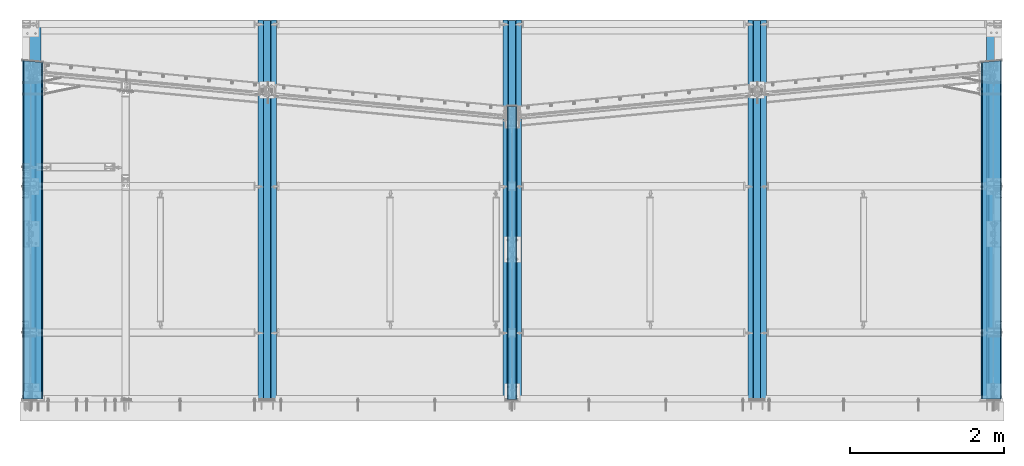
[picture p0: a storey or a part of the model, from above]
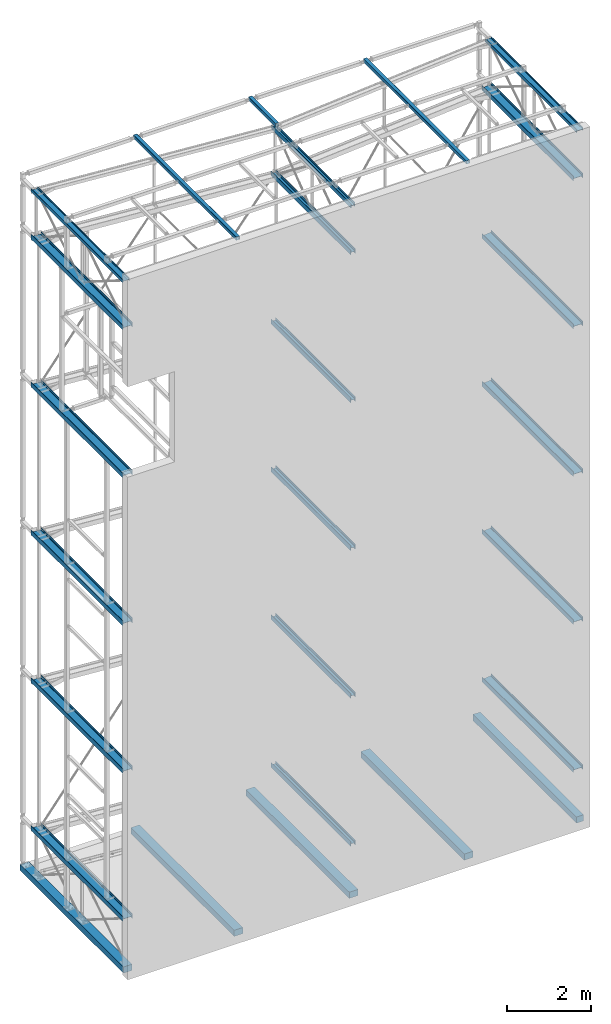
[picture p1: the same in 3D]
Properties of the parts of a building model (IFC2X3), part 1 of 3

# File
Description: ViewDefinition[CoordinationView_V2.0, QuantityTakeOffAddOnView], Option [BaseQuantities:On], Option [GridExport:On], Option [Assemblies:On], Option [Bolts:On], Option [Rebars:On], Option [PourObjects:Off], Option [Welds:Off], Option [SurfaceTreatments:Off], Option [LocationBy:0], Option [ViewColors:Off], Option [SectionedSpine:Off], Option [PropertySets:On], Option [Export all:On]
File name: Model-IFC.ifc
Time: 2023-10-02T23:28:33
Author: YESKON06\Patrycja Reder
Organization: Structural Designer
Written by: IFC Database Version: Work
Made in: Tekla Structures 2020 Service Pack 14, IFC Export Version: 4.0.0.0 Sep 15 2022

# IfcBuildingStorey, Undefined
In: Undefined
Elevation: 0 mm

# IfcBeam: 180*180 (3)
In: Undefined
Description: 180*180; Material: CONCRETE/C25/30
Tekla Common - Bottom elevation: -0.196; Top elevation: -0.016; Phase: 1; Class: 11
Tekla Quantity - Area per tons: 9.3 m2; Height: 180 mm; Width: 180 mm
Pset_BeamCommon - LoadBearing: no; Reference: B0(?)
Name | Weight (kg) | Volume (m3) | Gross footprint area (m2) | Net surface area (m2) | Tekla Quantity, Length (mm) | BaseQuantities, Length (mm) | OuterSurfaceArea (m2) | NetVolume (m3) | NetWeight (kg)
BELKA | 989.1 | 0.4 | 2.3 | 9.2 | 12720 | 12720 | 9.2232 | 0.412128 | 989.107
2 x BELKA | 475.6 | 0.2 | 0 | 4.5 | 6116 | 6116.04 | 4.46835 | 0.19816 | 475.583

# IfcBeam: 180*4935, BELKA
In: Undefined
Description: 180*4935; Material: CONCRETE/C25/30
Pset_BeamCommon - LoadBearing: no; Reference: B0(?)
Tekla Common - Bottom elevation: -0.196; Top elevation: -0.016; Phase: 1; Class: 1
Tekla Quantity - Weight: 27118 kg; Volume: 11.3 m3; Gross footprint area: 2.3 m2; Area per tons: 4.9 m2; Net surface area: 131.9 m2; Height: 180 mm; Width: 4935 mm; Length: 12720 mm
BaseQuantities - Length: 12720 mm; OuterSurfaceArea: 131.902 m2; NetVolume: 11.2992 m3; NetWeight: 27118 kg

# IfcBeam: BL10*135, BLACHA
In: Undefined
Description: BL10*135; Material: STEEL/S355JR
Tekla Common - Bottom elevation: +14.256; Top elevation: +14.391; Phase: 13; Class: 99
Tekla Quantity - Weight: 2.1 kg; Volume: 0 m3; Gross footprint area: 0 m2; Area per tons: 28.6 m2; Net surface area: 0.1 m2; Height: 135 mm; Width: 10 mm; Length: 200 mm
Pset_BeamCommon - LoadBearing: no; Reference: 1116(?)
BaseQuantities - Length: 199.998 mm; OuterSurfaceArea: 0.0606994 m2; NetVolume: 0.000269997 m3; NetWeight: 2.11948 kg

# IfcBeam: BL10*91 (2)
In: Undefined
Description: BL10*91; Material: STEEL/S355JR
Tekla Common - Bottom elevation: +19.959; Top elevation: +20.050; Phase: 3; Class: 99
Tekla Quantity - Weight: 2.2 kg; Volume: 0 m3; Gross footprint area: 0 m2; Area per tons: 29.1 m2; Net surface area: 0.1 m2; Height: 91 mm; Width: 10 mm; Length: 307 mm
Pset_BeamCommon - LoadBearing: no; Reference: 1057
BaseQuantities - Length: 307 mm; OuterSurfaceArea: 0.063834 m2; NetVolume: 0.00027937 m3; NetWeight: 2.19305 kg

# IfcBeam: BL12*110 (2)
In: Undefined
Description: BL12*110; Material: STEEL/S355JR
Tekla Common - Bottom elevation: +19.949; Top elevation: +20.059; Phase: 2; Class: 99
Tekla Quantity - Weight: 2 kg; Volume: 0 m3; Gross footprint area: 0 m2; Area per tons: 24.9 m2; Net surface area: 0 m2; Height: 110 mm; Width: 12 mm; Length: 190 mm
Pset_BeamCommon - LoadBearing: no; Reference: 1034
BaseQuantities - Length: 190 mm; OuterSurfaceArea: 0.049 m2; NetVolume: 0.0002508 m3; NetWeight: 1.96878 kg

# IfcBeam: BL12*120 (5)
In: Undefined
Description: BL12*120; Material: STEEL/S355JR
Tekla Common - Phase: 13; Class: 99
Tekla Quantity - Weight: 1.7 kg; Volume: 0 m3; Gross footprint area: 0 m2; Net surface area: 0 m2; Height: 120 mm; Width: 12 mm
Pset_BeamCommon - LoadBearing: no
Name | Bottom elevation | Top elevation | Area per tons (m2) | Tekla Quantity, Length (mm) = BaseQuantities, Length (mm) | Reference | OuterSurfaceArea (m2) | NetVolume (m3) | NetWeight (kg)
BLACHA_PODSTAWY | +14.242 | +14.392 | 25.1 | 150 | 1104 | 0.04248 | 0.000216 | 1.6956
BLACHA_PODSTAWY | +14.654 | +14.814 | 24.9 | 160 | 1102 | 0.04512 | 0.0002304 | 1.80864
BLACHA_PODSTAWY | +16.014 | +16.174 | 24.9 | 160 | 1102 | 0.04512 | 0.0002304 | 1.80864
BLACHA_PODSTAWY | +17.144 | +17.294 | 25.1 | 150 | 1104 | 0.04248 | 0.000216 | 1.6956
BLACHA_PODSTAWY | +17.144 | +17.304 | 24.9 | 160 | 1102 | 0.04512 | 0.0002304 | 1.80864

# IfcBeam: BL12*135 (10)
In: Undefined
Description: BL12*135; Material: STEEL/S355JR
Tekla Common - Phase: 3; Class: 99
Tekla Quantity - Weight: 5.8 kg; Volume: 0 m3; Gross footprint area: 0 m2; Area per tons: 23.7 m2; Net surface area: 0.1 m2; Height: 135 mm; Width: 12 mm; Length: 461 mm
Pset_BeamCommon - LoadBearing: no; Reference: 1026
BaseQuantities - Length: 461 mm; OuterSurfaceArea: 0.138774 m2; NetVolume: 0.00074682 m3; NetWeight: 5.86254 kg
Name | Bottom elevation | Top elevation
2 x BLACHA | +5.617 | +5.752
2 x BLACHA | +9.937 | +10.072
2 x BLACHA | +14.257 | +14.392
2 x BLACHA | +18.577 | +18.712
2 x BLACHA | +1.297 | +1.432

# IfcBeam: BL12*160 (6)
In: Undefined
Description: BL12*160; Material: STEEL/S355JR
Tekla Common - Phase: 5; Class: 99
Tekla Quantity - Volume: 0 m3; Gross footprint area: 0 m2; Height: 160 mm; Width: 12 mm
Pset_BeamCommon - LoadBearing: no
Name | Bottom elevation | Top elevation | Weight (kg) | Area per tons (m2) | Net surface area (m2) | Tekla Quantity, Length (mm) = BaseQuantities, Length (mm) | Reference | OuterSurfaceArea (m2) | NetVolume (m3) | NetWeight (kg)
BLACHA_PODSTAWY | +1.284 | +1.444 | 2.3 | 24.5 | 0.1 | 153 | 1038 | 0.056472 | 0.00029376 | 2.30602
BLACHA_PODSTAWY | +19.924 | +20.084 | 2 | 24.7 | 0 | 134 | 1039 | 0.049936 | 0.00025728 | 2.01965
BLACHA_PODSTAWY | +18.564 | +18.724 | 2.3 | 24.5 | 0.1 | 153 | 1038 | 0.056472 | 0.00029376 | 2.30602
BLACHA_PODSTAWY | +5.604 | +5.764 | 2.3 | 24.5 | 0.1 | 153 | 1038 | 0.056472 | 0.00029376 | 2.30602
BLACHA_PODSTAWY | +9.924 | +10.084 | 2.3 | 24.5 | 0.1 | 153 | 1038 | 0.056472 | 0.00029376 | 2.30602
BLACHA_PODSTAWY | +14.244 | +14.404 | 2.3 | 24.5 | 0.1 | 153 | 1038 | 0.056472 | 0.00029376 | 2.30602

# IfcBeam: BL12*165 (2)
In: Undefined
Description: BL12*165; Material: STEEL/S355JR
Tekla Common - Bottom elevation: +20.039; Top elevation: +20.204; Phase: 4; Class: 99
Tekla Quantity - Weight: 3.1 kg; Volume: 0 m3; Gross footprint area: 0 m2; Area per tons: 24 m2; Net surface area: 0.1 m2; Height: 165 mm; Width: 12 mm; Length: 200 mm
Pset_BeamCommon - LoadBearing: no; Reference: 1045
BaseQuantities - Length: 200 mm; OuterSurfaceArea: 0.07476 m2; NetVolume: 0.000396 m3; NetWeight: 3.1086 kg

# IfcBeam: BL16*148, BLACHA_PODSTAWY
In: Undefined
Description: BL16*148; Material: STEEL/S355JR
Tekla Common - Bottom elevation: +14.244; Top elevation: +14.392; Phase: 2; Class: 99
Tekla Quantity - Weight: 5.1 kg; Volume: 0 m3; Gross footprint area: 0 m2; Area per tons: 18.6 m2; Net surface area: 0.1 m2; Height: 148 mm; Width: 16 mm; Length: 280 mm
Pset_BeamCommon - LoadBearing: no; Reference: 1106
BaseQuantities - Length: 280 mm; OuterSurfaceArea: 0.096576 m2; NetVolume: 0.00066304 m3; NetWeight: 5.20486 kg

# IfcBeam: BL16*160 (9)
In: Undefined
Description: BL16*160; Material: STEEL/S355JR
Tekla Common - Phase: 2; Class: 99
Tekla Quantity - Weight: 5.6 kg; Volume: 0 m3; Gross footprint area: 0 m2; Area per tons: 18.4 m2; Net surface area: 0.1 m2; Height: 160 mm; Width: 16 mm; Length: 280 mm
Pset_BeamCommon - LoadBearing: no
BaseQuantities - Length: 280 mm; OuterSurfaceArea: 0.10368 m2; NetVolume: 0.0007168 m3; NetWeight: 5.62688 kg
Name | Bottom elevation | Top elevation | Reference
BLACHA_PODSTAWY | +1.284 | +1.444 | 1033
2 x BLACHA_PODSTAWY | +5.604 | +5.764 | 1033
2 x BLACHA_PODSTAWY | +9.924 | +10.084 | 1033
BLACHA_PODSTAWY | +14.244 | +14.404 | 1033
2 x BLACHA_PODSTAWY | +18.564 | +18.724 | 1033
BLACHA_PODSTAWY | +1.284 | +1.444 | 1033(?)

# IfcBeam: BL4*100 (15)
In: Undefined
Description: BL4*100; Material: STEEL/S355JR
Tekla Quantity - Weight: 0.4 kg; Volume: 0 m3; Gross footprint area: 0 m2; Area per tons: 68.8 m2; Net surface area: 0 m2; Height: 100 mm; Width: 4 mm; Length: 100 mm
BaseQuantities - Length: 100 mm; OuterSurfaceArea: 0.0216 m2; NetVolume: 0.00004 m3; NetWeight: 0.314 kg
Tekla Common - Class: 99
Pset_BeamCommon - LoadBearing: no
Name | Bottom elevation | Top elevation | Phase | Reference
BLACHA | +20.104 | +20.204 | 5 | 1064
2 x BLACHA | +20.104 | +20.204 | 4 | 1064
BLACHA | +1.314 | +1.414 | 2 | 1064(?)
2 x BLACHA | +5.634 | +5.734 | 2 | 1064
2 x BLACHA | +9.954 | +10.054 | 2 | 1064
2 x BLACHA | +14.274 | +14.374 | 2 | 1064
2 x BLACHA | +18.594 | +18.694 | 2 | 1064
2 x BLACHA | +19.954 | +20.054 | 2 | 1064
BLACHA | +1.314 | +1.414 | 2 | 1064

# IfcBeam: BL6*120, BLACHA
In: Undefined
Description: BL6*120; Material: STEEL/S355JR
Tekla Common - Bottom elevation: +19.944; Top elevation: +20.064; Phase: 5; Class: 99
Tekla Quantity - Weight: 0.7 kg; Volume: 0 m3; Gross footprint area: 0 m2; Area per tons: 47 m2; Net surface area: 0 m2; Height: 120 mm; Width: 6 mm; Length: 104 mm
Pset_BeamCommon - LoadBearing: no; Reference: 1043
BaseQuantities - Length: 104 mm; OuterSurfaceArea: 0.027648 m2; NetVolume: 0.00007488 m3; NetWeight: 0.587808 kg

# IfcBeam: BL6*160 (2)
In: Undefined
Description: BL6*160; Material: STEEL/S355JR
Tekla Common - Bottom elevation: +19.894; Top elevation: +20.054; Phase: 2; Class: 99
Tekla Quantity - Weight: 1.5 kg; Volume: 0 m3; Gross footprint area: 0 m2; Area per tons: 45.5 m2; Net surface area: 0.1 m2; Height: 160 mm; Width: 6 mm; Length: 180.8 mm
Pset_BeamCommon - LoadBearing: no; Reference: 1056
BaseQuantities - Length: 180.799 mm; OuterSurfaceArea: 0.0619453 m2; NetVolume: 0.000173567 m3; NetWeight: 1.3625 kg

# IfcBeam: BL8*140 (5)
In: Undefined
Description: BL8*140; Material: STEEL/S355JR
Tekla Common - Phase: 5; Class: 99
Tekla Quantity - Weight: 1.1 kg; Volume: 0 m3; Gross footprint area: 0 m2; Area per tons: 35.7 m2; Net surface area: 0 m2; Height: 140 mm; Width: 8 mm; Length: 123 mm
Pset_BeamCommon - LoadBearing: no; Reference: 1040
BaseQuantities - Length: 123 mm; OuterSurfaceArea: 0.038648 m2; NetVolume: 0.00013776 m3; NetWeight: 1.08142 kg
Name | Bottom elevation | Top elevation
BLACHA | +18.574 | +18.714
BLACHA | +14.254 | +14.394
BLACHA | +5.614 | +5.754
BLACHA | +1.294 | +1.434
BLACHA | +9.934 | +10.074

# IfcBeam: BL8*220 (10)
In: Undefined
Description: BL8*220; Material: STEEL/S355JR
Tekla Common - Phase: 2; Class: 99
Tekla Quantity - Weight: 3.7 kg; Volume: 0 m3; Gross footprint area: 0 m2; Area per tons: 33.9 m2; Net surface area: 0.1 m2; Height: 220 mm; Width: 8 mm; Length: 271.2 mm
Pset_BeamCommon - LoadBearing: no
BaseQuantities - Length: 271.199 mm; OuterSurfaceArea: 0.127187 m2; NetVolume: 0.00047731 m3; NetWeight: 3.74688 kg
Name | Bottom elevation | Top elevation | Reference
BLACHA | +5.574 | +5.794 | 1029
2 x BLACHA | +9.894 | +10.114 | 1029
2 x BLACHA | +14.214 | +14.434 | 1029
2 x BLACHA | +18.534 | +18.754 | 1029
BLACHA | +5.574 | +5.794 | 1024
BLACHA | +1.254 | +1.474 | 1029(?)
BLACHA | +1.254 | +1.474 | 1024

# IfcBeam: IPE180 (2)
In: Undefined
Description: IPE180; Material: STEEL/S355JR
Tekla Common - Bottom elevation: +19.959; Top elevation: +20.050; Phase: 3; Class: 5
Tekla Quantity - Weight: 115.1 kg; Volume: 0 m3; Gross footprint area: 0 m2; Area per tons: 37.2 m2; Net surface area: 4.5 m2; Height: 180 mm; Width: 91 mm; Length: 6133 mm
Pset_BeamCommon - LoadBearing: yes
BaseQuantities - Length: 6133.02 mm; OuterSurfaceArea: 4.28085 m2; NetVolume: 0.014221 m3; NetWeight: 111.635 kg
Name | Reference
RYGIEL | 1008
RYGIEL | 1009

# IfcBeam: IPE270 (10)
In: Undefined
Description: IPE270; Material: STEEL/S355JR
Tekla Common - Phase: 3; Class: 5
Tekla Quantity - Weight: 217.4 kg; Volume: 0 m3; Gross footprint area: 0 m2; Area per tons: 29 m2; Net surface area: 6.4 m2; Height: 270 mm; Width: 135 mm; Length: 6033.5 mm
Pset_BeamCommon - LoadBearing: yes
BaseQuantities - Length: 6033.53 mm; OuterSurfaceArea: 6.28091 m2; NetVolume: 0.0264436 m3; NetWeight: 207.582 kg
Name | Bottom elevation | Top elevation | Reference
2 x RYGIEL | +18.577 | +18.712 | 1003
2 x RYGIEL | +1.297 | +1.432 | 1003
2 x RYGIEL | +5.617 | +5.752 | 1003
2 x RYGIEL | +9.937 | +10.072 | 1003
RYGIEL | +14.257 | +14.392 | 1004
RYGIEL | +14.257 | +14.392 | 1003

# IfcBeam: L120*80*8 (4)
In: Undefined
Description: L120*80*8; Material: STEEL/S355JR
Tekla Common - Phase: 1; Class: 2
Tekla Quantity - Volume: 0 m3; Gross footprint area: 0 m2; Area per tons: 32.1 m2; Height: 120 mm; Width: 80 mm
Pset_BeamCommon - LoadBearing: yes; Reference: B0(?)
Name | Bottom elevation | Top elevation | Weight (kg) | Net surface area (m2) | Tekla Quantity, Length (mm) | BaseQuantities, Length (mm) | OuterSurfaceArea (m2) | NetVolume (m3) | NetWeight (kg)
BELKA | -0.015 | +0.065 | 34.9 | 1.2 | 2870 | 2869.97 | 1.12216 | 0.00440827 | 34.6049
BELKA | -0.015 | +0.065 | 36.2 | 1.2 | 2974.4 | 2974.35 | 1.16297 | 0.0045686 | 35.8635
BELKA | -0.015 | +0.065 | 36.1 | 1.2 | 2969.4 | 2969.37 | 1.16102 | 0.00456096 | 35.8035
BELKA | -0.016 | +0.064 | 34.7 | 1.1 | 2851.9 | 2851.86 | 1.11508 | 0.00438045 | 34.3866

# IfcBeam: L80*80*6 (21)
In: Undefined
Description: L80*80*6; Material: STEEL/S355JR
Tekla Common - Phase: 6; Class: 5
Tekla Quantity - Volume: 0 m3; Gross footprint area: 0 m2; Height: 80 mm; Width: 80 mm
Pset_BeamCommon - LoadBearing: yes
Name | Bottom elevation | Top elevation | Weight (kg) | Area per tons (m2) | Net surface area (m2) | Tekla Quantity, Length (mm) = BaseQuantities, Length (mm) | Reference | OuterSurfaceArea (m2) | NetVolume (m3) | NetWeight (kg)
KĄTOWNIK | +14.312 | +14.392 | 7.3 | 44.4 | 0.3 | 1002 | K9 | 0.322488 | 0.000925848 | 7.26791
KĄTOWNIK | +16.184 | +17.134 | 6.9 | 44.4 | 0.3 | 950 | K8 | 0.305848 | 0.0008778 | 6.89073
KĄTOWNIK | +17.314 | +18.554 | 9.1 | 44.3 | 0.3 | 1240 | K12 | 0.398648 | 0.00114576 | 8.99422
KĄTOWNIK | +14.402 | +14.645 | 1.7 | 45.2 | 0.1 | 243 | K7 | 0.079608 | 0.000224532 | 1.76258
KĄTOWNIK | +17.144 | +17.224 | 8.5 | 44.3 | 0.3 | 1152 | K10 | 0.370488 | 0.00106445 | 8.35592
KĄTOWNIK | +20.069 | +20.204 | 0.7 | 46.6 | 0 | 135 | 1097 | 0.0381067 | 0.000104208 | 0.818033
2 x KĄTOWNIK | +18.734 | +19.939 | 8.7 | 44.3 | 0.3 | 1205 | K2 | 0.387448 | 0.00111342 | 8.74035
KĄTOWNIK | +20.124 | +20.204 | 44.5 | 44.2 | 2 | 6140 | K6 | 1.96665 | 0.00567336 | 44.5359
2 x KĄTOWNIK | +10.094 | +14.234 | 30 | 44.2 | 1.2 | 4140 | K3 | 1.32665 | 0.00382536 | 30.0291
KĄTOWNIK | +5.764 | +9.904 | 30 | 44.2 | 1.2 | 4140 | K3 | 1.32665 | 0.00382536 | 30.0291
2 x KĄTOWNIK | +1.454 | +5.594 | 30 | 44.2 | 1.2 | 4140 | K3 | 1.32665 | 0.00382536 | 30.0291
2 x KĄTOWNIK | +0.069 | +1.274 | 8.7 | 44.3 | 0.3 | 1205 | K2 | 0.387448 | 0.00111342 | 8.74035
KĄTOWNIK | +20.069 | +20.204 | 0.7 | 46.6 | 0 | 135 | 1037 | 0.0381067 | 0.000104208 | 0.818033
KĄTOWNIK | +5.774 | +9.914 | 30 | 44.2 | 1.2 | 4140 | K3 | 1.32665 | 0.00382536 | 30.0291
KĄTOWNIK | +14.414 | +18.554 | 30 | 44.2 | 1.2 | 4140 | K3 | 1.32665 | 0.00382536 | 30.0291
KĄTOWNIK | +20.124 | +20.204 | 22.1 | 44.2 | 1 | 3070 | 1014 | 0.977307 | 0.00281615 | 22.1068
KĄTOWNIK | +20.124 | +20.204 | 22.1 | 44.2 | 1 | 3070 | 1010 | 0.977307 | 0.00281615 | 22.1068

# IfcBeam: PL220*16 (6)
In: Undefined
Description: PL220*16; Material: STEEL/S355JR
Pset_BeamCommon - LoadBearing: yes; Reference: B0(?)
Tekla Common - Bottom elevation: -0.016; Top elevation: +0.000; Phase: 1; Class: 5
Tekla Quantity - Volume: 0 m3; Gross footprint area: 0 m2; Net surface area: 0.1 m2; Height: 220 mm; Width: 16 mm
Name | Weight (kg) | Area per tons (m2) | Tekla Quantity, Length (mm) = BaseQuantities, Length (mm) | OuterSurfaceArea (m2) | NetVolume (m3) | NetWeight (kg)
4 x BELKA | 5.5 | 18.4 | 200 | 0.10144 | 0.000704 | 5.5264
2 x BELKA | 6.1 | 18.2 | 220 | 0.11088 | 0.0007744 | 6.07904

# IfcBeam: PL240*16 (3)
In: Undefined
Description: PL240*16; Material: STEEL/S355JR
Pset_BeamCommon - LoadBearing: yes; Reference: B0(?)
Tekla Common - Bottom elevation: -0.016; Top elevation: +0.000; Phase: 1; Class: 5
Tekla Quantity - Weight: 6 kg; Volume: 0 m3; Gross footprint area: 0 m2; Area per tons: 18.3 m2; Net surface area: 0.1 m2; Height: 240 mm; Width: 16 mm; Length: 200 mm
BaseQuantities - Length: 200 mm; OuterSurfaceArea: 0.11008 m2; NetVolume: 0.000768 m3; NetWeight: 6.0288 kg

# IfcBeam: PL300*16 (3)
In: Undefined
Description: PL300*16; Material: STEEL/S355JR
Pset_BeamCommon - LoadBearing: yes; Reference: B0(?)
Tekla Common - Bottom elevation: -0.016; Top elevation: +0.000; Phase: 1; Class: 5
Tekla Quantity - Weight: 7.5 kg; Volume: 0 m3; Gross footprint area: 0 m2; Area per tons: 18 m2; Net surface area: 0.1 m2; Height: 300 mm; Width: 16 mm; Length: 200 mm
BaseQuantities - Length: 200 mm; OuterSurfaceArea: 0.136 m2; NetVolume: 0.00096 m3; NetWeight: 7.536 kg

# IfcBeam: PL340*16 (3)
In: Undefined
Description: PL340*16; Material: STEEL/S355JR
Pset_BeamCommon - LoadBearing: yes; Reference: B0(?)
Tekla Common - Bottom elevation: -0.016; Top elevation: +0.000; Phase: 1; Class: 5
Tekla Quantity - Volume: 0 m3; Gross footprint area: 0 m2; Net surface area: 0.2 m2; Height: 340 mm; Width: 16 mm
Name | Weight (kg) | Area per tons (m2) | Tekla Quantity, Length (mm) = BaseQuantities, Length (mm) | OuterSurfaceArea (m2) | NetVolume (m3) | NetWeight (kg)
2 x BELKA | 8.5 | 18 | 200 | 0.15328 | 0.001088 | 8.5408
BELKA | 9.4 | 17.8 | 220 | 0.16752 | 0.0011968 | 9.39488

# IfcBeam: SHS100*3 (78)
In: Undefined
Description: SHS100*3; Material: STEEL/S355JR
Tekla Common - Class: 5
Tekla Quantity - Volume: 0 m3; Height: 100 mm; Width: 100 mm
Pset_BeamCommon - LoadBearing: yes
Name | Bottom elevation | Top elevation | Phase | Weight (kg) | Gross footprint area (m2) | Area per tons (m2) | Net surface area (m2) | Tekla Quantity, Length (mm) | Reference | BaseQuantities, Length (mm) | OuterSurfaceArea (m2) | NetVolume (m3) | NetWeight (kg)
2 x TĘŻNIK | -0.192 | -0.064 | 12 | 1.2 | 0 | 44.8 | 0.1 | 128 | 0(?) | 128 | 0.0524 | 0.000148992 | 1.16959
2 x RYGIEL | +14.490 | +17.046 | 12 | 23.4 | 0.3 | 43.8 | 1 | 2556.5 | 1108 | 2556.5 | 1.0238 | 0.00297577 | 23.3598
2 x RYGIEL | +18.736 | +19.935 | 12 | 10.9 | 0.1 | 44 | 0.5 | 1199 | 1136 | 1199 | 0.478592 | 0.00138646 | 10.8837
2 x RYGIEL | +0.082 | +1.273 | 12 | 10.9 | 0.1 | 44 | 0.5 | 1191 | 1136(?) | 1191 | 0.475757 | 0.0013783 | 10.8196
RYGIEL | +14.456 | +18.513 | 12 | 37.1 | 0.3 | 43.8 | 1.6 | 4056.8 | 1111 | 4056.8 | 1.62392 | 0.00472212 | 37.0686
RYGIEL | +17.144 | +17.244 | 12 | 9.1 | 0.1 | 44 | 0.3 | 996 | 1110 | 996 | 0.3996 | 0.00115934 | 9.10085
RYGIEL | +14.292 | +14.392 | 12 | 7.5 | 0.1 | 44 | 0.3 | 826 | 1109 | 826 | 0.3316 | 0.000961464 | 7.54749
SŁUPEK | +14.292 | +14.392 | 13 | 36.6 | 0 | 43.8 | 1.6 | 4006.3 | 1099 | 4006.34 | 1.60185 | 0.00465789 | 36.5644
SŁUPEK | +14.714 | +14.814 | 13 | 24.9 | 0 | 43.8 | 1.1 | 2720 | 1098 | 2720 | 1.0892 | 0.00316608 | 24.8537
SŁUPEK | +16.014 | +16.114 | 13 | 24.9 | 0 | 43.8 | 1.1 | 2720 | 1098 | 2720 | 1.0892 | 0.00316608 | 24.8537
SŁUPEK | +17.144 | +17.244 | 13 | 35.9 | 0 | 43.8 | 1.6 | 3930 | 1096 | 3930 | 1.5732 | 0.00457452 | 35.91
SŁUPEK | +17.144 | +17.244 | 13 | 26.2 | 0 | 43.8 | 1.1 | 2870 | 1095 | 2870 | 1.1492 | 0.00334068 | 26.2243
3 x RYGIEL | +14.416 | +18.553 | 12 | 37.7 | 0.3 | 43.8 | 1.7 | 4137 | 1052 | 4137 | 1.65378 | 0.00480623 | 37.7289
4 x RYGIEL | +10.096 | +14.233 | 12 | 37.7 | 0.3 | 43.8 | 1.7 | 4137 | 1052 | 4137 | 1.65378 | 0.00480623 | 37.7289
4 x RYGIEL | +5.776 | +9.913 | 12 | 37.7 | 0.3 | 43.8 | 1.7 | 4137 | 1052 | 4137 | 1.65378 | 0.00480623 | 37.7289
4 x RYGIEL | +1.456 | +5.593 | 12 | 37.7 | 0.3 | 43.8 | 1.7 | 4137 | 1052 | 4137 | 1.65378 | 0.00480623 | 37.7289
2 x RYGIEL ATTYKOWY | +20.104 | +20.204 | 7 | 26.2 | 0.3 | 43.8 | 1.1 | 2864 | 1019 | 2864 | 1.1468 | 0.0033337 | 26.1695
2 x TĘŻNIK | -0.192 | -0.064 | 12 | 1.2 | 0 | 44.8 | 0.1 | 128 | 1023(?) | 128 | 0.0524 | 0.000148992 | 1.16959
4 x TĘŻNIK | +20.058 | +20.200 | 2 | 1.2 | 0 | 44.7 | 0.1 | 142.5 | 1055 | 142.5 | 0.0582 | 0.00016587 | 1.30208
3 x TĘŻNIK | +20.072 | +20.200 | 5 | 1.2 | 0 | 44.8 | 0.1 | 128 | 1023 | 128 | 0.0524 | 0.000148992 | 1.16959
4 x RYGIEL | +20.104 | +20.204 | 12 | 25.7 | 0.3 | 43.8 | 1.1 | 2814 | 1054 | 2814 | 1.1268 | 0.0032755 | 25.7126
4 x RYGIEL | +20.104 | +20.204 | 12 | 26.2 | 0.3 | 43.8 | 1.1 | 2864 | 1053 | 2864 | 1.1468 | 0.0033337 | 26.1695
SŁUPEK | +1.314 | +1.414 | 2 | 4.7 | 0 | 44 | 0.2 | 524.2 | 1020 | 524.235 | 0.20901 | 0.000604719 | 4.74705
2 x SŁUPEK | +5.634 | +5.734 | 2 | 4.7 | 0 | 44 | 0.2 | 524.2 | 1020 | 524.235 | 0.20901 | 0.000604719 | 4.74705
2 x SŁUPEK | +9.954 | +10.054 | 2 | 4.7 | 0 | 44 | 0.2 | 524.2 | 1020 | 524.235 | 0.20901 | 0.000604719 | 4.74705
2 x SŁUPEK | +14.274 | +14.374 | 2 | 4.7 | 0 | 44 | 0.2 | 524.2 | 1020 | 524.235 | 0.20901 | 0.000604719 | 4.74705
2 x SŁUPEK | +19.954 | +20.054 | 2 | 4.7 | 0 | 44 | 0.2 | 524.2 | 1020 | 524.235 | 0.20901 | 0.000604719 | 4.74705
2 x SŁUPEK | +18.594 | +18.694 | 2 | 4.7 | 0 | 44 | 0.2 | 524.2 | 1020 | 524.235 | 0.20901 | 0.000604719 | 4.74705
SŁUPEK | +1.314 | +1.414 | 2 | 4.7 | 0 | 44 | 0.2 | 524.2 | 1020(?) | 524.235 | 0.20901 | 0.000604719 | 4.74705
2 x RYGIEL ATTYKOWY | +20.104 | +20.204 | 7 | 25.7 | 0.3 | 43.8 | 1.1 | 2814 | 1018 | 2814 | 1.1268 | 0.0032755 | 25.7126
2 x RYGIEL ATTYKOWY | +20.054 | +20.200 | 2 | 1.2 | 0 | 44.7 | 0.1 | 146 | 1017 | 146 | 0.0596 | 0.000169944 | 1.33406
RYGIEL ATTYKOWY | +0.117 | +1.216 | 7 | 10 | 0.1 | 44 | 0.3 | 1099 | 1015(?) | 1099 | 0.4408 | 0.00127924 | 10.042
RYGIEL ATTYKOWY | +1.532 | +5.536 | 7 | 36.6 | 0.3 | 43.8 | 1.6 | 4004 | 1016 | 4004 | 1.6028 | 0.00466066 | 36.5861
RYGIEL ATTYKOWY | +5.852 | +9.856 | 7 | 36.6 | 0.3 | 43.8 | 1.6 | 4004 | 1016 | 4004 | 1.6028 | 0.00466066 | 36.5861
RYGIEL ATTYKOWY | +10.172 | +14.176 | 7 | 36.6 | 0.3 | 43.8 | 1.6 | 4004 | 1016 | 4004 | 1.6028 | 0.00466066 | 36.5861
RYGIEL ATTYKOWY | +14.492 | +18.496 | 7 | 36.6 | 0.3 | 43.8 | 1.6 | 4004 | 1016 | 4004 | 1.6028 | 0.00466066 | 36.5861
RYGIEL ATTYKOWY | +18.812 | +19.856 | 7 | 9.4 | 0.1 | 44 | 0.3 | 1044 | 1015 | 1044 | 0.4188 | 0.00121522 | 9.53945
RYGIEL ATTYKOWY | +0.098 | +1.196 | 7 | 10 | 0.1 | 44 | 0.3 | 1098 | 1015(?) | 1098 | 0.4404 | 0.00127807 | 10.0329
RYGIEL ATTYKOWY | +1.512 | +5.516 | 7 | 36.6 | 0.3 | 43.8 | 1.6 | 4004 | 1016 | 4004 | 1.6028 | 0.00466066 | 36.5861
RYGIEL ATTYKOWY | +5.832 | +9.836 | 7 | 36.6 | 0.3 | 43.8 | 1.6 | 4004 | 1016 | 4004 | 1.6028 | 0.00466066 | 36.5861
RYGIEL ATTYKOWY | +10.152 | +14.156 | 7 | 36.6 | 0.3 | 43.8 | 1.6 | 4004 | 1016 | 4004 | 1.6028 | 0.00466066 | 36.5861
RYGIEL ATTYKOWY | +14.472 | +18.476 | 7 | 36.6 | 0.3 | 43.8 | 1.6 | 4004 | 1016 | 4004 | 1.6028 | 0.00466066 | 36.5861
RYGIEL ATTYKOWY | +18.792 | +19.836 | 7 | 9.4 | 0.1 | 44 | 0.3 | 1044 | 1015 | 1044 | 0.4188 | 0.00121522 | 9.53945

# IfcBeam: SHS60*3 (38)
In: Undefined
Description: SHS60*3; Material: STEEL/S355JR
Pset_BeamCommon - LoadBearing: yes
Tekla Common - Class: 5
Tekla Quantity - Volume: 0 m3; Height: 60 mm; Width: 60 mm
Name | Reference | Bottom elevation | Top elevation | Phase | Weight (kg) | Gross footprint area (m2) | Area per tons (m2) | Net surface area (m2) | Tekla Quantity, Length (mm) | BaseQuantities, Length (mm) | OuterSurfaceArea (m2) | NetVolume (m3) | NetWeight (kg)
TĘŻNIK | 0(?) | +0.108 | +1.233 | 12 | 6 | 0.1 | 44.8 | 0.3 | 1125 | 1125.05 | 0.270732 | 0.000769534 | 6.04084
2 x TĘŻNIK | 1154 | +20.018 | +20.104 | 4 | 0.4 | 0 | 46.3 | 0 | 86.3 | 86.35 | 0.021444 | 0.0000590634 | 0.463648
TĘŻNIK | 1147(?) | +0.154 | +1.208 | 8 | 5.5 | 0.1 | 45.1 | 0.2 | 1053.7 | 1053.72 | 0.249361 | 0.000704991 | 5.53418
TĘŻNIK | 1147 | +18.801 | +19.848 | 8 | 5.5 | 0.1 | 45.1 | 0.2 | 1046.7 | 1046.72 | 0.247681 | 0.000700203 | 5.4966
2 x TĘŻNIK | 1138 | +18.792 | +19.857 | 8 | 5.6 | 0.1 | 45.1 | 0.3 | 1065.8 | 1065.82 | 0.252264 | 0.000713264 | 5.59912
TĘŻNIK | 1138(?) | +0.134 | +1.217 | 8 | 5.8 | 0.1 | 44.9 | 0.3 | 1082.5 | 1082.52 | 0.258403 | 0.000732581 | 5.75076
TĘŻNIK | 1138(?) | +0.144 | +1.216 | 8 | 5.6 | 0.1 | 45.1 | 0.3 | 1072 | 1072.01 | 0.253768 | 0.000717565 | 5.63288
2 x TĘŻNIK | 1047 | +14.537 | +18.432 | 8 | 20.8 | 0 | 44.8 | 1 | 3895.4 | 3895.38 | 0.931358 | 0.00264868 | 20.7921
TĘŻNIK | 1021 | +14.465 | +18.504 | 8 | 21.7 | 0.2 | 44.7 | 1 | 4038.5 | 4038.5 | 0.96996 | 0.00276233 | 21.6843
2 x TĘŻNIK | 1032(?) | +0.118 | +1.233 | 8 | 6 | 0.1 | 44.8 | 0.3 | 1115.1 | 1115.1 | 0.268344 | 0.000762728 | 5.98742
TĘŻNIK | 1048 | +18.776 | +19.873 | 8 | 5.8 | 0.1 | 44.8 | 0.3 | 1097.4 | 1097.45 | 0.264108 | 0.000750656 | 5.89265
2 x TĘŻNIK | 1031 | +10.136 | +14.193 | 8 | 21.7 | 0.2 | 44.7 | 1 | 4056.8 | 4056.8 | 0.974352 | 0.00277485 | 21.7826
2 x TĘŻNIK | 1031 | +5.816 | +9.873 | 8 | 21.7 | 0.2 | 44.7 | 1 | 4056.8 | 4056.8 | 0.974352 | 0.00277485 | 21.7826
2 x TĘŻNIK | 1047 | +1.577 | +5.472 | 8 | 20.8 | 0 | 44.8 | 1 | 3895.4 | 3895.38 | 0.931358 | 0.00264868 | 20.7921
TĘŻNIK | 1032 | +18.776 | +19.893 | 8 | 6 | 0.1 | 44.8 | 0.3 | 1117.4 | 1117.45 | 0.268908 | 0.000764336 | 6.00004
TĘŻNIK | 1032(?) | +0.108 | +1.233 | 8 | 6 | 0.1 | 44.8 | 0.3 | 1125 | 1125.05 | 0.270732 | 0.000769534 | 6.04084
2 x TĘŻNIK | 1032 | +18.776 | +19.894 | 8 | 6 | 0.1 | 44.8 | 0.3 | 1118 | 1118.05 | 0.269052 | 0.000764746 | 6.00326
2 x TĘŻNIK | 1030 | +14.506 | +18.463 | 8 | 21.2 | 0.2 | 44.7 | 1 | 3957.4 | 3957.4 | 0.950496 | 0.00270686 | 21.2489
2 x TĘŻNIK | 1031 | +10.136 | +14.193 | 8 | 21.7 | 0.2 | 44.7 | 1 | 4057.4 | 4057.4 | 0.974496 | 0.00277526 | 21.7858
2 x TĘŻNIK | 1031 | +5.816 | +9.873 | 8 | 21.7 | 0.2 | 44.7 | 1 | 4057.4 | 4057.4 | 0.974496 | 0.00277526 | 21.7858
2 x TĘŻNIK | 1030 | +1.546 | +5.503 | 8 | 21.2 | 0.2 | 44.7 | 1 | 3957.4 | 3957.4 | 0.950496 | 0.00270686 | 21.2489
TĘŻNIK | 1022 | +18.785 | +19.864 | 8 | 5.8 | 0.1 | 44.8 | 0.3 | 1078.8 | 1078.75 | 0.25962 | 0.000737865 | 5.79224
TĘŻNIK | 1022(?) | +0.138 | +1.224 | 8 | 5.8 | 0.1 | 44.8 | 0.3 | 1085.8 | 1085.75 | 0.2613 | 0.000742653 | 5.82983
TĘŻNIK | 1021 | +10.145 | +14.184 | 8 | 21.7 | 0.2 | 44.7 | 1 | 4038.5 | 4038.5 | 0.96996 | 0.00276233 | 21.6843
TĘŻNIK | 1021 | +5.825 | +9.864 | 8 | 21.7 | 0.2 | 44.7 | 1 | 4038.5 | 4038.5 | 0.96996 | 0.00276233 | 21.6843
TĘŻNIK | 1021 | +1.505 | +5.544 | 8 | 21.7 | 0.2 | 44.7 | 1 | 4038.5 | 4038.5 | 0.96996 | 0.00276233 | 21.6843

# IfcBeam: SHS80*3 (20)
In: Undefined
Description: SHS80*3; Material: STEEL/S355JR
Tekla Common - Phase: 13; Class: 5
Tekla Quantity - Weight: 11.6 kg; Volume: 0 m3; Gross footprint area: 0 m2; Area per tons: 44.2 m2; Net surface area: 0.5 m2; Height: 80 mm; Width: 80 mm; Length: 1604 mm
Pset_BeamCommon - LoadBearing: yes; Reference: 1118
BaseQuantities - Length: 1604 mm; OuterSurfaceArea: 0.51424 m2; NetVolume: 0.0014821 m3; NetWeight: 11.6345 kg
Name | Bottom elevation | Top elevation
5 x SŁUPEK | +20.124 | +20.204
SŁUPEK | +4.459 | +4.539
SŁUPEK | +3.319 | +3.399
SŁUPEK | +3.039 | +3.119
SŁUPEK | +1.659 | +1.739
SŁUPEK | +9.630 | +9.710
SŁUPEK | +8.250 | +8.330
2 x SŁUPEK | +11.372 | +11.452
SŁUPEK | +7.114 | +7.194
SŁUPEK | +8.494 | +8.574
SŁUPEK | +15.754 | +15.834
SŁUPEK | +17.134 | +17.214
SŁUPEK | +2.732 | +2.812
SŁUPEK | +4.237 | +4.317
SŁUPEK | +12.877 | +12.957

# IfcColumn: 180*200, SŁUP
In: Undefined
Description: 180*200; Material: CONCRETE/C25/30
Tekla Common - Bottom elevation: -0.196; Top elevation: -0.016; Phase: 1; Class: 6
Tekla Quantity - Weight: 427.7 kg; Volume: 0.2 m3; Gross footprint area: 0 m2; Area per tons: 9 m2; Net surface area: 3.8 m2; Height: 180 mm; Width: 200 mm; Length: 4950 mm
Pset_ColumnCommon - LoadBearing: no; Reference: SL0(?)
BaseQuantities - Length: 4950 mm; OuterSurfaceArea: 3.834 m2; NetVolume: 0.1782 m3; NetWeight: 427.68 kg

# IfcColumn: 180*240 (4)
In: Undefined
Description: 180*240; Material: CONCRETE/C25/30
Tekla Common - Bottom elevation: -0.196; Top elevation: -0.016; Phase: 1; Class: 6
Tekla Quantity - Weight: 513.2 kg; Volume: 0.2 m3; Gross footprint area: 0 m2; Area per tons: 8.3 m2; Net surface area: 4.2 m2; Height: 180 mm; Width: 240 mm; Length: 4950 mm
Pset_ColumnCommon - LoadBearing: no
BaseQuantities - Length: 4950 mm; OuterSurfaceArea: 4.2444 m2; NetVolume: 0.21384 m3; NetWeight: 513.216 kg
Name | Reference
SŁUP | Beton_SL-10(?)
3 x SŁUP | SL0(?)

# IfcColumn: BL10*180 (2)
In: Undefined
Description: BL10*180; Material: STEEL/S355JR
Tekla Common - Bottom elevation: +20.008; Top elevation: +20.018; Phase: 4; Class: 99
Tekla Quantity - Weight: 1.5 kg; Volume: 0 m3; Gross footprint area: 0 m2; Area per tons: 29.4 m2; Net surface area: 0 m2; Height: 180 mm; Width: 10 mm; Length: 100 mm
Pset_ColumnCommon - LoadBearing: no; Reference: 1155
BaseQuantities - Length: 100 mm; OuterSurfaceArea: 0.0416 m2; NetVolume: 0.00018 m3; NetWeight: 1.413 kg

# IfcColumn: BL16*105 (2)
In: Undefined
Description: BL16*105; Material: STEEL/S355JR
Tekla Common - Bottom elevation: +19.952; Top elevation: +20.057; Phase: 3; Class: 99
Tekla Quantity - Weight: 2.5 kg; Volume: 0 m3; Gross footprint area: 0 m2; Area per tons: 19.7 m2; Net surface area: 0 m2; Height: 105 mm; Width: 16 mm; Length: 185.8 mm
Pset_ColumnCommon - LoadBearing: no; Reference: 1044
BaseQuantities - Length: 185.832 mm; OuterSurfaceArea: 0.0483315 m2; NetVolume: 0.000312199 m3; NetWeight: 2.45076 kg

# IfcColumn: BL16*110 (2)
In: Undefined
Description: BL16*110; Material: STEEL/S355JR
Tekla Common - Bottom elevation: +19.949; Top elevation: +20.059; Phase: 3; Class: 99
Tekla Quantity - Weight: 4 kg; Volume: 0 m3; Gross footprint area: 0 m2; Area per tons: 19.1 m2; Net surface area: 0.1 m2; Height: 110 mm; Width: 16 mm; Length: 286 mm
Pset_ColumnCommon - LoadBearing: no; Reference: 1059
BaseQuantities - Length: 286.007 mm; OuterSurfaceArea: 0.0755938 m2; NetVolume: 0.000503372 m3; NetWeight: 3.95147 kg

# IfcColumn: BL20*150 (10)
In: Undefined
Description: BL20*150; Material: STEEL/S355JR
Tekla Common - Phase: 3; Class: 99
Tekla Quantity - Weight: 6.5 kg; Volume: 0 m3; Gross footprint area: 0 m2; Area per tons: 15.4 m2; Net surface area: 0.1 m2; Height: 150 mm; Width: 20 mm; Length: 276.2 mm
Pset_ColumnCommon - LoadBearing: no; Reference: 1041
BaseQuantities - Length: 276.228 mm; OuterSurfaceArea: 0.0999174 m2; NetVolume: 0.000828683 m3; NetWeight: 6.50516 kg
Name | Bottom elevation | Top elevation
2 x BLACHA | +18.569 | +18.719
2 x BLACHA | +14.249 | +14.399
2 x BLACHA | +5.609 | +5.759
2 x BLACHA | +1.289 | +1.439
2 x BLACHA | +9.929 | +10.079

# IfcColumn: BL20*155 (10)
In: Undefined
Description: BL20*155; Material: STEEL/S355JR
Tekla Common - Phase: 3; Class: 99
Tekla Quantity - Weight: 10.4 kg; Volume: 0 m3; Gross footprint area: 0 m2; Area per tons: 15 m2; Net surface area: 0.2 m2; Height: 155 mm; Width: 20 mm; Length: 426.4 mm
Pset_ColumnCommon - LoadBearing: no; Reference: 1028
BaseQuantities - Length: 426.447 mm; OuterSurfaceArea: 0.155457 m2; NetVolume: 0.00132199 m3; NetWeight: 10.3776 kg
Name | Bottom elevation | Top elevation
2 x BLACHA | +5.607 | +5.762
2 x BLACHA | +9.927 | +10.082
2 x BLACHA | +14.247 | +14.402
2 x BLACHA | +18.567 | +18.722
2 x BLACHA | +1.287 | +1.442

# IfcColumn: BL4*100 (87)
In: Undefined
Description: BL4*100; Material: STEEL/S355JR
Tekla Common - Class: 99
Tekla Quantity - Volume: 0 m3; Gross footprint area: 0 m2; Net surface area: 0 m2; Height: 100 mm; Width: 4 mm
Pset_ColumnCommon - LoadBearing: no
Name | Bottom elevation | Top elevation | Phase | Weight (kg) | Area per tons (m2) | Tekla Quantity, Length (mm) = BaseQuantities, Length (mm) | Reference | OuterSurfaceArea (m2) | NetVolume (m3) | NetWeight (kg)
BLACHA | -0.196 | -0.192 | 12 | 0.4 | 68.8 | 100 | 0(?) | 0.0216 | 0.00004 | 0.314
4 x BLACHA | +19.935 | +19.939 | 12 | 0.1 | 71.9 | 45 | 1068 | 0.01016 | 0.000018 | 0.1413
4 x BLACHA | +18.732 | +18.736 | 12 | 0.1 | 71.9 | 45 | 1068 | 0.01016 | 0.000018 | 0.1413
4 x BLACHA | +0.078 | +0.082 | 12 | 0.1 | 71.9 | 45 | 1068(?) | 0.01016 | 0.000018 | 0.1413
3 x BLACHA | +1.273 | +1.277 | 12 | 0.1 | 71.9 | 45 | 1068(?) | 0.01016 | 0.000018 | 0.1413
BLACHA | +1.273 | +1.277 | 12 | 0.1 | 71.9 | 45 | 1068 | 0.01016 | 0.000018 | 0.1413
6 x BLACHA | +20.200 | +20.204 | 2 | 0.4 | 68.8 | 100 | 1064 | 0.0216 | 0.00004 | 0.314
3 x BLACHA | +20.200 | +20.204 | 5 | 0.4 | 68.8 | 100 | 1064 | 0.0216 | 0.00004 | 0.314
BLACHA | -0.196 | -0.192 | 12 | 0.4 | 68.8 | 100 | 1064(?) | 0.0216 | 0.00004 | 0.314
6 x BLACHA | +18.553 | +18.557 | 12 | 0.1 | 71.9 | 45 | 1068 | 0.01016 | 0.000018 | 0.1413
6 x BLACHA | +14.412 | +14.416 | 12 | 0.1 | 71.9 | 45 | 1068 | 0.01016 | 0.000018 | 0.1413
8 x BLACHA | +14.233 | +14.237 | 12 | 0.1 | 71.9 | 45 | 1068 | 0.01016 | 0.000018 | 0.1413
8 x BLACHA | +9.913 | +9.917 | 12 | 0.1 | 71.9 | 45 | 1068 | 0.01016 | 0.000018 | 0.1413
8 x BLACHA | +5.593 | +5.597 | 12 | 0.1 | 71.9 | 45 | 1068 | 0.01016 | 0.000018 | 0.1413
8 x BLACHA | +10.092 | +10.096 | 12 | 0.1 | 71.9 | 45 | 1068 | 0.01016 | 0.000018 | 0.1413
8 x BLACHA | +5.772 | +5.776 | 12 | 0.1 | 71.9 | 45 | 1068 | 0.01016 | 0.000018 | 0.1413
8 x BLACHA | +1.452 | +1.456 | 12 | 0.1 | 71.9 | 45 | 1068 | 0.01016 | 0.000018 | 0.1413

# IfcColumn: HEA120, SŁUP
In: Undefined
Description: HEA120; Material: STEEL/S355JR
Tekla Common - Bottom elevation: +19.944; Top elevation: +20.064; Phase: 5; Class: 9
Tekla Quantity - Weight: 75.6 kg; Volume: 0 m3; Gross footprint area: 0 m2; Area per tons: 33.6 m2; Net surface area: 2.7 m2; Height: 114 mm; Width: 120 mm; Length: 3808.6 mm
Pset_ColumnCommon - LoadBearing: yes; Reference: 1007
BaseQuantities - Length: 3808.58 mm; OuterSurfaceArea: 2.54032 m2; NetVolume: 0.00917867 m3; NetWeight: 72.0525 kg

# IfcColumn: HEA140 (5)
In: Undefined
Description: HEA140; Material: STEEL/S355JR
Tekla Common - Phase: 5; Class: 4
Tekla Quantity - Weight: 93.9 kg; Volume: 0 m3; Gross footprint area: 0 m2; Area per tons: 32.2 m2; Net surface area: 3.1 m2; Height: 133 mm; Width: 140 mm; Length: 3807.5 mm
Pset_ColumnCommon - LoadBearing: yes
BaseQuantities - Length: 3807.47 mm; OuterSurfaceArea: 3.02313 m2; NetVolume: 0.011491 m3; NetWeight: 90.204 kg
Name | Bottom elevation | Top elevation | Reference
SŁUP | +1.294 | +1.434 | 1002(?)
SŁUP | +5.614 | +5.754 | 1002
SŁUP | +9.934 | +10.074 | 1002
SŁUP | +14.254 | +14.394 | 1002
SŁUP | +18.574 | +18.714 | 1002

# IfcColumn: IPE180 (2)
In: Undefined
Description: IPE180; Material: STEEL/S355JR
Tekla Common - Bottom elevation: +19.959; Top elevation: +20.050; Phase: 2; Class: 9
Tekla Quantity - Weight: 82.6 kg; Volume: 0 m3; Gross footprint area: 0 m2; Area per tons: 37.2 m2; Net surface area: 3.1 m2; Height: 180 mm; Width: 91 mm; Length: 4403.2 mm
Pset_ColumnCommon - LoadBearing: yes; Reference: 1006
BaseQuantities - Length: 4403.17 mm; OuterSurfaceArea: 3.07341 m2; NetVolume: 0.0102185 m3; NetWeight: 80.2153 kg

# IfcColumn: IPE270 (10)
In: Undefined
Description: IPE270; Material: STEEL/S355JR
Tekla Common - Phase: 2; Class: 4
Tekla Quantity - Weight: 158.4 kg; Volume: 0 m3; Gross footprint area: 0 m2; Area per tons: 29 m2; Net surface area: 4.7 m2; Height: 270 mm; Width: 135 mm; Length: 4397.2 mm
Pset_ColumnCommon - LoadBearing: yes
BaseQuantities - Length: 4397.16 mm; OuterSurfaceArea: 4.57745 m2; NetVolume: 0.0192974 m3; NetWeight: 151.485 kg
Name | Bottom elevation | Top elevation | Reference
2 x SŁUP | +1.297 | +1.432 | 1001(?)
2 x SŁUP | +5.617 | +5.752 | 1001
2 x SŁUP | +9.937 | +10.072 | 1001
2 x SŁUP | +14.257 | +14.392 | 1001
2 x SŁUP | +18.577 | +18.712 | 1001

# IfcColumn: SHS100*3 (3)
In: Undefined
Description: SHS100*3; Material: STEEL/S355JR
Tekla Common - Bottom elevation: +20.104; Top elevation: +20.204
Tekla Quantity - Volume: 0 m3; Gross footprint area: 0 m2; Height: 100 mm; Width: 100 mm
Pset_ColumnCommon - LoadBearing: yes
Name | Phase | Class | Weight (kg) | Area per tons (m2) | Net surface area (m2) | Tekla Quantity, Length (mm) = BaseQuantities, Length (mm) | Reference | OuterSurfaceArea (m2) | NetVolume (m3) | NetWeight (kg)
SŁUPEK | 5 | 5 | 11.8 | 44 | 0.5 | 1290 | 1120 | 0.5172 | 0.00150156 | 11.7872
2 x SŁUP | 4 | 9 | 45 | 43.8 | 2 | 4924 | 1005 | 1.9708 | 0.00573154 | 44.9926

# IfcElementAssembly (274)
In: Undefined
Name | PredefinedType | Assembly/Cast unit weight (kg) | Assembly/Cast unit bottom elevation | Assembly/Cast unit top elevation | Assembly/Cast unit position code | Assembly/Cast unit Mark | Width (mm)
BELKA | REINFORCEMENT_UNIT | 475.6 | -0.196 | -0.016 | A-C/1 | B0(?) | 180 | Tekla Assembly - Cast unit type: Wylewany na miejscu; Cast unit rebar weight: 0 kg
BELKA | RIGID_FRAME | 34.9 | -0.015 | +0.065 | A-B/1 | B0(?) | 80
BELKA | RIGID_FRAME | 36.2 | -0.015 | +0.065 | B-C/1 | B0(?) | 80
BELKA | REINFORCEMENT_UNIT | 475.6 | -0.196 | -0.016 | C-E/1 | B0(?) | 180 | Tekla Assembly - Cast unit type: Wylewany na miejscu; Cast unit rebar weight: 0 kg
BELKA | RIGID_FRAME | 36.1 | -0.015 | +0.065 | C-D/1 | B0(?) | 80
2 x BELKA | RIGID_FRAME | 6.1 | -0.016 | +0.000 | E/1 | B0(?) | 16
BELKA | REINFORCEMENT_UNIT | 989.1 | -0.196 | -0.016 | A-E/1 | B0(?) | 180 | Tekla Assembly - Cast unit type: Wylewany na miejscu; Cast unit rebar weight: 0 kg
BELKA | REINFORCEMENT_UNIT | 27118 | -0.196 | -0.016 | A-E/1 | B0(?) | 4935 | Tekla Assembly - Cast unit type: Wylewany na miejscu; Cast unit rebar weight: 0 kg
SŁUP | REINFORCEMENT_UNIT | 427.7 | -0.196 | -0.016 | A/1 | SL0(?) | 200 | Tekla Assembly - Cast unit type: Wylewany na miejscu; Cast unit rebar weight: 0 kg
BELKA | RIGID_FRAME | 6 | -0.016 | +0.000 | A/1 | B0(?) | 16
2 x BELKA | RIGID_FRAME | 5.5 | -0.016 | +0.000 | A/1 | B0(?) | 16
RYGIEL | RIGID_FRAME | 13.4 | +0.013 | +1.352 | A/1-2 | RR1(?) | 132
BLACHA | RIGID_FRAME | 0.4 | +0.000 | +0.058 | A/1 | L0(?) | 8
BELKA | RIGID_FRAME | 7.5 | -0.016 | +0.000 | A/1 | B0(?) | 16
BELKA | RIGID_FRAME | 8.5 | -0.016 | +0.000 | A/1 | B0(?) | 16
STĘŻENIE | RIGID_FRAME | 4.9 | +0.034 | +1.303 | A/1-2 | X1(?) | 16
STĘŻENIE | RIGID_FRAME | 4.9 | +0.034 | +1.317 | A/1-2 | X0(?) | 16
STĘŻENIE | RIGID_FRAME | 4.9 | +0.058 | +1.327 | A/1-2 | X0(?) | 16
STĘŻENIE | RIGID_FRAME | 4.9 | +0.024 | +1.327 | A/1-2 | X2(?) | 16
BLACHA | RIGID_FRAME | 2.6 | -0.000 | +0.130 | C/1 | L0(?) | 10
STĘŻENIE | RIGID_FRAME | 4.5 | +0.058 | +1.323 | C/1-2 | X0(?) | 16
SŁUP | REINFORCEMENT_UNIT | 513.2 | -0.196 | -0.016 | C/1 | SL0(?) | 240 | Tekla Assembly - Cast unit type: Wylewany na miejscu; Cast unit rebar weight: 0 kg
BELKA | RIGID_FRAME | 7.5 | -0.016 | +0.000 | C/1 | B0(?) | 16
BLACHA | RIGID_FRAME | 0.4 | +0.059 | +0.129 | C/1 | L0(?) | 10
2 x BLACHA | RIGID_FRAME | 2.3 | -0.196 | -0.056 | C/1 | L0(?) | 140
2 x BLACHA | RIGID_FRAME | 2 | -0.192 | -0.056 | C/1 | L0(?) | 136
STĘŻENIE | RIGID_FRAME | 4.9 | +0.034 | +1.325 | E/1-2 | X0(?) | 16
BLACHA | RIGID_FRAME | 2 | +1.261 | +1.361 | E/2 | L0(?) | 10
BLACHA | RIGID_FRAME | 7.7 | +0.030 | +1.311 | E/1 | L0(?) | 1281.05
STĘŻENIE | RIGID_FRAME | 4.9 | +0.034 | +1.303 | E/1-2 | X1(?) | 16
TĘŻNIK | RIGID_FRAME | 7.7 | +0.070 | +1.291 | E/1-2 | T2(?) | 60
BLACHA | RIGID_FRAME | 3.4 | -0.000 | +0.120 | E/1 | L0(?) | 12
SŁUP | RIGID_FRAME | 107.2 | +1.215 | +1.477 | C/2 | S11(?) | 262.492
STĘŻENIE | RIGID_FRAME | 4.5 | +0.039 | +1.310 | C/1-2 | X0(?) | 16
BELKA | RIGID_FRAME | 9.4 | -0.016 | +0.000 | C/1 | B0(?) | 16
BLACHA | RIGID_FRAME | 0.9 | +0.059 | +0.210 | C/1 | L0(?) | 12
BLACHA | RIGID_FRAME | 2.1 | +0.000 | +0.147 | C/1 | L0(?) | 10
STĘŻENIE | RIGID_FRAME | 3.8 | +0.124 | +1.327 | C/1-2 | X10(?) | 16
BELKA | RIGID_FRAME | 6 | -0.016 | +0.000 | C/1 | B0(?) | 16
SŁUP | REINFORCEMENT_UNIT | 515.3 | -0.196 | +0.135 | E/1 | SL0(?) | 240 | Tekla Assembly - Cast unit type: Wylewany na miejscu; Cast unit rebar weight: 0 kg
BELKA | RIGID_FRAME | 6 | -0.016 | +0.000 | E/1 | B0(?) | 16
TĘŻNIK | RIGID_FRAME | 7.7 | +0.040 | +1.311 | B/1-2 | T0(?) | 80
SŁUP | REINFORCEMENT_UNIT | 513.2 | -0.196 | -0.016 | B/1 | SL0(?) | 240 | Tekla Assembly - Cast unit type: Wylewany na miejscu; Cast unit rebar weight: 0 kg
BLACHA | RIGID_FRAME | 1.1 | +0.010 | +0.090 | B/1 | L0(?) | 10
BELKA | RIGID_FRAME | 5.5 | -0.016 | +0.000 | B/1 | B0(?) | 16
TĘŻNIK | RIGID_FRAME | 7.7 | +0.040 | +1.311 | D/1-2 | T0(?) | 80
BLACHA | RIGID_FRAME | 1.1 | +0.010 | +0.090 | D/1 | L0(?) | 10
SŁUP | REINFORCEMENT_UNIT | 513.2 | -0.196 | -0.016 | D/1 | SL0(?) | 240 | Tekla Assembly - Cast unit type: Wylewany na miejscu; Cast unit rebar weight: 0 kg
BELKA | RIGID_FRAME | 5.5 | -0.016 | +0.000 | D/1 | B0(?) | 16
BELKA | RIGID_FRAME | 7.5 | -0.016 | +0.000 | E/1 | B0(?) | 16
STĘŻENIE | RIGID_FRAME | 4.9 | +0.047 | +1.327 | E/1-2 | X1(?) | 16
STĘŻENIE | RIGID_FRAME | 4.9 | +0.024 | +1.327 | E/1-2 | X0(?) | 16
BELKA | RIGID_FRAME | 8.5 | -0.016 | +0.000 | E/1 | B0(?) | 16
BELKA | RIGID_FRAME | 34.7 | -0.016 | +0.064 | D-E/1 | B0(?) | 80
SŁUP | RIGID_FRAME | 110.1 | +19.856 | +20.204 | E/7 | S19 | 348.474
SŁUP | RIGID_FRAME | 110.5 | +19.856 | +20.204 | A/7 | S7 | 348.474
STĘŻENIE | RIGID_FRAME | 4.5 | +18.698 | +19.963 | C/6-7 | X9 | 16
STĘŻENIE | RIGID_FRAME | 4.3 | +18.686 | +19.935 | C/6-7 | X10 | 16
TĘŻNIK | RIGID_FRAME | 7.5 | +18.707 | +19.942 | C/6-7 | T7 | 80
SŁUP | RIGID_FRAME | 110 | +19.855 | +20.204 | C/7 | S16(?) | 349.492
RYGIEL | RIGID_FRAME | 25.7 | +14.412 | +17.124 | D-E/5-6 | RR20 | 100
RYGIEL | RIGID_FRAME | 10.4 | +14.292 | +14.462 | D-E/5 | RR21 | 170
RYGIEL | RIGID_FRAME | 12 | +17.074 | +17.244 | D-E/5-6 | RR22 | 170
SŁUP | RIGID_FRAME | 187.2 | +14.184 | +14.478 | E/5 | S23(?) | 293.3
STĘŻENIE | RIGID_FRAME | 4.9 | +18.682 | +19.977 | A/6-7 | X2 | 16
STĘŻENIE | RIGID_FRAME | 4.9 | +18.692 | +19.968 | A/6-7 | X3 | 16
SŁUP | RIGID_FRAME | 198.4 | +1.215 | +1.518 | A/2 | S1(?) | 302.489
STĘŻENIE | RIGID_FRAME | 8.9 | +1.417 | +5.581 | D-E/2-3 | X13 | 56.7086
STĘŻENIE | RIGID_FRAME | 4.9 | +18.682 | +19.977 | E/6-7 | X2 | 16
STĘŻENIE | RIGID_FRAME | 4.9 | +18.692 | +19.968 | E/6-7 | X3 | 16
SŁUPEK | RIGID_FRAME | 13.4 | +20.124 | +20.204 | C/7 | SR1 | 80
RYGIEL | RIGID_FRAME | 29.5 | +20.104 | +20.204 | C-D/7 | RR14 | 100
RYGIEL | RIGID_FRAME | 29.5 | +20.104 | +20.204 | C-D/7 | RR15 | 100
SŁUP | RIGID_FRAME | 54.1 | +20.008 | +20.204 | B/7 | S9 | 196.35
RYGIEL | RIGID_FRAME | 125.4 | +19.901 | +20.059 | A-C/7 | R2 | 157.95
SŁUP | RIGID_FRAME | 54.1 | +20.008 | +20.204 | D/7 | S9 | 196.35
STĘŻENIE | RIGID_FRAME | 4.7 | +0.034 | +1.303 | C/1-2 | X8(?) | 16
TĘŻNIK | RIGID_FRAME | 8 | +0.080 | +1.282 | C/1-2 | T9(?) | 60
BLACHA | RIGID_FRAME | 3.3 | -0.000 | +0.130 | C/1 | L0(?) | 12
STĘŻENIE | RIGID_FRAME | 4.7 | +18.706 | +19.968 | C/6-7 | X8 | 16
TĘŻNIK | RIGID_FRAME | 8.5 | +18.727 | +19.922 | C/6-7 | T9 | 60
STĘŻENIE | RIGID_FRAME | 4.7 | +18.681 | +19.943 | C/6-7 | X8 | 16
SŁUP | RIGID_FRAME | 107.2 | +18.532 | +18.794 | C/6 | S15(?) | 262.492
STĘŻENIE | RIGID_FRAME | 4.9 | +18.706 | +19.968 | E/6-7 | X1 | 16
TĘŻNIK | RIGID_FRAME | 8.7 | +18.718 | +19.931 | E/6-7 | T2 | 60
STĘŻENIE | RIGID_FRAME | 4.9 | +18.682 | +19.944 | E/6-7 | X1 | 16
SŁUP | RIGID_FRAME | 190.5 | +18.491 | +18.793 | E/6 | S24 | 302.424
STĘŻENIE | RIGID_FRAME | 4.9 | +18.706 | +19.968 | A/6-7 | X1 | 16
TĘŻNIK | RIGID_FRAME | 8.7 | +18.718 | +19.931 | A/6-7 | T2 | 60
STĘŻENIE | RIGID_FRAME | 4.9 | +18.682 | +19.944 | A/6-7 | X1 | 16
SŁUP | RIGID_FRAME | 191.5 | +18.491 | +18.793 | A/6 | S5 | 302.424
SŁUP | RIGID_FRAME | 189.9 | +1.215 | +1.518 | E/2 | S0(?) | 302.489
TĘŻNIK | RIGID_FRAME | 8 | +0.070 | +1.290 | A/1-2 | T2(?) | 60
BLACHA | RIGID_FRAME | 3.4 | +0.000 | +0.120 | A/1 | L0(?) | 12
BLACHA | RIGID_FRAME | 2 | +0.000 | +0.146 | A/1 | L0(?) | 10
RYGIEL | RIGID_FRAME | 13.6 | +18.657 | +19.999 | E/6-7 | RR7 | 130
RYGIEL | RIGID_FRAME | 13.6 | +18.657 | +19.999 | A/6-7 | RR7 | 130
RYGIEL | RIGID_FRAME | 13.4 | +0.013 | +1.352 | E/1-2 | RR7(?) | 130
BLACHA | RIGID_FRAME | 0.4 | +0.000 | +0.058 | E/1 | L0(?) | 8
STĘŻENIE | RIGID_FRAME | 8.9 | +14.428 | +18.591 | A-B/5-6 | X5 | 56.7086
STĘŻENIE | RIGID_FRAME | 8.9 | +14.377 | +18.541 | A-B/5-6 | X4 | 56.7091
SŁUP | RIGID_FRAME | 192.3 | +14.204 | +14.478 | A/5 | S4 | 273.3
STĘŻENIE | RIGID_FRAME | 8.9 | +14.426 | +18.612 | B-C/5-6 | X7 | 56.7071
RYGIEL | RIGID_FRAME | 249.4 | +18.456 | +18.748 | A-C/6 | R7 | 291.913
STĘŻENIE | RIGID_FRAME | 8.9 | +14.356 | +18.542 | B-C/5-6 | X6 | 56.7073
RYGIEL | RIGID_FRAME | 249.4 | +14.221 | +14.513 | A-C/5 | R6 | 291.911
STĘŻENIE | RIGID_FRAME | 8.9 | +14.428 | +18.591 | D-E/5-6 | X4 | 56.7091
STĘŻENIE | RIGID_FRAME | 8.9 | +14.377 | +18.541 | D-E/5-6 | X5 | 56.7086
STĘŻENIE | RIGID_FRAME | 8.9 | +14.426 | +18.612 | C-D/5-6 | X11 | 56.7066
RYGIEL | RIGID_FRAME | 251.2 | +18.456 | +18.748 | C-E/6 | R12 | 291.911
STĘŻENIE | RIGID_FRAME | 8.9 | +14.356 | +18.542 | C-D/5-6 | X12 | 56.7069
RYGIEL | RIGID_FRAME | 251.2 | +14.221 | +14.513 | C-E/5 | R11 | 291.913
TĘŻNIK | RIGID_FRAME | 23.9 | +14.463 | +18.506 | B/5-6 | T5 | 90.0002
TĘŻNIK | RIGID_FRAME | 23.9 | +14.463 | +18.506 | D/5-6 | T5 | 90.0002
TĘŻNIK | RIGID_FRAME | 23.3 | +14.387 | +18.582 | C/5-6 | T8 | 80
SŁUP | RIGID_FRAME | 102.2 | +14.212 | +14.437 | C/5 | S14(?) | 225.5
STĘŻENIE | RIGID_FRAME | 8.9 | +1.417 | +5.581 | A-B/2-3 | X4 | 56.7091
STĘŻENIE | RIGID_FRAME | 8.9 | +1.468 | +5.631 | A-B/2-3 | X5 | 56.7086
SŁUP | RIGID_FRAME | 192.3 | +5.531 | +5.824 | A/3 | S2 | 293.3
STĘŻENIE | RIGID_FRAME | 8.9 | +1.468 | +5.631 | D-E/2-3 | X4 | 56.7091
SŁUP | RIGID_FRAME | 187.2 | +5.531 | +5.804 | E/3 | S21 | 273.3
STĘŻENIE | RIGID_FRAME | 8.9 | +1.396 | +5.582 | B-C/2-3 | X6 | 56.7073
RYGIEL | RIGID_FRAME | 249.4 | +1.261 | +1.553 | A-C/2 | R3 | 291.911
STĘŻENIE | RIGID_FRAME | 8.9 | +1.466 | +5.652 | B-C/2-3 | X7 | 56.7071
RYGIEL | RIGID_FRAME | 249.4 | +5.496 | +5.788 | A-C/3 | R4 | 291.913
TĘŻNIK | RIGID_FRAME | 23.3 | +1.427 | +5.622 | C/2-3 | T8 | 80
SŁUP | RIGID_FRAME | 102.2 | +5.572 | +5.797 | C/3 | S12(?) | 225.5
STĘŻENIE | RIGID_FRAME | 8.9 | +1.466 | +5.652 | C-D/2-3 | X11 | 56.7066
RYGIEL | RIGID_FRAME | 249.4 | +5.496 | +5.788 | C-E/3 | R9 | 291.911
STĘŻENIE | RIGID_FRAME | 8.9 | +1.396 | +5.582 | C-D/2-3 | X12 | 56.7069
RYGIEL | RIGID_FRAME | 249.4 | +1.261 | +1.553 | C-E/2 | R8 | 291.913
KĄTOWNIK | RIGID_FRAME | 44.5 | +20.124 | +20.204 | B-D/7 | K6 | 80
KĄTOWNIK | RIGID_FRAME | 22.9 | +20.069 | +20.204 | A-B/7 | K4 | 135
KĄTOWNIK | RIGID_FRAME | 22.9 | +20.069 | +20.204 | E/7 | K13 | 80
TĘŻNIK | RIGID_FRAME | 22.9 | +14.428 | +18.541 | E/5-6 | T3 | 80
TĘŻNIK | RIGID_FRAME | 22.9 | +14.428 | +18.541 | A/5-6 | T3 | 80
TĘŻNIK | RIGID_FRAME | 22.9 | +1.468 | +5.581 | A/2-3 | T3 | 80
TĘŻNIK | RIGID_FRAME | 22.9 | +1.468 | +5.581 | E/2-3 | T3 | 80
TĘŻNIK | RIGID_FRAME | 7.1 | +0.130 | +1.302 | C/1-2 | T7(?) | 80
BLACHA | RIGID_FRAME | 1.6 | +0.000 | +0.080 | E/1 | L0(?) | 10
TĘŻNIK | RIGID_FRAME | 7.7 | +0.030 | +1.311 | A/1-2 | T1(?) | 80
BLACHA | RIGID_FRAME | 1.6 | +0.000 | +0.080 | A/1 | L0(?) | 10
TĘŻNIK | RIGID_FRAME | 7.7 | +18.698 | +19.972 | A/6-7 | T1 | 80
TĘŻNIK | RIGID_FRAME | 7.7 | +18.698 | +19.972 | E/6-7 | T1 | 80
TĘŻNIK | RIGID_FRAME | 7.5 | +18.698 | +19.951 | B/6-7 | T6 | 80
TĘŻNIK | RIGID_FRAME | 7.7 | +18.698 | +19.971 | D/6-7 | T1 | 80
RYGIEL | RIGID_FRAME | 125.2 | +19.921 | +20.059 | C-E/7 | R14 | 137.95
RYGIEL ATTYKOWY | RIGID_FRAME | 28.6 | +20.104 | +20.204 | B-C/7 | RA4 | 100
RYGIEL ATTYKOWY | RIGID_FRAME | 28.6 | +20.104 | +20.204 | C-D/7 | RA4 | 100
SŁUPEK | RIGID_FRAME | 13.4 | +20.124 | +20.204 | A-B/7 | SR1 | 80
RYGIEL | RIGID_FRAME | 28.6 | +20.104 | +20.204 | A-B/7 | RR9 | 100
RYGIEL | RIGID_FRAME | 28.6 | +20.104 | +20.204 | A-B/7 | RR10 | 100
SŁUPEK | RIGID_FRAME | 13.4 | +20.124 | +20.204 | B-C/7 | SR1 | 80
RYGIEL | RIGID_FRAME | 29.1 | +20.104 | +20.204 | B-C/7 | RR12 | 100
RYGIEL | RIGID_FRAME | 29.1 | +20.104 | +20.204 | B-C/7 | RR13 | 100
SŁUPEK | RIGID_FRAME | 13.4 | +20.124 | +20.204 | C-D/7 | SR1 | 80
SŁUPEK | RIGID_FRAME | 13.4 | +20.124 | +20.204 | D-E/7 | SR1 | 80
RYGIEL | RIGID_FRAME | 28.6 | +20.104 | +20.204 | D-E/7 | RR16 | 100
RYGIEL | RIGID_FRAME | 28.6 | +20.104 | +20.204 | D-E/7 | RR17 | 100
SŁUPEK | RIGID_FRAME | 13.4 | +4.459 | +4.539 | E/2-3 | SR1 | 80
RYGIEL | RIGID_FRAME | 42.2 | +1.382 | +5.672 | E/2-3 | RR23 | 130
RYGIEL | RIGID_FRAME | 42.2 | +1.382 | +5.672 | E/2-3 | RR24 | 130
SŁUPEK | RIGID_FRAME | 13.4 | +3.319 | +3.399 | E/2-3 | SR1 | 80
SŁUPEK | RIGID_FRAME | 13.4 | +3.039 | +3.119 | E/2-3 | SR1 | 80
SŁUPEK | RIGID_FRAME | 13.4 | +1.659 | +1.739 | E/2 | SR1 | 80
SŁUPEK | RIGID_FRAME | 13.4 | +9.630 | +9.710 | E/4 | SR1 | 80
RYGIEL | RIGID_FRAME | 41.4 | +5.702 | +9.992 | E/3-4 | RR25 | 130
RYGIEL | RIGID_FRAME | 41.4 | +5.702 | +9.992 | E/3-4 | RR26 | 130
SŁUPEK | RIGID_FRAME | 13.4 | +8.250 | +8.330 | E/3-4 | SR1 | 80
SŁUPEK | RIGID_FRAME | 13.4 | +11.372 | +11.452 | E/4-5 | SR1 | 80
RYGIEL | RIGID_FRAME | 40.9 | +10.022 | +14.312 | E/4-5 | RR27 | 130
RYGIEL | RIGID_FRAME | 40.9 | +10.022 | +14.312 | E/4-5 | RR28 | 130
SŁUP | RIGID_FRAME | 190.7 | +9.864 | +10.124 | E/4 | S22 | 260
SŁUPEK | RIGID_FRAME | 13.4 | +7.114 | +7.194 | A/3-4 | SR1 | 80
RYGIEL | RIGID_FRAME | 41.4 | +5.697 | +9.987 | A/3-4 | RR4 | 130
RYGIEL | RIGID_FRAME | 41.4 | +5.697 | +9.987 | A/3-4 | RR5 | 130
SŁUPEK | RIGID_FRAME | 13.4 | +8.494 | +8.574 | A/3-4 | SR1 | 80
SŁUPEK | RIGID_FRAME | 13.4 | +15.754 | +15.834 | A/5-6 | SR1 | 80
RYGIEL | RIGID_FRAME | 41.4 | +14.337 | +18.627 | A/5-6 | RR6 | 130
RYGIEL | RIGID_FRAME | 41.4 | +14.337 | +18.627 | A/5-6 | RR5 | 130
SŁUPEK | RIGID_FRAME | 13.4 | +17.134 | +17.214 | A/5-6 | SR1 | 80
SŁUPEK | RIGID_FRAME | 13.4 | +2.732 | +2.812 | A/2-3 | SR1 | 80
RYGIEL | RIGID_FRAME | 41.4 | +1.377 | +5.667 | A/2-3 | RR2 | 130
RYGIEL | RIGID_FRAME | 41.4 | +1.377 | +5.667 | A/2-3 | RR3 | 130
SŁUPEK | RIGID_FRAME | 13.4 | +4.237 | +4.317 | A/2-3 | SR1 | 80
SŁUPEK | RIGID_FRAME | 13.4 | +11.372 | +11.452 | A/4-5 | SR1 | 80
RYGIEL | RIGID_FRAME | 41.4 | +10.017 | +14.307 | A/4-5 | RR2 | 130
RYGIEL | RIGID_FRAME | 41.4 | +10.017 | +14.307 | A/4-5 | RR3 | 130
SŁUPEK | RIGID_FRAME | 13.4 | +12.877 | +12.957 | A/4-5 | SR1 | 80
SŁUP | RIGID_FRAME | 190.7 | +9.884 | +10.144 | A/4 | S3 | 260
KĄTOWNIK | RIGID_FRAME | 6.9 | +16.184 | +17.134 | D-E/5-6 | K8 | 80
KĄTOWNIK | RIGID_FRAME | 1.8 | +14.402 | +14.645 | D-E/5 | K7 | 80
KĄTOWNIK | RIGID_FRAME | 7.3 | +14.312 | +14.392 | D-E/5 | K9 | 80
KĄTOWNIK | RIGID_FRAME | 8.5 | +17.144 | +17.224 | D-E/5-6 | K10 | 80
KĄTOWNIK | RIGID_FRAME | 8.9 | +17.314 | +18.554 | E/5-6 | K12 | 80
KĄTOWNIK | RIGID_FRAME | 8.7 | +0.069 | +1.274 | A/1-2 | K2 | 80
KĄTOWNIK | RIGID_FRAME | 8.7 | +0.069 | +1.274 | E/1-2 | K2 | 80
KĄTOWNIK | RIGID_FRAME | 8.7 | +18.734 | +19.939 | E/6-7 | K2 | 80
KĄTOWNIK | RIGID_FRAME | 8.7 | +18.734 | +19.939 | A/6-7 | K2 | 80
KĄTOWNIK | RIGID_FRAME | 30 | +14.414 | +18.554 | A/5-6 | K3 | 80
KĄTOWNIK | RIGID_FRAME | 30 | +10.094 | +14.234 | A/4-5 | K3 | 80
KĄTOWNIK | RIGID_FRAME | 30 | +5.774 | +9.914 | A/3-4 | K3 | 80
KĄTOWNIK | RIGID_FRAME | 30 | +1.454 | +5.594 | A/2-3 | K3 | 80
KĄTOWNIK | RIGID_FRAME | 30 | +10.094 | +14.234 | E/4-5 | K3 | 80
KĄTOWNIK | RIGID_FRAME | 30 | +1.454 | +5.594 | E/2-3 | K3 | 80
KĄTOWNIK | RIGID_FRAME | 30 | +5.764 | +9.904 | E/3-4 | K3 | 80
SŁUPEK | RIGID_FRAME | 41.4 | +14.242 | +14.462 | D-E/5 | SR2(?) | 220
SŁUPEK | RIGID_FRAME | 39.9 | +17.074 | +17.294 | D-E/5-6 | SR5 | 220
RYGIEL | RIGID_FRAME | 40.5 | +14.378 | +18.591 | D-E/5-6 | RR19 | 120
SŁUPEK | RIGID_FRAME | 27.8 | +14.654 | +14.814 | D-E/5 | SR3 | 160
RYGIEL | RIGID_FRAME | 26.8 | +14.412 | +17.124 | D-E/5-6 | RR18 | 100
SŁUPEK | RIGID_FRAME | 27.8 | +16.014 | +16.174 | D-E/5-6 | SR4 | 160
SŁUPEK | RIGID_FRAME | 29.2 | +17.144 | +17.304 | E/5-6 | SR6 | 160
RYGIEL | RIGID_FRAME | 41.6 | +14.342 | +18.632 | E/5-6 | RR29 | 170
GROUT |  | 0 | +14.222 | +14.412 | D-E/5 | L6 | 20
GROUT |  | 0 | +14.224 | +14.412 | E/5 | L8 | 20
GROUT |  | 0 | +14.634 | +14.834 | D-E/5-6 | L7 | 20
GROUT |  | 0 | +15.994 | +16.194 | D-E/5-6 | L7 | 20
GROUT |  | 0 | +17.124 | +17.314 | D-E/5-6 | L6 | 20
GROUT |  | 0 | +17.124 | +17.324 | E/5-6 | L7 | 20
TĘŻNIK | RIGID_FRAME | 23.9 | +1.503 | +5.546 | B/2-3 | T5 | 90.0002
TĘŻNIK | RIGID_FRAME | 23.9 | +1.503 | +5.546 | D/2-3 | T5 | 90.0002
TĘŻNIK | RIGID_FRAME | 23.3 | +5.747 | +9.942 | C/3-4 | T8 | 80
TĘŻNIK | RIGID_FRAME | 23.3 | +10.067 | +14.262 | C/4-5 | T8 | 80
SŁUP | RIGID_FRAME | 102.2 | +9.892 | +10.117 | C/4 | S13(?) | 225.5
TĘŻNIK | RIGID_FRAME | 23.4 | +5.738 | +9.951 | D/3-4 | T4 | 80
RYGIEL | RIGID_FRAME | 245.6 | +9.901 | +10.108 | C-E/4 | R10 | 207.2
TĘŻNIK | RIGID_FRAME | 23.4 | +10.058 | +14.271 | D/4-5 | T4 | 80
TĘŻNIK | RIGID_FRAME | 23.4 | +5.738 | +9.951 | B/3-4 | T4 | 80
TĘŻNIK | RIGID_FRAME | 23.4 | +10.058 | +14.271 | B/4-5 | T4 | 80
RYGIEL | RIGID_FRAME | 245.6 | +9.901 | +10.108 | A-C/4 | R5 | 207.2
TĘŻNIK | RIGID_FRAME | 23.4 | +10.058 | +14.271 | E/4-5 | T4 | 80
TĘŻNIK | RIGID_FRAME | 23.4 | +5.738 | +9.951 | E/3-4 | T4 | 80
TĘŻNIK | RIGID_FRAME | 23.4 | +10.058 | +14.271 | A/4-5 | T4 | 80
TĘŻNIK | RIGID_FRAME | 23.4 | +5.738 | +9.951 | A/3-4 | T4 | 80
RYGIEL ATTYKOWY | RIGID_FRAME | 28.2 | +20.104 | +20.204 | D-E/7 | RA3 | 100
RYGIEL ATTYKOWY | RIGID_FRAME | 28.2 | +20.104 | +20.204 | A-B/7 | RA3 | 100
RYGIEL ATTYKOWY | RIGID_FRAME | 12.5 | +0.020 | +1.294 | E/1-2 | RA1(?) | 100
BLACHA | RIGID_FRAME | 0.4 | +0.000 | +0.070 | E/1 | L0(?) | 10
RYGIEL ATTYKOWY | RIGID_FRAME | 39.1 | +1.434 | +5.614 | E/2-3 | RA2 | 100
RYGIEL ATTYKOWY | RIGID_FRAME | 39.1 | +5.754 | +9.934 | E/3-4 | RA2 | 100
RYGIEL ATTYKOWY | RIGID_FRAME | 39.1 | +10.074 | +14.254 | E/4-5 | RA2 | 100
RYGIEL ATTYKOWY | RIGID_FRAME | 39.1 | +14.394 | +18.574 | E/5-6 | RA2 | 100
RYGIEL ATTYKOWY | RIGID_FRAME | 12 | +18.714 | +19.934 | E/6-7 | RA1 | 100
RYGIEL ATTYKOWY | RIGID_FRAME | 12 | +18.714 | +19.934 | A/6-7 | RA1 | 100
RYGIEL ATTYKOWY | RIGID_FRAME | 39.1 | +14.394 | +18.574 | A/5-6 | RA2 | 100
RYGIEL ATTYKOWY | RIGID_FRAME | 13.2 | -0.001 | +1.294 | A/1-2 | RA0(?) | 100
RYGIEL ATTYKOWY | RIGID_FRAME | 39.1 | +1.434 | +5.614 | A/2-3 | RA2 | 100
RYGIEL ATTYKOWY | RIGID_FRAME | 39.1 | +5.754 | +9.934 | A/3-4 | RA2 | 100
RYGIEL ATTYKOWY | RIGID_FRAME | 39.1 | +10.074 | +14.254 | A/4-5 | RA2 | 100
GROUT |  | 0 | +20.019 | +20.224 | B/7 | L3 | 20
GROUT |  | 0 | +20.019 | +20.224 | D/7 | L3 | 20
GROUT |  | 0 | +1.264 | +1.464 | C/2 | L5 | 20
GROUT |  | 0 | +19.904 | +20.104 | C/7 | L4 | 20
GROUT |  | 0 | +18.544 | +18.744 | C/6 | L5 | 20
GROUT |  | 0 | +5.584 | +5.784 | C/3 | L5 | 20
GROUT |  | 0 | +9.904 | +10.104 | C/4 | L5 | 20
GROUT |  | 0 | +14.224 | +14.424 | C/5 | L5 | 20
GROUT |  | 0 | +19.929 | +20.079 | E/7 | L1 | 20
GROUT |  | 0 | +1.264 | +1.464 | A/2 | L2 | 20
GROUT |  | 0 | +5.584 | +5.784 | A/3 | L2 | 20
GROUT |  | 0 | +9.904 | +10.104 | A/4 | L2 | 20
GROUT |  | 0 | +14.224 | +14.424 | A/5 | L2 | 20
GROUT |  | 0 | +18.544 | +18.744 | A/6 | L2 | 20
GROUT |  | 0 | +19.929 | +20.079 | A/7 | L1 | 20
GROUT |  | 0 | +1.264 | +1.464 | E/2 | L2 | 20
GROUT |  | 0 | +5.584 | +5.784 | E/3 | L2 | 20
GROUT |  | 0 | +9.904 | +10.104 | E/4 | L2 | 20
GROUT |  | 0 | +18.544 | +18.744 | E/6 | L2 | 20
PŁYTA | REINFORCEMENT_UNIT | 154841 | -0.226 | +20.234 | A-E/1-7 | P1 | 250 | Tekla Assembly - Cast unit type: Wylewany na miejscu; Cast unit rebar weight: 0 kg

# IfcMechanicalFastener: Bolt assembly (397)
In: Undefined
Material: Undefined
Tekla Bolt - Location: Budowa
Name | NominalDiameter (mm) = Washer diameter (mm) | NominalLength (mm) = Bolt length (mm) | Washer count | Washer type | Washer name | Nut count | Nut type | Nut name | Slotted hole y (mm) | Slotted hole x (mm) | Bolt hole diameter (mm) | Bolt count | Bolt size (mm) | Bolt standard | Bolt Name
4 x Bolt assembly | 12 | 100 | 10 | 125A | PODKLADKA-12-125A | 10 | 934 | NAKRETKA-M12-934 | 0 | 0 | 14 | 10 | 12 | 931 | SRUBA
Bolt assembly | 12 | 35 | 3 | 125A | PODKLADKA-12-125A | 3 | 934 | NAKRETKA-M12-934 | 0 | 0 | 14 | 3 | 12 | 931 | SRUBA
13 x Bolt assembly | 12 | 100 | 4 | 125A | PODKLADKA-12-125A | 4 | 934 | NAKRETKA-M12-934 | 0 | 0 | 14 | 4 | 12 | 931 | SRUBA
Bolt assembly | 12 | 100 | 3 | 125A | PODKLADKA-12-125A | 3 | 934 | NAKRETKA-M12-934 | 0 | 0 | 14 | 3 | 12 | 931 | SRUBA
149 x Bolt assembly | 12 | 40 | 4 | 125A | PODKLADKA-12-125A | 2 | 934 | NAKRETKA-M12-934 | 0 | 0 | 13 | 2 | 12 | 931 | SRUBA
24 x Bolt assembly | 12 | 45 | 2 | 125A | PODKLADKA-12-125A | 1 | 934 | NAKRETKA-M12-934 | 0 | 0 | 13 | 1 | 12 | 931 | SRUBA
40 x Bolt assembly | 16 | 50 | 2 | 125A | PODKLADKA-16-125A | 1 | 934 | NAKRETKA-M16-934 | 0 | 0 | 18 | 1 | 16 | 931 | SRUBA
20 x Bolt assembly | 12 | 45 | 4 | 125A | PODKLADKA-12-125A | 2 | 934 | NAKRETKA-M12-934 | 0 | 0 | 13 | 2 | 12 | 931 | SRUBA
Bolt assembly | 12 | 30 | 2 | 125A | PODKLADKA-12-125A | 1 | 934 | NAKRETKA-M12-934 | 0 | 0 | 13 | 1 | 12 | 931 | SRUBA
2 x Bolt assembly | 16 | 10 | 0 | 125A | PODKLADKA-16-125A | 0 | 934 | NAKRETKA-M16-934 | 0 | 30 | 18 | 2 | 18 | 931 | SRUBA
2 x Bolt assembly | 16 | 45 | 4 | 125A | PODKLADKA-16-125A | 2 | 934 | NAKRETKA-M16-934 | 0 | 0 | 18 | 2 | 16 | 931 | SRUBA
Bolt assembly | 16 | 5.3 | 0 | 125A | PODKLADKA-16-125A | 0 | 934 | NAKRETKA-M16-934 | 0 | 30 | 18 | 2 | 18 | 931 | SRUBA
19 x Bolt assembly | 12 | 40 | 4 | 125A | PODKLADKA-12-125A | 2 | 934 | NAKRETKA-M12-934 | 27 | 0 | 13 | 2 | 12 | 931 | SRUBA
16 x Bolt assembly | 12 | 40 | 2 | 125A | PODKLADKA-12-125A | 1 | 934 | NAKRETKA-M12-934 | 0 | 0 | 13 | 1 | 12 | 931 | SRUBA
Bolt assembly | 12 | 44 | 7 | 126_HILTI | PODKLADKA-12-126-HILTI | 7 | 934_HILTI | NAKRETKA-M12-934-HILTI | 0 | 0 | 14 | 7 | 12 | H - HVU/HA | HILTI HVU/HAS M12X160/28
12 x Bolt assembly | 12 | 44 | 4 | 126_HILTI | PODKLADKA-12-126-HILTI | 4 | 934_HILTI | NAKRETKA-M12-934-HILTI | 0 | 0 | 14 | 4 | 12 | H - HVU/HA | HILTI HVU/HAS M12X160/28
23 x Bolt assembly | 12 | 40 | 4 | 125A | PODKLADKA-12-125A | 2 | 934 | NAKRETKA-M12-934 | 0 | 27 | 13 | 2 | 12 | 931 | SRUBA
8 x Bolt assembly | 12 | 44 | 3 | 126_HILTI | PODKLADKA-12-126-HILTI | 3 | 934_HILTI | NAKRETKA-M12-934-HILTI | 0 | 0 | 14 | 3 | 12 | H - HVU/HA | HILTI HVU/HAS M12X160/28
6 x Bolt assembly | 12 | 44 | 2 | 126_HILTI | PODKLADKA-12-126-HILTI | 2 | 934_HILTI | NAKRETKA-M12-934-HILTI | 0 | 0 | 14 | 2 | 12 | H - HVU/HA | HILTI HVU/HAS M12X160/28
7 x Bolt assembly | 12 | 44 | 5 | 126_HILTI | PODKLADKA-12-126-HILTI | 5 | 934_HILTI | NAKRETKA-M12-934-HILTI | 0 | 0 | 14 | 5 | 12 | H - HVU/HA | HILTI HVU/HAS M12X160/28
3 x Bolt assembly | 12 | 45 | 8 | 125A | PODKLADKA-12-125A | 4 | 934 | NAKRETKA-M12-934 | 0 | 0 | 13 | 4 | 12 | 931 | SRUBA
10 x Bolt assembly | 16 | 58 | 4 | 126_HILTI | PODKLADKA-16-126-HILTI | 4 | 934_HILTI | NAKRETKA-M16-934-HILTI | 0 | 0 | 18 | 4 | 16 | H - HVU/HA | HILTI HVU/HAS M16X190/38
2 x Bolt assembly | 12 | 45 | 4 | 6916 | PODKLADKA-12-6916 | 2 | 6915 | NAKRETKA-M12-6915 | 0 | 0 | 13 | 2 | 12 | 6914 | SRUBA
2 x Bolt assembly | 12 | 45 | 8 | 6916 | PODKLADKA-12-6916 | 4 | 6915 | NAKRETKA-M12-6915 | 0 | 0 | 13 | 4 | 12 | 6914 | SRUBA
10 x Bolt assembly | 20 | 60 | 8 | 125A | PODKLADKA-20-125A | 4 | 934 | NAKRETKA-M20-934 | 0 | 0 | 22 | 4 | 20 | 931 | SRUBA
10 x Bolt assembly | 20 | 65 | 4 | 6916 | PODKLADKA-21-6916 | 2 | 6915 | NAKRETKA-M20-6915 | 0 | 0 | 22 | 2 | 20 | 6914 | SRUBA
10 x Bolt assembly | 20 | 65 | 8 | 6916 | PODKLADKA-21-6916 | 4 | 6915 | NAKRETKA-M20-6915 | 0 | 0 | 22 | 4 | 20 | 6914 | SRUBA

# IfcMember: D16 (40)
In: Undefined
Description: D16; Material: STEEL/S355JR
Tekla Common - Phase: 11; Class: 5
Tekla Quantity - Volume: 0 m3; Gross footprint area: 0 m2; Height: 16 mm; Width: 16 mm
Pset_MemberCommon - LoadBearing: yes
BaseQuantities - CrossSectionArea: 0.000192 m2
Name | Bottom elevation | Top elevation | Weight (kg) | Area per tons (m2) | Net surface area (m2) | Tekla Quantity, Length (mm) | Reference | BaseQuantities, Length (mm) | OuterSurfaceArea (m2) = GrossSurfaceArea (m2) | NetVolume (m3) = GrossVolume (m3) | NetWeight (kg) = GrossWeight (kg)
STĘŻENIE | +0.096 | +1.238 | 3 | 33.1 | 0.1 | 1971.4 | 1150(?) | 1971.41 | 0.0983478 | 0.000378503 | 2.97125
STĘŻENIE | +0.124 | +1.266 | 3 | 33.1 | 0.1 | 1971.4 | 1150(?) | 1971.33 | 0.0983456 | 0.000378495 | 2.97118
STĘŻENIE | +0.126 | +1.259 | 2.8 | 33.1 | 0.1 | 1839.4 | 1149(?) | 1839.42 | 0.091791 | 0.000353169 | 2.77238
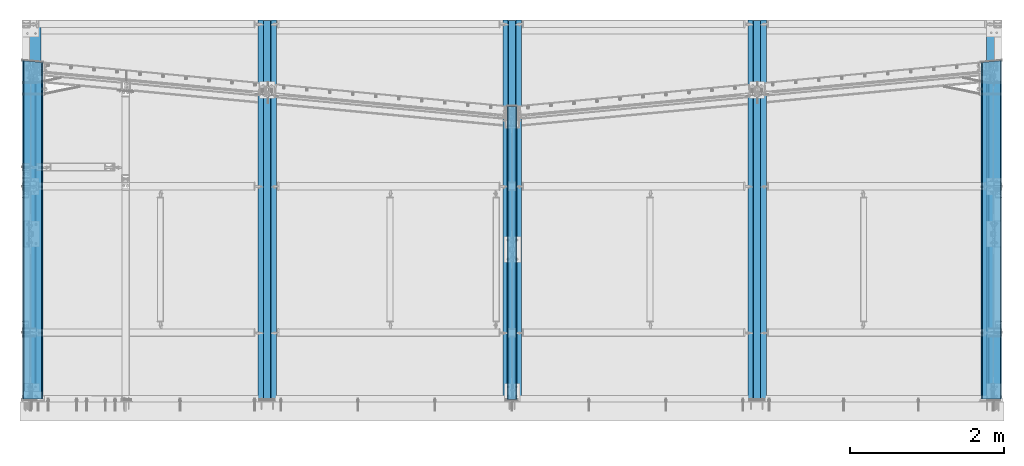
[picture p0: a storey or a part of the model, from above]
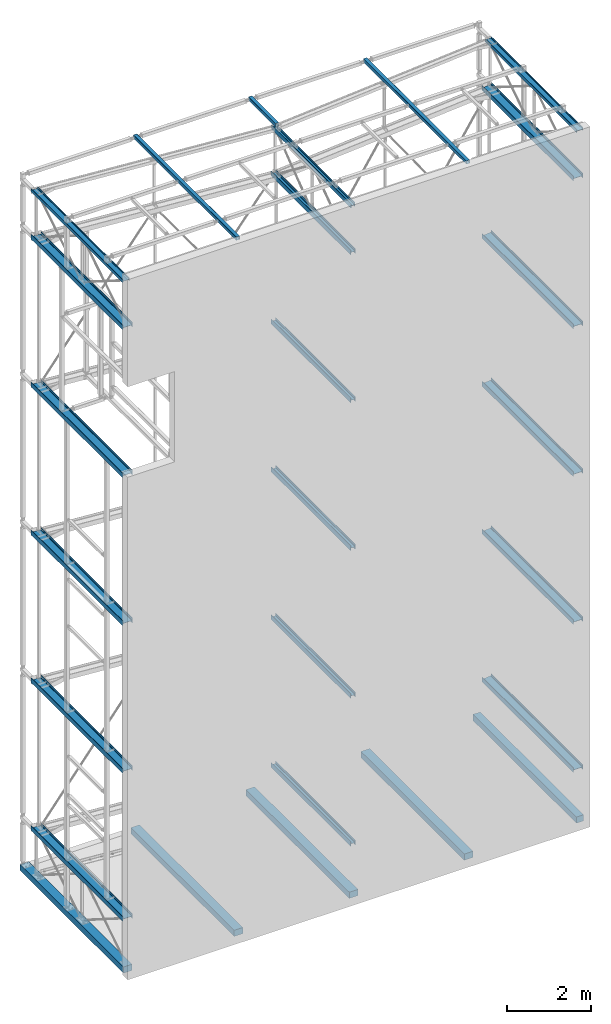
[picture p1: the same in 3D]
Properties of the parts of a building model (IFC2X3), part 2 of 3

# IfcMember: D16 (40)
Name | Bottom elevation | Top elevation | Weight (kg) | Area per tons (m2) | Net surface area (m2) | Tekla Quantity, Length (mm) | Reference | BaseQuantities, Length (mm) | OuterSurfaceArea (m2) = GrossSurfaceArea (m2) | NetVolume (m3) = GrossVolume (m3) | NetWeight (kg) = GrossWeight (kg)
STĘŻENIE | +0.103 | +1.249 | 2.8 | 33.1 | 0.1 | 1853.8 | 1148(?) | 1853.79 | 0.0925039 | 0.000355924 | 2.794
STĘŻENIE | +18.771 | +19.906 | 3 | 33.1 | 0.1 | 1967.4 | 1150 | 1967.37 | 0.0981491 | 0.000377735 | 2.96522
STĘŻENIE | +18.743 | +19.878 | 3 | 33.1 | 0.1 | 1967.4 | 1150 | 1967.37 | 0.0981491 | 0.000377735 | 2.96522
STĘŻENIE | +18.750 | +19.886 | 2.8 | 33.1 | 0.1 | 1843.9 | 1149 | 1843.93 | 0.092015 | 0.000354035 | 2.77917
STĘŻENIE | +18.760 | +19.899 | 2.8 | 33.1 | 0.1 | 1848.9 | 1148 | 1848.9 | 0.0922621 | 0.00035499 | 2.78667
2 x STĘŻENIE | +18.768 | +19.909 | 3.2 | 33.1 | 0.1 | 2114.4 | 1141 | 2114.38 | 0.105454 | 0.000405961 | 3.18679
2 x STĘŻENIE | +18.741 | +19.881 | 3.2 | 33.1 | 0.1 | 2114.4 | 1141 | 2114.38 | 0.105454 | 0.000405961 | 3.18679
2 x STĘŻENIE | +18.741 | +19.920 | 3.3 | 33.1 | 0.1 | 2187.5 | 1140 | 2187.54 | 0.10909 | 0.000420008 | 3.29706
2 x STĘŻENIE | +18.749 | +19.909 | 3.2 | 33.1 | 0.1 | 2150 | 1139 | 2150.03 | 0.107226 | 0.000412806 | 3.24053
STĘŻENIE | +0.093 | +1.241 | 3.2 | 33.1 | 0.1 | 2118.8 | 1141(?) | 2118.82 | 0.105675 | 0.000406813 | 3.19348
STĘŻENIE | +0.110 | +1.268 | 3.2 | 33.1 | 0.1 | 2125.2 | 1141(?) | 2125.16 | 0.10599 | 0.00040803 | 3.20304
STĘŻENIE | +0.082 | +1.268 | 3.3 | 33.1 | 0.1 | 2191.3 | 1140(?) | 2191.29 | 0.109276 | 0.000420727 | 3.30271
STĘŻENIE | +0.093 | +1.265 | 3.3 | 33.1 | 0.1 | 2168.8 | 1139(?) | 2168.78 | 0.108158 | 0.000416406 | 3.26879
STĘŻENIE | +0.093 | +1.241 | 3.2 | 33.1 | 0.1 | 2118.8 | 1141(?) | 2118.73 | 0.10567 | 0.000406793 | 3.19332
STĘŻENIE | +0.120 | +1.268 | 3.2 | 33.1 | 0.1 | 2119.9 | 1141(?) | 2119.92 | 0.105729 | 0.00040702 | 3.19511
STĘŻENIE | +0.082 | +1.268 | 3.3 | 33.1 | 0.1 | 2191.7 | 1140(?) | 2191.74 | 0.109298 | 0.000420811 | 3.30337
STĘŻENIE | +0.093 | +1.260 | 3.2 | 33.1 | 0.1 | 2154.5 | 1139(?) | 2154.5 | 0.107447 | 0.00041366 | 3.24723
STĘŻENIE | +14.507 | +18.527 | 7.5 | 33 | 0.2 | 4914 | 1051 | 4913.97 | 0.244575 | 0.000943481 | 7.40633
STĘŻENIE | +14.442 | +18.461 | 7.5 | 33 | 0.2 | 4914 | 1051 | 4913.96 | 0.244575 | 0.000943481 | 7.40633
STĘŻENIE | +14.506 | +18.548 | 7.5 | 33 | 0.2 | 4962.8 | 1050 | 4962.78 | 0.247001 | 0.000952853 | 7.4799
2 x STĘŻENIE | +14.420 | +18.463 | 7.5 | 33 | 0.2 | 4959.9 | 1049 | 4959.91 | 0.246858 | 0.000952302 | 7.47557
STĘŻENIE | +14.507 | +18.527 | 7.5 | 33 | 0.2 | 4914 | 1051 | 4913.96 | 0.244575 | 0.000943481 | 7.40633
STĘŻENIE | +14.442 | +18.461 | 7.5 | 33 | 0.2 | 4914 | 1051 | 4913.97 | 0.244575 | 0.000943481 | 7.40633
STĘŻENIE | +14.506 | +18.548 | 7.5 | 33 | 0.2 | 4962.8 | 1050 | 4962.78 | 0.247 | 0.000952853 | 7.4799
STĘŻENIE | +1.547 | +5.567 | 7.3 | 33 | 0.2 | 4914 | 1051 | 4913.97 | 0.244575 | 0.000943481 | 7.40633
STĘŻENIE | +1.482 | +5.501 | 7.3 | 33 | 0.2 | 4914 | 1051 | 4913.96 | 0.244575 | 0.000943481 | 7.40633
STĘŻENIE | +1.546 | +5.588 | 7.5 | 33 | 0.2 | 4962.8 | 1050 | 4962.78 | 0.247001 | 0.000952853 | 7.4799
2 x STĘŻENIE | +1.460 | +5.503 | 7.5 | 33 | 0.2 | 4959.9 | 1049 | 4959.91 | 0.246858 | 0.000952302 | 7.47557
STĘŻENIE | +1.547 | +5.567 | 7.3 | 33 | 0.2 | 4914 | 1051 | 4913.96 | 0.244575 | 0.000943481 | 7.40633
STĘŻENIE | +1.482 | +5.501 | 7.3 | 33 | 0.2 | 4914 | 1051 | 4913.97 | 0.244575 | 0.000943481 | 7.40633
STĘŻENIE | +1.546 | +5.588 | 7.5 | 33 | 0.2 | 4962.8 | 1050 | 4962.78 | 0.247 | 0.000952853 | 7.4799

# IfcPlate: BL10*100 (27)
In: Undefined
Description: BL10*100; Material: STEEL/S355JR
Pset_PlateCommon - LoadBearing: no
Tekla Common - Class: 99
Tekla Quantity - Volume: 0 m3; Gross footprint area: 0 m2; Height: 100 mm; Width: 10 mm
BaseQuantities - Width: 100 mm; CrossSectionArea: 0.0001 m2
Name | Reference | Bottom elevation | Top elevation | Phase | Weight (kg) | Area per tons (m2) | Net surface area (m2) | Length (mm) | NetArea (m2) | GrossArea (m2) | NetVolume (m3) = GrossVolume (m3)
BLACHA | L0(?) | +1.261 | +1.361 | 12 | 2 | 29 | 0.1 | 280 | 0.0586944 | 0.028 | 0.000258
2 x BLACHA | 1082 | +18.648 | +18.748 | 2 | 2 | 29 | 0.1 | 269 | 0.0573199 | 0.0269 | 0.00025275
BLACHA | 1122 | +19.901 | +20.001 | 3 | 1.1 | 29.6 | 0 | 163.2 | 0.0338738 | 0.0163185 | 0.000146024
BLACHA | 1085 | +1.261 | +1.361 | 3 | 1.7 | 29 | 0.1 | 249.2 | 0.0520414 | 0.0249165 | 0.00022885
BLACHA | 1115 | +18.541 | +18.641 | 3 | 2 | 29 | 0.1 | 249.2 | 0.0538757 | 0.0249165 | 0.00023685
BLACHA | 1112 | +14.328 | +14.428 | 3 | 2 | 29 | 0.1 | 249.2 | 0.05571 | 0.0249165 | 0.00024485
BLACHA | 1086 | +1.261 | +1.361 | 3 | 1.7 | 29 | 0.1 | 249.2 | 0.0520414 | 0.0249165 | 0.00022885
2 x BLACHA | 1084 | +5.688 | +5.788 | 3 | 1.7 | 29 | 0.1 | 249.2 | 0.0520414 | 0.0249165 | 0.00022885
2 x BLACHA | 1084 | +9.901 | +10.001 | 3 | 1.7 | 29 | 0.1 | 249.2 | 0.0520414 | 0.0249165 | 0.00022885
2 x BLACHA | 1084 | +10.008 | +10.108 | 3 | 1.7 | 29 | 0.1 | 249.2 | 0.0520414 | 0.0249165 | 0.00022885
2 x BLACHA | 1084 | +14.221 | +14.321 | 3 | 1.7 | 29 | 0.1 | 249.2 | 0.0520414 | 0.0249165 | 0.00022885
BLACHA | 1086 | +18.648 | +18.748 | 3 | 1.7 | 29 | 0.1 | 249.2 | 0.0520414 | 0.0249165 | 0.00022885
BLACHA | 1085 | +18.648 | +18.748 | 3 | 1.7 | 29 | 0.1 | 249.2 | 0.0520414 | 0.0249165 | 0.00022885
2 x BLACHA | 1081 | +14.221 | +14.321 | 2 | 2 | 29 | 0.1 | 265 | 0.0560056 | 0.0265 | 0.00024675
2 x BLACHA | 1081 | +10.008 | +10.108 | 2 | 2 | 29 | 0.1 | 265 | 0.0560056 | 0.0265 | 0.00024675
2 x BLACHA | 1081 | +9.901 | +10.001 | 2 | 2 | 29 | 0.1 | 265 | 0.0560056 | 0.0265 | 0.00024675
2 x BLACHA | 1081 | +5.688 | +5.788 | 2 | 2 | 29 | 0.1 | 265 | 0.0560056 | 0.0265 | 0.00024675
BLACHA | 1082(?) | +1.261 | +1.361 | 2 | 2 | 29 | 0.1 | 269 | 0.0573199 | 0.0269 | 0.00025275

# IfcPlate: BL10*110 (10)
In: Undefined
Description: BL10*110; Material: STEEL/S355JR
Tekla Common - Phase: 5; Class: 99
Tekla Quantity - Volume: 0 m3; Gross footprint area: 0 m2; Area per tons: 28.8 m2; Net surface area: 0.1 m2; Height: 110 mm; Width: 10 mm; Length: 253 mm
Pset_PlateCommon - LoadBearing: no
BaseQuantities - Width: 110 mm; GrossArea: 0.02783 m2; CrossSectionArea: 0.0001 m2
Name | Bottom elevation | Top elevation | Weight (kg) | Reference | NetArea (m2) | NetVolume (m3) = GrossVolume (m3)
BLACHA | +18.532 | +18.642 | 2.1 | 1130 | 0.0592514 | 0.0002623
BLACHA | +14.327 | +14.437 | 2.1 | 1130 | 0.0592514 | 0.0002623
BLACHA | +5.572 | +5.682 | 2.1 | 1130 | 0.0592514 | 0.0002623
BLACHA | +1.367 | +1.477 | 2.1 | 1130 | 0.0592514 | 0.0002623
BLACHA | +18.647 | +18.757 | 2.1 | 1087 | 0.0592514 | 0.0002623
BLACHA | +1.252 | +1.362 | 2.1 | 1087(?) | 0.0592514 | 0.0002623
BLACHA | +5.687 | +5.797 | 2 | 1083 | 0.0586256 | 0.00026005
BLACHA | +14.212 | +14.322 | 2 | 1083 | 0.0586256 | 0.00026005
BLACHA | +10.007 | +10.117 | 2 | 1083 | 0.0586256 | 0.00026005
BLACHA | +9.892 | +10.002 | 2 | 1083 | 0.0586256 | 0.00026005

# IfcPlate: BL10*119 (8)
In: Undefined
Description: BL10*119; Material: STEEL/S355JR
Tekla Common - Phase: 2; Class: 99
Tekla Quantity - Weight: 0.7 kg; Volume: 0 m3; Gross footprint area: 0 m2; Net surface area: 0 m2; Height: 118.8 mm; Width: 10 mm; Length: 87.6 mm
Pset_PlateCommon - LoadBearing: no
BaseQuantities - Width: 118.832 mm; GrossArea: 0.0104079 m2; CrossSectionArea: 0.0001 m2
Name | Bottom elevation | Top elevation | Area per tons (m2) | Reference | NetArea (m2) | NetVolume (m3) | GrossVolume (m3)
2 x BLACHA | +18.521 | +18.640 | 31.1 | 1133 | 0.0184909 | 0.0000757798 | 0.0000909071
BLACHA | +14.328 | +14.448 | 31.1 | 1133 | 0.0184909 | 0.0000757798 | 0.0000909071
BLACHA | +14.328 | +14.448 | 31 | 1094 | 0.0202078 | 0.0000832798 | 0.0000984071
BLACHA | +1.368 | +1.488 | 31.1 | 1133 | 0.0184909 | 0.0000757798 | 0.0000909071
2 x BLACHA | +5.561 | +5.680 | 31.1 | 1133 | 0.0184909 | 0.0000757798 | 0.0000909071
BLACHA | +1.368 | +1.488 | 31 | 1094(?) | 0.0202078 | 0.0000832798 | 0.0000984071

# IfcPlate: BL10*130 (2)
In: Undefined
Description: BL10*130; Material: STEEL/S355JR
Pset_PlateCommon - LoadBearing: no
Tekla Common - Class: 99
Tekla Quantity - Volume: 0 m3; Gross footprint area: 0 m2; Height: 130 mm; Width: 10 mm
BaseQuantities - Width: 130 mm; CrossSectionArea: 0.0001 m2
Name | Reference | Bottom elevation | Top elevation | Phase | Weight (kg) | Area per tons (m2) | Net surface area (m2) | Length (mm) | NetArea (m2) | GrossArea (m2) | NetVolume (m3) | GrossVolume (m3)
BLACHA | L0(?) | -0.000 | +0.130 | 12 | 2.6 | 28.4 | 0.1 | 271 | 0.0738528 | 0.03523 | 0.0003318 | 0.0003318
BLACHA | 1159 | +19.872 | +20.002 | 5 | 0.9 | 30.2 | 0 | 97.2 | 0.026704 | 0.0126331 | 0.000112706 | 0.00032955

# IfcPlate: BL10*135, BLACHA
In: Undefined
Description: BL10*135; Material: STEEL/S355JR
Pset_PlateCommon - LoadBearing: no; Reference: 0(?)
Tekla Common - Bottom elevation: +0.000; Top elevation: +0.135; Phase: 1; Class: 99
Tekla Quantity - Weight: 2 kg; Volume: 0 m3; Gross footprint area: 0 m2; Area per tons: 28.6 m2; Net surface area: 0.1 m2; Height: 135 mm; Width: 10 mm; Length: 226.3 mm
BaseQuantities - Width: 134.997 mm; NetArea: 0.0585243 m2; GrossArea: 0.0305446 m2; CrossSectionArea: 0.0001 m2; NetVolume: 0.000260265 m3; GrossVolume: 0.000260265 m3

# IfcPlate: BL10*146 (7)
In: Undefined
Description: BL10*146; Material: STEEL/S355JR
Tekla Common - Class: 99
Tekla Quantity - Volume: 0 m3; Gross footprint area: 0 m2; Height: 145.8 mm; Width: 10 mm
Pset_PlateCommon - LoadBearing: no
BaseQuantities - CrossSectionArea: 0.0001 m2
Name | Bottom elevation | Top elevation | Phase | Weight (kg) | Area per tons (m2) | Net surface area (m2) | Length (mm) | Reference | Width (mm) | NetArea (m2) | GrossArea (m2) | NetVolume (m3) = GrossVolume (m3)
2 x BLACHA | +18.648 | +18.793 | 2 | 1.7 | 28.8 | 0.1 | 191.7 | 1142 | 145.824 | 0.0519868 | 0.0279606 | 0.000230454
2 x BLACHA | +19.856 | +20.002 | 2 | 1.6 | 29.1 | 0 | 194.7 | 1144 | 145.824 | 0.0469171 | 0.0283935 | 0.000205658
2 x BLACHA | +1.215 | +1.361 | 2 | 2.1 | 28.6 | 0.1 | 191 | 1142(?) | 145.889 | 0.0595812 | 0.0278712 | 0.000265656
BLACHA | +0.000 | +0.146 | 12 | 2 | 28.8 | 0.1 | 224.7 | L0(?) | 145.824 | 0.0565794 | 0.0327682 | 0.000250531

# IfcPlate: BL10*147 (4)
In: Undefined
Description: BL10*147; Material: STEEL/S355JR
Pset_PlateCommon - LoadBearing: no
Tekla Common - Class: 99
Tekla Quantity - Volume: 0 m3; Gross footprint area: 0 m2; Height: 147 mm; Width: 10 mm
BaseQuantities - Width: 146.992 mm; CrossSectionArea: 0.0001 m2
Name | Reference | Bottom elevation | Top elevation | Phase | Weight (kg) | Area per tons (m2) | Net surface area (m2) | Length (mm) | NetArea (m2) | GrossArea (m2) | NetVolume (m3) = GrossVolume (m3)
BLACHA | L0(?) | +0.000 | +0.147 | 12 | 2.1 | 28.4 | 0.1 | 214.2 | 0.0601182 | 0.0314855 | 0.000268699
BLACHA | 1152(?) | +1.215 | +1.362 | 5 | 1.7 | 28.8 | 0.1 | 182.2 | 0.0500706 | 0.0267818 | 0.000221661
BLACHA | 1152 | +18.647 | +18.794 | 5 | 1.7 | 28.8 | 0.1 | 182.2 | 0.0500706 | 0.0267818 | 0.000221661
BLACHA | 1152 | +19.855 | +20.002 | 5 | 1.7 | 28.8 | 0 | 181.8 | 0.0499576 | 0.0267289 | 0.000221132

# IfcPlate: BL10*150 (8)
In: Undefined
Description: BL10*150; Material: STEEL/S355JR
Tekla Common - Phase: 2; Class: 99
Tekla Quantity - Weight: 3 kg; Volume: 0 m3; Gross footprint area: 0 m2; Area per tons: 28 m2; Net surface area: 0.1 m2; Height: 150 mm; Width: 10 mm; Length: 265 mm
Pset_PlateCommon - LoadBearing: no
BaseQuantities - Width: 150 mm; NetArea: 0.0835056 m2; GrossArea: 0.03975 m2; CrossSectionArea: 0.0001 m2; NetVolume: 0.00037925 m3; GrossVolume: 0.00037925 m3
Name | Bottom elevation | Top elevation | Reference
2 x BLACHA | +14.328 | +14.478 | 1092
2 x BLACHA | +18.491 | +18.641 | 1092
BLACHA | +1.368 | +1.518 | 1092
2 x BLACHA | +5.531 | +5.681 | 1092
BLACHA | +1.368 | +1.518 | 1092(?)

# IfcPlate: BL10*40 (2)
In: Undefined
Description: BL10*40; Material: STEEL/S355JR
Tekla Common - Bottom elevation: +20.007; Top elevation: +20.047; Phase: 2; Class: 99
Tekla Quantity - Weight: 0.9 kg; Volume: 0 m3; Gross footprint area: 0 m2; Area per tons: 32.7 m2; Net surface area: 0 m2; Height: 40 mm; Width: 10 mm; Length: 280 mm
Pset_PlateCommon - LoadBearing: no; Reference: 1163
BaseQuantities - Width: 40 mm; NetArea: 0.0281743 m2; GrossArea: 0.0112 m2; CrossSectionArea: 0.0001 m2; NetVolume: 0.00010975 m3; GrossVolume: 0.00010975 m3

# IfcPlate: BL10*56 (16)
In: Undefined
Description: BL10*56; Material: STEEL/S355JR
Tekla Common - Phase: 11; Class: 99
Tekla Quantity - Weight: 0.7 kg; Volume: 0 m3; Gross footprint area: 0 m2; Area per tons: 35.8 m2; Net surface area: 0 m2; Height: 56 mm; Width: 10 mm; Length: 175 mm
Pset_PlateCommon - LoadBearing: no; Reference: 1093
BaseQuantities - CrossSectionArea: 0.0001 m2
Name | Bottom elevation | Top elevation | Width (mm) | NetArea (m2) | GrossArea (m2) | NetVolume (m3) = GrossVolume (m3)
2 x BLACHA | +18.424 | +18.591 | 56 | 0.0223943 | 0.0098 | 0.00007975
2 x BLACHA | +14.377 | +14.544 | 56 | 0.0223943 | 0.0098 | 0.00007975
BLACHA | +18.446 | +18.612 | 55.9535 | 0.0223864 | 0.00979186 | 0.0000797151
BLACHA | +14.356 | +14.523 | 55.9534 | 0.0223863 | 0.00979185 | 0.0000797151
BLACHA | +18.446 | +18.612 | 55.953 | 0.0223863 | 0.00979177 | 0.0000797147
BLACHA | +14.356 | +14.523 | 55.953 | 0.0223863 | 0.00979177 | 0.0000797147
2 x BLACHA | +1.417 | +1.584 | 56 | 0.0223943 | 0.0098 | 0.00007975
2 x BLACHA | +5.464 | +5.631 | 56 | 0.0223943 | 0.0098 | 0.00007975
BLACHA | +1.396 | +1.563 | 55.9534 | 0.0223863 | 0.00979185 | 0.0000797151
BLACHA | +5.486 | +5.652 | 55.9535 | 0.0223864 | 0.00979186 | 0.0000797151
BLACHA | +5.486 | +5.652 | 55.953 | 0.0223863 | 0.00979177 | 0.0000797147
BLACHA | +1.396 | +1.563 | 55.953 | 0.0223863 | 0.00979177 | 0.0000797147

# IfcPlate: BL10*70 (206)
In: Undefined
Description: BL10*70; Material: STEEL/S355JR
Pset_PlateCommon - LoadBearing: no
Tekla Common - Class: 99
Tekla Quantity - Weight: 0.4 kg; Volume: 0 m3; Gross footprint area: 0 m2; Net surface area: 0 m2; Height: 70 mm; Width: 10 mm
BaseQuantities - Width: 70 mm; CrossSectionArea: 0.0001 m2
Name | Reference | Bottom elevation | Top elevation | Phase | Area per tons (m2) | Length (mm) | NetArea (m2) | GrossArea (m2) | NetVolume (m3) = GrossVolume (m3)
BLACHA | L0(?) | +0.059 | +0.129 | 12 | 32.2 | 80 | 0.0135743 | 0.0056 | 0.00005375
BLACHA | 0(?) | +1.241 | +1.311 | 12 | 32.2 | 80 | 0.0135743 | 0.0056 | 0.00005375
2 x BLACHA | 1080(?) | +0.040 | +0.110 | 8 | 32.2 | 80 | 0.0135743 | 0.0056 | 0.00005375
2 x BLACHA | 1066 | +14.412 | +14.482 | 12 | 31.5 | 100 | 0.0167743 | 0.007 | 0.00006775
BLACHA | 1065 | +14.392 | +14.462 | 12 | 31.7 | 100 | 0.0174 | 0.007 | 0.00007
2 x BLACHA | 1066 | +17.054 | +17.124 | 12 | 31.5 | 100 | 0.0167743 | 0.007 | 0.00006775
BLACHA | 1065 | +17.074 | +17.144 | 12 | 31.7 | 100 | 0.0174 | 0.007 | 0.00007
10 x BLACHA | 1080 | +20.124 | +20.204 | 13 | 32.2 | 80 | 0.0135743 | 0.0056 | 0.00005375
10 x BLACHA | 1119 | +20.124 | +20.204 | 12 | 32.3 | 80 | 0.0142 | 0.0056 | 0.000056
BLACHA | 1080 | +18.512 | +18.582 | 8 | 32.2 | 80 | 0.0135743 | 0.0056 | 0.00005375
BLACHA | 1080 | +14.387 | +14.457 | 8 | 32.2 | 80 | 0.0135743 | 0.0056 | 0.00005375
BLACHA | 1080 | +5.552 | +5.622 | 8 | 32.2 | 80 | 0.0135743 | 0.0056 | 0.00005375
BLACHA | 1080 | +1.427 | +1.497 | 8 | 32.2 | 80 | 0.0135743 | 0.0056 | 0.00005375
2 x BLACHA | 1080 | +14.428 | +14.498 | 8 | 32.2 | 80 | 0.0135743 | 0.0056 | 0.00005375
2 x BLACHA | 1080 | +18.471 | +18.541 | 8 | 32.2 | 80 | 0.0135743 | 0.0056 | 0.00005375
2 x BLACHA | 1080 | +1.468 | +1.538 | 8 | 32.2 | 80 | 0.0135743 | 0.0056 | 0.00005375
2 x BLACHA | 1080 | +5.511 | +5.581 | 8 | 32.2 | 80 | 0.0135743 | 0.0056 | 0.00005375
BLACHA | 1080 | +19.872 | +19.942 | 8 | 32.2 | 80 | 0.0135743 | 0.0056 | 0.00005375
BLACHA | 1080(?) | +0.030 | +0.100 | 12 | 32.2 | 80 | 0.0135743 | 0.0056 | 0.00005375
BLACHA | 1080(?) | +0.030 | +0.100 | 8 | 32.2 | 80 | 0.0135743 | 0.0056 | 0.00005375
2 x BLACHA | 1080 | +19.902 | +19.972 | 8 | 32.2 | 80 | 0.0135743 | 0.0056 | 0.00005375
4 x BLACHA | 1080 | +18.698 | +18.768 | 8 | 32.2 | 80 | 0.0135743 | 0.0056 | 0.00005375
BLACHA | 1080 | +19.881 | +19.951 | 8 | 32.2 | 80 | 0.0135743 | 0.0056 | 0.00005375
BLACHA | 1080 | +19.901 | +19.971 | 8 | 32.2 | 80 | 0.0135743 | 0.0056 | 0.00005375
2 x BLACHA | 1080(?) | +1.241 | +1.311 | 8 | 32.2 | 80 | 0.0135743 | 0.0056 | 0.00005375
4 x BLACHA | 1066 | +20.104 | +20.204 | 7 | 31.5 | 100 | 0.0167743 | 0.007 | 0.00006775
3 x BLACHA | 1065 | +20.104 | +20.204 | 5 | 31.7 | 100 | 0.0174 | 0.007 | 0.00007
2 x BLACHA | 1080 | +4.494 | +4.504 | 13 | 32.2 | 80 | 0.0135743 | 0.0056 | 0.00005375
2 x BLACHA | 1119 | +4.484 | +4.494 | 12 | 32.3 | 80 | 0.0142 | 0.0056 | 0.000056
2 x BLACHA | 1080 | +3.354 | +3.364 | 13 | 32.2 | 80 | 0.0135743 | 0.0056 | 0.00005375
2 x BLACHA | 1119 | +3.364 | +3.374 | 12 | 32.3 | 80 | 0.0142 | 0.0056 | 0.000056
2 x BLACHA | 1080 | +3.074 | +3.084 | 13 | 32.2 | 80 | 0.0135743 | 0.0056 | 0.00005375
2 x BLACHA | 1119 | +3.064 | +3.074 | 12 | 32.3 | 80 | 0.0142 | 0.0056 | 0.000056
2 x BLACHA | 1080 | +1.694 | +1.704 | 13 | 32.2 | 80 | 0.0135743 | 0.0056 | 0.00005375
2 x BLACHA | 1119 | +1.704 | +1.714 | 12 | 32.3 | 80 | 0.0142 | 0.0056 | 0.000056
2 x BLACHA | 1080 | +9.665 | +9.675 | 13 | 32.2 | 80 | 0.0135743 | 0.0056 | 0.00005375
2 x BLACHA | 1119 | +9.655 | +9.665 | 12 | 32.3 | 80 | 0.0142 | 0.0056 | 0.000056
2 x BLACHA | 1080 | +8.285 | +8.295 | 13 | 32.2 | 80 | 0.0135743 | 0.0056 | 0.00005375
2 x BLACHA | 1119 | +8.295 | +8.305 | 12 | 32.3 | 80 | 0.0142 | 0.0056 | 0.000056
4 x BLACHA | 1080 | +11.407 | +11.417 | 13 | 32.2 | 80 | 0.0135743 | 0.0056 | 0.00005375
4 x BLACHA | 1119 | +11.397 | +11.407 | 12 | 32.3 | 80 | 0.0142 | 0.0056 | 0.000056
2 x BLACHA | 1080 | +7.149 | +7.159 | 13 | 32.2 | 80 | 0.0135743 | 0.0056 | 0.00005375
2 x BLACHA | 1119 | +7.159 | +7.169 | 12 | 32.3 | 80 | 0.0142 | 0.0056 | 0.000056
2 x BLACHA | 1080 | +8.529 | +8.539 | 13 | 32.2 | 80 | 0.0135743 | 0.0056 | 0.00005375
2 x BLACHA | 1119 | +8.519 | +8.529 | 12 | 32.3 | 80 | 0.0142 | 0.0056 | 0.000056
2 x BLACHA | 1080 | +15.789 | +15.799 | 13 | 32.2 | 80 | 0.0135743 | 0.0056 | 0.00005375
2 x BLACHA | 1119 | +15.799 | +15.809 | 12 | 32.3 | 80 | 0.0142 | 0.0056 | 0.000056
2 x BLACHA | 1080 | +17.169 | +17.179 | 13 | 32.2 | 80 | 0.0135743 | 0.0056 | 0.00005375
2 x BLACHA | 1119 | +17.159 | +17.169 | 12 | 32.3 | 80 | 0.0142 | 0.0056 | 0.000056
2 x BLACHA | 1080 | +2.767 | +2.777 | 13 | 32.2 | 80 | 0.0135743 | 0.0056 | 0.00005375
2 x BLACHA | 1119 | +2.757 | +2.767 | 12 | 32.3 | 80 | 0.0142 | 0.0056 | 0.000056
2 x BLACHA | 1080 | +4.272 | +4.282 | 13 | 32.2 | 80 | 0.0135743 | 0.0056 | 0.00005375
2 x BLACHA | 1119 | +4.282 | +4.292 | 12 | 32.3 | 80 | 0.0142 | 0.0056 | 0.000056
2 x BLACHA | 1080 | +12.912 | +12.922 | 13 | 32.2 | 80 | 0.0135743 | 0.0056 | 0.00005375
2 x BLACHA | 1119 | +12.922 | +12.932 | 12 | 32.3 | 80 | 0.0142 | 0.0056 | 0.000056
2 x BLACHA | 1066 | +17.189 | +17.199 | 13 | 31.5 | 100 | 0.0167743 | 0.007 | 0.00006775
2 x BLACHA | 1065 | +17.179 | +17.189 | 12 | 31.7 | 100 | 0.0174 | 0.007 | 0.00007
BLACHA | 1113 | +18.521 | +18.591 | 12 | 31.5 | 100 | 0.0167743 | 0.007 | 0.00006775
BLACHA | 1113 | +14.378 | +14.448 | 12 | 31.5 | 100 | 0.0167743 | 0.007 | 0.00006775
BLACHA | 1066 | +14.759 | +14.769 | 13 | 31.5 | 100 | 0.0167743 | 0.007 | 0.00006775
BLACHA | 1065 | +14.769 | +14.779 | 12 | 31.7 | 100 | 0.0174 | 0.007 | 0.00007
BLACHA | 1066 | +16.059 | +16.069 | 13 | 31.5 | 100 | 0.0167743 | 0.007 | 0.00006775
BLACHA | 1065 | +16.049 | +16.059 | 12 | 31.7 | 100 | 0.0174 | 0.007 | 0.00007
2 x BLACHA | 1066 | +17.144 | +17.244 | 12 | 31.5 | 100 | 0.0167743 | 0.007 | 0.00006775
BLACHA | 1065 | +17.144 | +17.244 | 12 | 31.7 | 100 | 0.0174 | 0.007 | 0.00007
2 x BLACHA | 1066 | +14.292 | +14.392 | 12 | 31.5 | 100 | 0.0167743 | 0.007 | 0.00006775
BLACHA | 1065 | +14.292 | +14.392 | 2 | 31.7 | 100 | 0.0174 | 0.007 | 0.00007
BLACHA | 1065 | +17.144 | +17.244 | 13 | 31.7 | 100 | 0.0174 | 0.007 | 0.00007
BLACHA | 1065 | +14.292 | +14.392 | 13 | 31.7 | 100 | 0.0174 | 0.007 | 0.00007
BLACHA | 1065 | +17.074 | +17.144 | 13 | 31.7 | 100 | 0.0174 | 0.007 | 0.00007
BLACHA | 1065 | +14.392 | +14.462 | 13 | 31.7 | 100 | 0.0174 | 0.007 | 0.00007
BLACHA | 1080 | +18.707 | +18.777 | 8 | 32.2 | 80 | 0.0135743 | 0.0056 | 0.00005375
BLACHA | 1080 | +1.232 | +1.302 | 8 | 32.2 | 80 | 0.0135743 | 0.0056 | 0.00005375
BLACHA | 1080 | +5.747 | +5.817 | 8 | 32.2 | 80 | 0.0135743 | 0.0056 | 0.00005375
BLACHA | 1080 | +14.192 | +14.262 | 8 | 32.2 | 80 | 0.0135743 | 0.0056 | 0.00005375
BLACHA | 1080 | +10.067 | +10.137 | 8 | 32.2 | 80 | 0.0135743 | 0.0056 | 0.00005375
4 x BLACHA | 1080 | +5.738 | +5.808 | 8 | 32.2 | 80 | 0.0135743 | 0.0056 | 0.00005375
4 x BLACHA | 1080 | +9.881 | +9.951 | 8 | 32.2 | 80 | 0.0135743 | 0.0056 | 0.00005375
4 x BLACHA | 1080 | +10.058 | +10.128 | 8 | 32.2 | 80 | 0.0135743 | 0.0056 | 0.00005375
4 x BLACHA | 1080 | +14.201 | +14.271 | 8 | 32.2 | 80 | 0.0135743 | 0.0056 | 0.00005375
BLACHA | 1080 | +9.872 | +9.942 | 8 | 32.2 | 80 | 0.0135743 | 0.0056 | 0.00005375
BLACHA | 1080 | +1.241 | +1.311 | 8 | 32.2 | 80 | 0.0135743 | 0.0056 | 0.00005375
8 x BLACHA | 1066 | +20.104 | +20.204 | 12 | 31.5 | 100 | 0.0167743 | 0.007 | 0.00006775
6 x BLACHA | 1065 | +20.104 | +20.204 | 4 | 31.7 | 100 | 0.0174 | 0.007 | 0.00007
3 x BLACHA | 1065 | +20.104 | +20.204 | 2 | 31.7 | 100 | 0.0174 | 0.007 | 0.00007
BLACHA | 1066(?) | +0.020 | +0.090 | 7 | 31.5 | 100 | 0.0167743 | 0.007 | 0.00006775
BLACHA | L0(?) | +0.000 | +0.070 | 12 | 31.7 | 100 | 0.0174 | 0.007 | 0.00007
BLACHA | 1066 | +1.434 | +1.504 | 7 | 31.5 | 100 | 0.0167743 | 0.007 | 0.00006775
BLACHA | 1065(?) | +1.414 | +1.484 | 2 | 31.7 | 100 | 0.0174 | 0.007 | 0.00007
BLACHA | 1066 | +5.754 | +5.824 | 7 | 31.5 | 100 | 0.0167743 | 0.007 | 0.00006775
BLACHA | 1065 | +5.734 | +5.804 | 2 | 31.7 | 100 | 0.0174 | 0.007 | 0.00007
BLACHA | 1066 | +10.074 | +10.144 | 7 | 31.5 | 100 | 0.0167743 | 0.007 | 0.00006775
BLACHA | 1065 | +10.054 | +10.124 | 2 | 31.7 | 100 | 0.0174 | 0.007 | 0.00007
BLACHA | 1066 | +14.394 | +14.464 | 7 | 31.5 | 100 | 0.0167743 | 0.007 | 0.00006775
BLACHA | 1065 | +14.374 | +14.444 | 2 | 31.7 | 100 | 0.0174 | 0.007 | 0.00007
BLACHA | 1066 | +18.714 | +18.784 | 7 | 31.5 | 100 | 0.0167743 | 0.007 | 0.00006775
BLACHA | 1065 | +18.694 | +18.764 | 2 | 31.7 | 100 | 0.0174 | 0.007 | 0.00007
BLACHA | 1066 | +19.864 | +19.934 | 7 | 31.5 | 100 | 0.0167743 | 0.007 | 0.00006775
BLACHA | 1065 | +19.884 | +19.954 | 2 | 31.7 | 100 | 0.0174 | 0.007 | 0.00007
BLACHA | 1066 | +18.504 | +18.574 | 7 | 31.5 | 100 | 0.0167743 | 0.007 | 0.00006775
BLACHA | 1065 | +18.524 | +18.594 | 2 | 31.7 | 100 | 0.0174 | 0.007 | 0.00007
BLACHA | 1066(?) | +1.224 | +1.294 | 7 | 31.5 | 100 | 0.0167743 | 0.007 | 0.00006775
BLACHA | 1065 | +1.244 | +1.314 | 2 | 31.7 | 100 | 0.0174 | 0.007 | 0.00007
BLACHA | 1066 | +5.544 | +5.614 | 7 | 31.5 | 100 | 0.0167743 | 0.007 | 0.00006775
BLACHA | 1065 | +5.564 | +5.634 | 2 | 31.7 | 100 | 0.0174 | 0.007 | 0.00007
BLACHA | 1066 | +9.864 | +9.934 | 7 | 31.5 | 100 | 0.0167743 | 0.007 | 0.00006775
BLACHA | 1065 | +9.884 | +9.954 | 2 | 31.7 | 100 | 0.0174 | 0.007 | 0.00007
BLACHA | 1066 | +14.184 | +14.254 | 7 | 31.5 | 100 | 0.0167743 | 0.007 | 0.00006775
BLACHA | 1065 | +14.204 | +14.274 | 2 | 31.7 | 100 | 0.0174 | 0.007 | 0.00007

# IfcPlate: BL10*76, BLACHA
In: Undefined
Description: BL10*76; Material: STEEL/S355JR
Tekla Common - Bottom elevation: +1.261; Top elevation: +1.429; Phase: 2; Class: 99
Tekla Quantity - Weight: 1.5 kg; Volume: 0 m3; Gross footprint area: 0 m2; Area per tons: 30.2 m2; Net surface area: 0 m2; Height: 76 mm; Width: 10 mm; Length: 314.5 mm
Pset_PlateCommon - LoadBearing: no; Reference: 1156(?)
BaseQuantities - Width: 76.0027 mm; NetArea: 0.0459619 m2; GrossArea: 0.0239051 m2; CrossSectionArea: 0.0001 m2; NetVolume: 0.000193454 m3; GrossVolume: 0.000193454 m3

# IfcPlate: BL10*80 (7)
In: Undefined
Description: BL10*80; Material: STEEL/S355JR
Pset_PlateCommon - LoadBearing: no
Tekla Common - Class: 99
Tekla Quantity - Volume: 0 m3; Gross footprint area: 0 m2; Net surface area: 0 m2; Height: 80 mm; Width: 10 mm
BaseQuantities - Width: 80 mm; CrossSectionArea: 0.0001 m2
Name | Reference | Bottom elevation | Top elevation | Phase | Weight (kg) | Area per tons (m2) | Length (mm) | NetArea (m2) | GrossArea (m2) | NetVolume (m3) = GrossVolume (m3)
2 x BLACHA | L0(?) | +0.010 | +0.090 | 12 | 1.1 | 30 | 200 | 0.0339314 | 0.016 | 0.000144
BLACHA | L0(?) | +0.000 | +0.080 | 12 | 1.6 | 29.7 | 280 | 0.0470944 | 0.0224 | 0.000202
BLACHA | L0(?) | +0.000 | +0.080 | 12 | 1.6 | 29.7 | 280 | 0.0466601 | 0.0224 | 0.0002
2 x BLACHA | 1123 | +19.922 | +20.002 | 2 | 1.6 | 29.7 | 280 | 0.0460344 | 0.0224 | 0.00019775
BLACHA | 1121 | +19.921 | +20.001 | 3 | 0.9 | 30.2 | 163.2 | 0.0269464 | 0.0130548 | 0.000113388

# IfcPlate: BL10*90 (48)
In: Undefined
Description: BL10*90; Material: STEEL/S355JR
Tekla Common - Class: 99
Tekla Quantity - Weight: 0.7 kg; Volume: 0 m3; Gross footprint area: 0 m2; Net surface area: 0 m2; Height: 90 mm; Width: 10 mm
Pset_PlateCommon - LoadBearing: no
BaseQuantities - Width: 90 mm; CrossSectionArea: 0.0001 m2
Name | Bottom elevation | Top elevation | Phase | Area per tons (m2) | Length (mm) | Reference | NetArea (m2) | GrossArea (m2) | NetVolume (m3) = GrossVolume (m3)
4 x BLACHA | +20.104 | +20.204 | 7 | 30.7 | 100 | 1062 | 0.0211743 | 0.009 | 0.00008775
BLACHA | +20.104 | +20.204 | 5 | 31 | 100 | 1061 | 0.0218 | 0.009 | 0.00009
8 x BLACHA | +20.104 | +20.204 | 12 | 30.7 | 100 | 1062 | 0.0211743 | 0.009 | 0.00008775
3 x BLACHA | +20.104 | +20.204 | 2 | 31 | 100 | 1061 | 0.0218 | 0.009 | 0.00009
6 x BLACHA | +20.104 | +20.204 | 4 | 31 | 100 | 1061 | 0.0218 | 0.009 | 0.00009
2 x BLACHA | +20.104 | +20.200 | 5 | 31 | 96 | 1067 | 0.021 | 0.00864 | 0.0000864
BLACHA | +1.204 | +1.294 | 7 | 30.7 | 100 | 1062 | 0.0211743 | 0.009 | 0.00008775
BLACHA | +1.224 | +1.314 | 2 | 31 | 100 | 1061(?) | 0.0218 | 0.009 | 0.00009
BLACHA | +5.524 | +5.614 | 7 | 30.7 | 100 | 1062 | 0.0211743 | 0.009 | 0.00008775
BLACHA | +5.544 | +5.634 | 2 | 31 | 100 | 1061 | 0.0218 | 0.009 | 0.00009
BLACHA | +9.844 | +9.934 | 7 | 30.7 | 100 | 1062 | 0.0211743 | 0.009 | 0.00008775
BLACHA | +9.864 | +9.954 | 2 | 31 | 100 | 1061 | 0.0218 | 0.009 | 0.00009
BLACHA | +14.164 | +14.254 | 7 | 30.7 | 100 | 1062 | 0.0211743 | 0.009 | 0.00008775
BLACHA | +14.184 | +14.274 | 2 | 31 | 100 | 1061 | 0.0218 | 0.009 | 0.00009
BLACHA | +18.484 | +18.574 | 7 | 30.7 | 100 | 1062 | 0.0211743 | 0.009 | 0.00008775
BLACHA | +18.504 | +18.594 | 2 | 31 | 100 | 1061 | 0.0218 | 0.009 | 0.00009
BLACHA | +19.844 | +19.934 | 7 | 30.7 | 100 | 1062 | 0.0211743 | 0.009 | 0.00008775
BLACHA | +19.864 | +19.954 | 2 | 31 | 100 | 1061 | 0.0218 | 0.009 | 0.00009
BLACHA | +18.714 | +18.804 | 7 | 30.7 | 100 | 1062 | 0.0211743 | 0.009 | 0.00008775
BLACHA | +18.694 | +18.784 | 2 | 31 | 100 | 1061 | 0.0218 | 0.009 | 0.00009
BLACHA | +0.019 | +0.109 | 7 | 30.7 | 100 | 1062(?) | 0.0211743 | 0.009 | 0.00008775
BLACHA | -0.001 | +0.089 | 7 | 31 | 100 | 1061(?) | 0.0218 | 0.009 | 0.00009
BLACHA | +1.434 | +1.524 | 7 | 30.7 | 100 | 1062 | 0.0211743 | 0.009 | 0.00008775
BLACHA | +1.414 | +1.504 | 2 | 31 | 100 | 1061 | 0.0218 | 0.009 | 0.00009
BLACHA | +5.754 | +5.844 | 7 | 30.7 | 100 | 1062 | 0.0211743 | 0.009 | 0.00008775
BLACHA | +5.734 | +5.824 | 2 | 31 | 100 | 1061 | 0.0218 | 0.009 | 0.00009
BLACHA | +10.074 | +10.164 | 7 | 30.7 | 100 | 1062 | 0.0211743 | 0.009 | 0.00008775
BLACHA | +10.054 | +10.144 | 2 | 31 | 100 | 1061 | 0.0218 | 0.009 | 0.00009
BLACHA | +14.394 | +14.484 | 7 | 30.7 | 100 | 1062 | 0.0211743 | 0.009 | 0.00008775
BLACHA | +14.374 | +14.464 | 2 | 31 | 100 | 1061 | 0.0218 | 0.009 | 0.00009

# IfcPlate: BL10*98, BLACHA
In: Undefined
Description: BL10*98; Material: STEEL/S355JR
Tekla Common - Bottom elevation: +19.892; Top elevation: +20.002; Phase: 5; Class: 99
Tekla Quantity - Weight: 0.7 kg; Volume: 0 m3; Gross footprint area: 0 m2; Area per tons: 30.2 m2; Net surface area: 0 m2; Height: 98 mm; Width: 10 mm; Length: 110 mm
Pset_PlateCommon - LoadBearing: no; Reference: 1125
BaseQuantities - Width: 98 mm; NetArea: 0.0250943 m2; GrossArea: 0.01078 m2; CrossSectionArea: 0.0001 m2; NetVolume: 0.00010555 m3; GrossVolume: 0.00010555 m3

# IfcPlate: BL10*99 (8)
In: Undefined
Description: BL10*99; Material: STEEL/S355JR
Tekla Common - Phase: 3; Class: 99
Tekla Quantity - Weight: 0.7 kg; Volume: 0 m3; Gross footprint area: 0 m2; Net surface area: 0 m2; Width: 10 mm
Pset_PlateCommon - LoadBearing: no
BaseQuantities - CrossSectionArea: 0.0001 m2
Name | Bottom elevation | Top elevation | Area per tons (m2) | Height (mm) | Length (mm) | Reference | Width (mm) | NetArea (m2) | GrossArea (m2) | NetVolume (m3) = GrossVolume (m3)
BLACHA | +18.542 | +18.641 | 31 | 98.6 | 99.1 | 1132 | 98.5968 | 0.019067 | 0.00976719 | 0.0000783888
BLACHA | +14.328 | +14.427 | 30.7 | 99 | 103.3 | 1131 | 99.0442 | 0.0200805 | 0.0102268 | 0.0000829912
BLACHA | +18.542 | +18.641 | 31 | 98.6 | 99.1 | 1132 | 98.5956 | 0.0190668 | 0.00976705 | 0.0000783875
BLACHA | +14.328 | +14.427 | 30.7 | 99 | 103.3 | 1131 | 99.0439 | 0.0200805 | 0.0102268 | 0.0000829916
BLACHA | +1.368 | +1.467 | 30.7 | 99 | 103.3 | 1131 | 99.0442 | 0.0200805 | 0.0102268 | 0.0000829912
BLACHA | +5.582 | +5.681 | 31 | 98.6 | 99.1 | 1132 | 98.5968 | 0.019067 | 0.00976719 | 0.0000783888
BLACHA | +5.582 | +5.681 | 31 | 98.6 | 99.1 | 1132 | 98.5956 | 0.0190668 | 0.00976705 | 0.0000783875
BLACHA | +1.368 | +1.467 | 30.7 | 99 | 103.3 | 1131 | 99.0439 | 0.0200805 | 0.0102268 | 0.0000829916

# IfcPlate: BL12*120 (7)
In: Undefined
Description: BL12*120; Material: STEEL/S355JR
Pset_PlateCommon - LoadBearing: no
Tekla Common - Class: 99
Tekla Quantity - Weight: 3.4 kg; Volume: 0 m3; Gross footprint area: 0 m2; Area per tons: 24.2 m2; Net surface area: 0.1 m2; Width: 12 mm
BaseQuantities - CrossSectionArea: 0.000144 m2
Name | Reference | Bottom elevation | Top elevation | Phase | Height (mm) | Length (mm) | Width (mm) | NetArea (m2) | GrossArea (m2) | NetVolume (m3) = GrossVolume (m3)
BLACHA | L0(?) | -0.000 | +0.120 | 14 | 120.2 | 321.6 | 120.231 | 0.0817035 | 0.0386679 | 0.000430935
2 x BLACHA | 1146 | +19.881 | +20.002 | 2 | 120.2 | 321.6 | 120.231 | 0.0817035 | 0.0386679 | 0.000430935
2 x BLACHA | 1145 | +18.648 | +18.768 | 2 | 120 | 323.7 | 120 | 0.0820892 | 0.0388411 | 0.000432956
BLACHA | 1145(?) | +1.241 | +1.361 | 2 | 120.2 | 321.8 | 120.178 | 0.0817382 | 0.0386718 | 0.00043112
BLACHA | L0(?) | +0.000 | +0.120 | 12 | 120.2 | 321.6 | 120.231 | 0.0817035 | 0.0386679 | 0.000430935

# IfcPlate: BL12*121, BLACHA
In: Undefined
Description: BL12*121; Material: STEEL/S355JR
Pset_PlateCommon - LoadBearing: no; Reference: 1145(?)
Tekla Common - Bottom elevation: +1.240; Top elevation: +1.361; Phase: 2; Class: 99
Tekla Quantity - Weight: 3.4 kg; Volume: 0 m3; Gross footprint area: 0 m2; Area per tons: 24.1 m2; Net surface area: 0.1 m2; Height: 120.8 mm; Width: 12 mm; Length: 321.1 mm
BaseQuantities - Width: 120.804 mm; NetArea: 0.0817636 m2; GrossArea: 0.0387859 m2; CrossSectionArea: 0.000144 m2; NetVolume: 0.000431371 m3; GrossVolume: 0.000431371 m3

# IfcPlate: BL12*130 (4)
In: Undefined
Description: BL12*130; Material: STEEL/S355JR
Pset_PlateCommon - LoadBearing: no
Tekla Common - Class: 99
Tekla Quantity - Weight: 3.3 kg; Volume: 0 m3; Gross footprint area: 0 m2; Area per tons: 24.1 m2; Net surface area: 0.1 m2; Height: 130 mm; Width: 12 mm
BaseQuantities - CrossSectionArea: 0.000144 m2
Name | Reference | Bottom elevation | Top elevation | Phase | Length (mm) | Width (mm) | NetArea (m2) | GrossArea (m2) | NetVolume (m3) = GrossVolume (m3)
BLACHA | L0(?) | -0.000 | +0.130 | 12 | 299.4 | 130.026 | 0.079799 | 0.0389285 | 0.00042227
BLACHA | 1151(?) | +1.232 | +1.362 | 5 | 299.2 | 130 | 0.0796788 | 0.038902 | 0.000421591
BLACHA | 1153 | +19.872 | +20.002 | 5 | 299.4 | 130.026 | 0.079799 | 0.0389285 | 0.00042227
BLACHA | 1151 | +18.647 | +18.777 | 5 | 299.8 | 130 | 0.0798232 | 0.0389676 | 0.000422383

# IfcPlate: BL12*185 (8)
In: Undefined
Description: BL12*185; Material: STEEL/S355JR
Tekla Common - Phase: 3; Class: 99
Tekla Quantity - Weight: 4.9 kg; Volume: 0 m3; Gross footprint area: 0 m2; Area per tons: 23.4 m2; Net surface area: 0.1 m2; Height: 185 mm; Width: 12 mm
Pset_PlateCommon - LoadBearing: no; Reference: 1088
BaseQuantities - CrossSectionArea: 0.000144 m2
Name | Bottom elevation | Top elevation | Length (mm) | Width (mm) | NetArea (m2) | GrossArea (m2) | NetVolume (m3) = GrossVolume (m3)
BLACHA | +14.328 | +14.513 | 295.3 | 185.011 | 0.115221 | 0.0546259 | 0.000626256
BLACHA | +18.456 | +18.641 | 295.2 | 185.013 | 0.115251 | 0.0546244 | 0.000626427
BLACHA | +18.456 | +18.641 | 295.2 | 185.011 | 0.11525 | 0.0546237 | 0.000626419
BLACHA | +14.328 | +14.513 | 295.3 | 185.013 | 0.115222 | 0.0546265 | 0.000626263
BLACHA | +1.368 | +1.553 | 295.3 | 185.011 | 0.115221 | 0.0546259 | 0.000626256
BLACHA | +5.496 | +5.681 | 295.2 | 185.013 | 0.115251 | 0.0546244 | 0.000626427
BLACHA | +5.496 | +5.681 | 295.2 | 185.011 | 0.11525 | 0.0546237 | 0.000626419
BLACHA | +1.368 | +1.553 | 295.3 | 185.013 | 0.115222 | 0.0546265 | 0.000626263

# IfcPlate: BL12*56 (64)
In: Undefined
Description: BL12*56; Material: STEEL/S355JR
Tekla Common - Class: 99
Tekla Quantity - Volume: 0 m3; Gross footprint area: 0 m2; Net surface area: 0 m2; Height: 56 mm; Width: 12 mm
Pset_PlateCommon - LoadBearing: no
BaseQuantities - CrossSectionArea: 0.000144 m2
Name | Bottom elevation | Top elevation | Phase | Weight (kg) | Area per tons (m2) | Length (mm) | Reference | Width (mm) | NetArea (m2) | GrossArea (m2) | NetVolume (m3) = GrossVolume (m3)
BLACHA | +1.176 | +1.317 | 11 | 0.9 | 31 | 190 | 0(?) | 56 | 0.0257231 | 0.01064 | 0.00010578
2 x BLACHA | +1.184 | +1.327 | 11 | 0.9 | 31 | 194 | 0(?) | 56 | 0.0260671 | 0.010864 | 0.000107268
BLACHA | +0.058 | +0.215 | 11 | 0.9 | 30.7 | 200 | 0(?) | 56 | 0.0270831 | 0.0112 | 0.0001125
BLACHA | +1.182 | +1.325 | 11 | 0.9 | 31 | 194 | 1091(?) | 56 | 0.0260671 | 0.010864 | 0.000107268
2 x BLACHA | +0.034 | +0.177 | 11 | 0.9 | 31 | 194 | 0(?) | 56 | 0.0260671 | 0.010864 | 0.000107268
BLACHA | +1.159 | +1.310 | 11 | 0.9 | 31 | 190 | 0(?) | 56 | 0.0257231 | 0.01064 | 0.00010578
BLACHA | +0.059 | +0.210 | 12 | 0.9 | 30.7 | 200 | L0(?) | 56 | 0.0270831 | 0.0112 | 0.0001125
BLACHA | +1.179 | +1.327 | 11 | 0.9 | 31 | 194 | 0(?) | 56 | 0.0260671 | 0.010864 | 0.000107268
BLACHA | +0.047 | +0.194 | 11 | 0.9 | 30.7 | 200 | 0(?) | 56 | 0.0270831 | 0.0112 | 0.0001125
BLACHA | +18.698 | +18.849 | 11 | 0.9 | 31 | 190 | 1156 | 56 | 0.0257231 | 0.01064 | 0.00010578
BLACHA | +19.796 | +19.935 | 11 | 0.7 | 31.7 | 170 | 1162 | 56 | 0.0230031 | 0.00952 | 0.00009234
2 x BLACHA | +19.837 | +19.977 | 11 | 0.7 | 31 | 190 | 1156 | 56 | 0.0257231 | 0.01064 | 0.00010578
2 x BLACHA | +18.692 | +18.833 | 11 | 0.7 | 31 | 190 | 1156 | 56 | 0.0257231 | 0.01064 | 0.00010578
2 x BLACHA | +0.024 | +0.165 | 11 | 0.7 | 31 | 190 | 1156(?) | 56 | 0.0257231 | 0.01064 | 0.00010578
BLACHA | +0.039 | +0.192 | 11 | 0.7 | 31 | 194 | 1091(?) | 56 | 0.0260671 | 0.010864 | 0.000107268
BLACHA | +0.034 | +0.182 | 11 | 0.7 | 31 | 194 | 1091(?) | 56 | 0.0260671 | 0.010864 | 0.000107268
BLACHA | +1.169 | +1.323 | 11 | 0.7 | 31 | 194 | 1091(?) | 56 | 0.0260671 | 0.010864 | 0.000107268
BLACHA | +1.152 | +1.303 | 11 | 0.9 | 30.7 | 200 | 1143(?) | 56 | 0.0270831 | 0.0112 | 0.0001125
BLACHA | +19.819 | +19.968 | 11 | 0.7 | 31 | 194 | 1091 | 56 | 0.0260671 | 0.010864 | 0.000107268
BLACHA | +19.809 | +19.963 | 11 | 0.7 | 31 | 194 | 1091 | 56 | 0.0260671 | 0.010864 | 0.000107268
BLACHA | +18.706 | +18.857 | 11 | 0.9 | 30.7 | 200 | 1143 | 56 | 0.0270831 | 0.0112 | 0.0001125
BLACHA | +19.792 | +19.943 | 11 | 0.9 | 30.7 | 200 | 1143 | 56 | 0.0270831 | 0.0112 | 0.0001125
BLACHA | +18.686 | +18.839 | 11 | 0.7 | 31 | 194 | 1091 | 56 | 0.0260671 | 0.010864 | 0.000107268
BLACHA | +18.681 | +18.830 | 11 | 0.7 | 31 | 194 | 1091 | 56 | 0.0260671 | 0.010864 | 0.000107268
4 x BLACHA | +19.825 | +19.968 | 11 | 0.7 | 31 | 194 | 1091 | 56 | 0.0260671 | 0.010864 | 0.000107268
4 x BLACHA | +18.682 | +18.824 | 11 | 0.7 | 31 | 194 | 1091 | 56 | 0.0260671 | 0.010864 | 0.000107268
2 x BLACHA | +1.184 | +1.327 | 11 | 0.7 | 31 | 194 | 1091(?) | 56 | 0.0260671 | 0.010864 | 0.000107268
2 x BLACHA | +18.706 | +18.852 | 11 | 0.9 | 30.7 | 200 | 1143 | 56 | 0.0270831 | 0.0112 | 0.0001125
2 x BLACHA | +19.798 | +19.944 | 11 | 0.9 | 30.7 | 200 | 1143 | 56 | 0.0270831 | 0.0112 | 0.0001125
2 x BLACHA | +1.157 | +1.303 | 11 | 0.9 | 30.7 | 200 | 1143(?) | 56 | 0.0270831 | 0.0112 | 0.0001125
2 x BLACHA | +0.034 | +0.177 | 11 | 0.7 | 31 | 194 | 1091(?) | 56 | 0.0260671 | 0.010864 | 0.000107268
BLACHA | +0.058 | +0.204 | 11 | 0.9 | 30.7 | 200 | 1143(?) | 56 | 0.0270831 | 0.0112 | 0.0001125
BLACHA | +14.428 | +14.610 | 11 | 0.7 | 31 | 194 | 1091 | 55.9525 | 0.0260571 | 0.0108548 | 0.000107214
BLACHA | +14.426 | +14.608 | 11 | 0.7 | 31 | 194 | 1091 | 55.9534 | 0.0260572 | 0.010855 | 0.000107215
BLACHA | +18.361 | +18.542 | 11 | 0.7 | 31 | 194 | 1091 | 55.9534 | 0.0260572 | 0.010855 | 0.000107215
BLACHA | +18.359 | +18.541 | 11 | 0.7 | 31 | 194 | 1091 | 55.953 | 0.0260572 | 0.0108549 | 0.000107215
BLACHA | +18.359 | +18.541 | 11 | 0.7 | 31 | 194 | 1091 | 55.9525 | 0.0260571 | 0.0108548 | 0.000107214
BLACHA | +18.361 | +18.542 | 11 | 0.7 | 31 | 194 | 1091 | 55.9529 | 0.0260571 | 0.0108549 | 0.000107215
BLACHA | +14.426 | +14.608 | 11 | 0.7 | 31 | 194 | 1091 | 55.9529 | 0.0260571 | 0.0108549 | 0.000107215
BLACHA | +14.428 | +14.610 | 11 | 0.7 | 31 | 194 | 1091 | 55.953 | 0.0260572 | 0.0108549 | 0.000107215
BLACHA | +1.466 | +1.648 | 11 | 0.7 | 31 | 194 | 1091 | 55.9529 | 0.0260571 | 0.0108549 | 0.000107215
BLACHA | +5.401 | +5.582 | 11 | 0.7 | 31 | 194 | 1091 | 55.9534 | 0.0260572 | 0.010855 | 0.000107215
BLACHA | +5.399 | +5.581 | 11 | 0.7 | 31 | 194 | 1091 | 55.9525 | 0.0260571 | 0.0108548 | 0.000107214
BLACHA | +1.468 | +1.650 | 11 | 0.7 | 31 | 194 | 1091 | 55.9525 | 0.0260571 | 0.0108548 | 0.000107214
BLACHA | +1.466 | +1.648 | 11 | 0.7 | 31 | 194 | 1091 | 55.9534 | 0.0260572 | 0.010855 | 0.000107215
BLACHA | +5.399 | +5.581 | 11 | 0.7 | 31 | 194 | 1091 | 55.953 | 0.0260572 | 0.0108549 | 0.000107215
BLACHA | +5.401 | +5.582 | 11 | 0.7 | 31 | 194 | 1091 | 55.9529 | 0.0260571 | 0.0108549 | 0.000107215
BLACHA | +1.468 | +1.650 | 11 | 0.7 | 31 | 194 | 1091 | 55.953 | 0.0260572 | 0.0108549 | 0.000107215

# IfcPlate: BL12*90 (20)
In: Undefined
Description: BL12*90; Material: STEEL/S355JR
Pset_PlateCommon - LoadBearing: no
Tekla Common - Phase: 8; Class: 99
Tekla Quantity - Volume: 0 m3; Gross footprint area: 0 m2; Net surface area: 0 m2; Height: 90 mm; Width: 12 mm; Length: 174 mm
BaseQuantities - Width: 90 mm; GrossArea: 0.01566 m2; CrossSectionArea: 0.000144 m2
Name | Reference | Bottom elevation | Top elevation | Weight (kg) | Area per tons (m2) | NetArea (m2) | NetVolume (m3) = GrossVolume (m3)
BLACHA | 0(?) | +0.070 | +0.244 | 0.9 | 31 | 0.0271951 | 0.00011202
BLACHA | 1089(?) | +0.080 | +0.254 | 1.5 | 25.4 | 0.0369951 | 0.00018522
BLACHA | 1089(?) | +1.108 | +1.282 | 0.9 | 31 | 0.0271951 | 0.00011202
BLACHA | 1089 | +19.748 | +19.922 | 1.5 | 25.4 | 0.0369951 | 0.00018522
BLACHA | 1089 | +18.727 | +18.901 | 1.5 | 25.4 | 0.0369951 | 0.00018522
2 x BLACHA | 1089 | +19.757 | +19.931 | 1.5 | 25.4 | 0.0369951 | 0.00018522
2 x BLACHA | 1089 | +18.718 | +18.892 | 1.5 | 25.4 | 0.0369951 | 0.00018522
BLACHA | 1089(?) | +1.117 | +1.291 | 0.9 | 31 | 0.0271951 | 0.00011202
BLACHA | 1089(?) | +0.070 | +0.244 | 1.5 | 25.4 | 0.0369951 | 0.00018522
BLACHA | 1089(?) | +1.116 | +1.290 | 0.9 | 31 | 0.0271951 | 0.00011202
2 x BLACHA | 1089 | +14.463 | +14.637 | 1.5 | 25.4 | 0.0369951 | 0.00018522
2 x BLACHA | 1089 | +18.332 | +18.506 | 1.5 | 25.4 | 0.0369951 | 0.00018522
2 x BLACHA | 1089 | +1.503 | +1.677 | 1.5 | 25.4 | 0.0369951 | 0.00018522
2 x BLACHA | 1089 | +5.372 | +5.546 | 1.5 | 25.4 | 0.0369951 | 0.00018522

# IfcPlate: BL20*150 (2)
In: Undefined
Description: BL20*150; Material: Undefined/GROUT
Tekla Common - Bottom elevation: +19.929; Top elevation: +20.079; Phase: 8; Class: 92
Tekla Quantity - Weight: 0 kg; Volume: 0 m3; Gross footprint area: 0 m2; Area per tons: 0 m2; Net surface area: 0.1 m2; Height: 150 mm; Width: 20 mm; Length: 230 mm
Pset_PlateCommon - LoadBearing: no; Reference: L1
BaseQuantities - Width: 150 mm; NetArea: 0.0746333 m2; GrossArea: 0.0345 m2; CrossSectionArea: 0.0004 m2; NetVolume: 0.000548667 m3; GrossVolume: 0.00069 m3

# IfcPlate: BL20*160 (5)
In: Undefined
Description: BL20*160; Material: Undefined/GROUT
Tekla Common - Phase: 12; Class: 92
Tekla Quantity - Weight: 0 kg; Volume: 0 m3; Gross footprint area: 0 m2; Area per tons: 0 m2; Net surface area: 0.1 m2; Height: 160 mm; Width: 20 mm
Pset_PlateCommon - LoadBearing: no
BaseQuantities - Width: 160 mm; CrossSectionArea: 0.0004 m2
Name | Bottom elevation | Top elevation | Length (mm) | Reference | NetArea (m2) | GrossArea (m2) | NetVolume (m3) | GrossVolume (m3)
GROUT | +14.222 | +14.412 | 190 | L6 | 0.0659362 | 0.0304 | 0.000478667 | 0.000608
GROUT | +14.634 | +14.834 | 200 | L7 | 0.0693019 | 0.032 | 0.000506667 | 0.00064
GROUT | +15.994 | +16.194 | 200 | L7 | 0.0693019 | 0.032 | 0.000506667 | 0.00064
GROUT | +17.124 | +17.314 | 190 | L6 | 0.0659362 | 0.0304 | 0.000478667 | 0.000608
GROUT | +17.124 | +17.324 | 200 | L7 | 0.0693019 | 0.032 | 0.000506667 | 0.00064

# IfcPlate: BL20*174, GROUT
In: Undefined
Description: BL20*174; Material: Undefined/GROUT
Tekla Common - Bottom elevation: +19.904; Top elevation: +20.104; Phase: 8; Class: 92
Tekla Quantity - Weight: 0 kg; Volume: 0 m3; Gross footprint area: 0 m2; Area per tons: 0 m2; Net surface area: 0.1 m2; Height: 174 mm; Width: 20 mm; Length: 200 mm
Pset_PlateCommon - LoadBearing: no; Reference: L4
BaseQuantities - Width: 174 mm; NetArea: 0.0751339 m2; GrossArea: 0.0348 m2; CrossSectionArea: 0.0004 m2; NetVolume: 0.000557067 m3; GrossVolume: 0.000696 m3

# IfcPlate: BL20*188, GROUT
In: Undefined
Description: BL20*188; Material: Undefined/GROUT
Tekla Common - Bottom elevation: +14.224; Top elevation: +14.412; Phase: 12; Class: 92
Tekla Quantity - Weight: 0 kg; Volume: 0 m3; Gross footprint area: 0 m2; Area per tons: 0 m2; Net surface area: 0.1 m2; Height: 188 mm; Width: 20 mm; Length: 320 mm
Pset_PlateCommon - LoadBearing: no; Reference: L8
BaseQuantities - Width: 188 mm; NetArea: 0.128074 m2; GrossArea: 0.06016 m2; CrossSectionArea: 0.0004 m2; NetVolume: 0.00101067 m3; GrossVolume: 0.0012032 m3

# IfcPlate: BL20*193 (5)
In: Undefined
Description: BL20*193; Material: Undefined/GROUT
Tekla Common - Phase: 8; Class: 92
Tekla Quantity - Weight: 0 kg; Volume: 0 m3; Gross footprint area: 0 m2; Area per tons: 0 m2; Net surface area: 0.1 m2; Height: 193 mm; Width: 20 mm; Length: 200 mm
Pset_PlateCommon - LoadBearing: no; Reference: L5
BaseQuantities - Width: 193 mm; NetArea: 0.0830487 m2; GrossArea: 0.0386 m2; CrossSectionArea: 0.0004 m2; NetVolume: 0.000625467 m3; GrossVolume: 0.000772 m3
Name | Bottom elevation | Top elevation
GROUT | +1.264 | +1.464
GROUT | +18.544 | +18.744
GROUT | +5.584 | +5.784
GROUT | +9.904 | +10.104
GROUT | +14.224 | +14.424

# IfcPlate: BL20*200 (9)
In: Undefined
Description: BL20*200; Material: Undefined/GROUT
Tekla Common - Phase: 8; Class: 92
Tekla Quantity - Weight: 0 kg; Volume: 0 m3; Gross footprint area: 0 m2; Area per tons: 0 m2; Net surface area: 0.1 m2; Height: 200 mm; Width: 20 mm; Length: 320 mm
Pset_PlateCommon - LoadBearing: no; Reference: L2
BaseQuantities - Width: 200 mm; NetArea: 0.135953 m2; GrossArea: 0.064 m2; CrossSectionArea: 0.0004 m2; NetVolume: 0.00108267 m3; GrossVolume: 0.00128 m3
Name | Bottom elevation | Top elevation
2 x GROUT | +1.264 | +1.464
2 x GROUT | +5.584 | +5.784
2 x GROUT | +9.904 | +10.104
GROUT | +14.224 | +14.424
2 x GROUT | +18.544 | +18.744

# IfcPlate: BL20*205 (2)
In: Undefined
Description: BL20*205; Material: Undefined/GROUT
Tekla Common - Bottom elevation: +20.019; Top elevation: +20.224; Phase: 8; Class: 92
Tekla Quantity - Weight: 0 kg; Volume: 0 m3; Gross footprint area: 0 m2; Area per tons: 0 m2; Net surface area: 0.1 m2; Height: 205 mm; Width: 20 mm; Length: 240 mm
Pset_PlateCommon - LoadBearing: no; Reference: L3
BaseQuantities - Width: 205 mm; NetArea: 0.10511 m2; GrossArea: 0.0492 m2; CrossSectionArea: 0.0004 m2; NetVolume: 0.000816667 m3; GrossVolume: 0.000984 m3

# IfcPlate: BL4*100, BLACHA
In: Undefined
Description: BL4*100; Material: STEEL/S355JR
Tekla Common - Bottom elevation: +14.388; Top elevation: +14.392; Phase: 2; Class: 1
Tekla Quantity - Weight: 0.7 kg; Volume: 0 m3; Gross footprint area: 0 m2; Area per tons: 67.2 m2; Net surface area: 0.1 m2; Height: 100 mm; Width: 4 mm; Length: 249.6 mm
Pset_PlateCommon - LoadBearing: yes; Reference: 1158(?)
BaseQuantities - Width: 100 mm; NetArea: 0.0521964 m2; GrossArea: 0.02496 m2; CrossSectionArea: 0.000016 m2; NetVolume: 0.0000989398 m3; GrossVolume: 0.0000989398 m3

# IfcPlate: BL4*2 (10)
In: Undefined
Description: BL4*2; Material: STEEL/S355JR
Pset_PlateCommon - LoadBearing: no
Tekla Common - Phase: 11; Class: 99
Tekla Quantity - Weight: 0 kg; Volume: 0 m3; Gross footprint area: 0 m2; Area per tons: 0 m2; Net surface area: 0 m2; Height: 2 mm; Width: 4 mm; Length: 16 mm
BaseQuantities - Width: 2 mm; NetArea: 0.000208 m2; GrossArea: 0.000032 m2; CrossSectionArea: 0.000016 m2; NetVolume: 1.28e-07 m3; GrossVolume: 1.28e-07 m3
Name | Reference | Bottom elevation | Top elevation
5 x BLACHA | 0(?) | +1.254 | +1.270
2 x BLACHA | 0(?) | +1.253 | +1.268
BLACHA | 0(?) | +1.246 | +1.261
BLACHA | 1091(?) | +1.246 | +1.261
BLACHA | 1091(?) | +1.254 | +1.270

# IfcPlate: BL4*24 (40)
In: Undefined
Description: BL4*24; Material: STEEL/S355JR
Pset_PlateCommon - LoadBearing: no
Tekla Common - Phase: 8; Class: 99
Tekla Quantity - Weight: 0 kg; Volume: 0 m3; Gross footprint area: 0 m2; Net surface area: 0 m2; Width: 4 mm; Length: 60 mm
BaseQuantities - CrossSectionArea: 0.000016 m2
Name | Reference | Bottom elevation | Top elevation | Area per tons (m2) | Height (mm) | Width (mm) | NetArea (m2) | GrossArea (m2) | NetVolume (m3) = GrossVolume (m3)
2 x BLACHA | 0(?) | +0.130 | +0.134 | 78.6 | 24 | 24 | 0.003552 | 0.00144 | 0.00000576
2 x BLACHA | 1090(?) | +0.150 | +0.154 | 78.6 | 24 | 24 | 0.003552 | 0.00144 | 0.00000576
2 x BLACHA | 1090 | +1.208 | +1.212 | 78.6 | 24 | 24 | 0.003552 | 0.00144 | 0.00000576
2 x BLACHA | 1090 | +19.848 | +19.852 | 78.6 | 24 | 24 | 0.003552 | 0.00144 | 0.00000576
2 x BLACHA | 1090 | +18.797 | +18.801 | 78.6 | 24 | 24 | 0.003552 | 0.00144 | 0.00000576
4 x BLACHA | 1090 | +19.857 | +19.861 | 78.6 | 24 | 24 | 0.003552 | 0.00144 | 0.00000576
4 x BLACHA | 1090 | +18.788 | +18.792 | 78.6 | 24 | 24 | 0.003552 | 0.00144 | 0.00000576
2 x BLACHA | 1090(?) | +1.217 | +1.221 | 78.6 | 24 | 24 | 0.003552 | 0.00144 | 0.00000576
2 x BLACHA | 1090(?) | +0.140 | +0.144 | 78.6 | 24 | 24 | 0.003552 | 0.00144 | 0.00000576
2 x BLACHA | 1090(?) | +1.216 | +1.220 | 78.6 | 24 | 24 | 0.003552 | 0.00144 | 0.00000576
BLACHA | 1090 | +14.533 | +14.537 | 78.5 | 24.2 | 24.2148 | 0.00357954 | 0.00145291 | 0.00000581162
BLACHA | 1090 | +14.533 | +14.537 | 78.6 | 23.8 | 23.7859 | 0.00352464 | 0.00142717 | 0.00000570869
BLACHA | 1090 | +18.432 | +18.436 | 78.5 | 24.2 | 24.1999 | 0.00357763 | 0.00145201 | 0.00000580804
BLACHA | 1090 | +18.432 | +18.436 | 78.6 | 23.8 | 23.8008 | 0.00352655 | 0.00142807 | 0.00000571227
BLACHA | 1090 | +18.432 | +18.436 | 78.5 | 24.2 | 24.2148 | 0.00357954 | 0.00145291 | 0.00000581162
BLACHA | 1090 | +18.432 | +18.436 | 78.6 | 23.8 | 23.7859 | 0.00352464 | 0.00142717 | 0.00000570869
BLACHA | 1090 | +14.533 | +14.537 | 78.5 | 24.2 | 24.1996 | 0.0035776 | 0.001452 | 0.00000580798
BLACHA | 1090 | +14.533 | +14.537 | 78.6 | 23.8 | 23.8011 | 0.00352658 | 0.00142808 | 0.00000571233
BLACHA | 1090 | +1.573 | +1.577 | 78.5 | 24.2 | 24.2148 | 0.00357954 | 0.00145291 | 0.00000581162
BLACHA | 1090 | +1.573 | +1.577 | 78.6 | 23.8 | 23.7859 | 0.00352464 | 0.00142717 | 0.00000570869
BLACHA | 1090 | +5.472 | +5.476 | 78.5 | 24.2 | 24.1999 | 0.00357763 | 0.00145201 | 0.00000580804
BLACHA | 1090 | +5.472 | +5.476 | 78.6 | 23.8 | 23.8008 | 0.00352655 | 0.00142807 | 0.00000571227
BLACHA | 1090 | +5.472 | +5.476 | 78.5 | 24.2 | 24.2148 | 0.00357954 | 0.00145291 | 0.00000581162
BLACHA | 1090 | +5.472 | +5.476 | 78.6 | 23.8 | 23.7859 | 0.00352464 | 0.00142717 | 0.00000570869
BLACHA | 1090 | +1.573 | +1.577 | 78.5 | 24.2 | 24.1996 | 0.0035776 | 0.001452 | 0.00000580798
BLACHA | 1090 | +1.573 | +1.577 | 78.6 | 23.8 | 23.8011 | 0.00352658 | 0.00142808 | 0.00000571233

# IfcPlate: BL4*42 (8)
In: Undefined
Description: BL4*42; Material: STEEL/S355JR
Tekla Common - Phase: 2; Class: 99
Tekla Quantity - Weight: 0.2 kg; Volume: 0 m3; Gross footprint area: 0 m2; Area per tons: 71.2 m2; Net surface area: 0 m2; Height: 41.8 mm; Width: 4 mm; Length: 162 mm
Pset_PlateCommon - LoadBearing: no; Reference: 1129
BaseQuantities - Width: 41.85 mm; NetArea: 0.0149433 m2; GrossArea: 0.0067797 m2; CrossSectionArea: 0.000016 m2; NetVolume: 0.0000267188 m3; GrossVolume: 0.0000267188 m3
Name | Bottom elevation | Top elevation
4 x BLACHA | +19.960 | +20.002
4 x BLACHA | +20.007 | +20.049

# IfcPlate: BL4*57 (10)
In: Undefined
Description: BL4*57; Material: STEEL/S355JR
Tekla Common - Phase: 5; Class: 99
Tekla Quantity - Weight: 0.2 kg; Volume: 0 m3; Gross footprint area: 0 m2; Area per tons: 70.7 m2; Net surface area: 0 m2; Height: 56.5 mm; Width: 4 mm; Length: 96 mm
Pset_PlateCommon - LoadBearing: no; Reference: 1127
BaseQuantities - Width: 56.5 mm; NetArea: 0.0115477 m2; GrossArea: 0.005424 m2; CrossSectionArea: 0.000016 m2; NetVolume: 0.000020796 m3; GrossVolume: 0.000020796 m3
Name | Bottom elevation | Top elevation
5 x BLACHA | +19.945 | +20.002
5 x BLACHA | +20.007 | +20.063

# IfcPlate: BL4*90 (5)
In: Undefined
Description: BL4*90; Material: STEEL/S355JR
Tekla Common - Phase: 2; Class: 1
Tekla Quantity - Weight: 5.1 kg; Volume: 0 m3; Gross footprint area: 0 m2; Area per tons: 66.7 m2; Net surface area: 0.3 m2; Height: 89.8 mm; Width: 4 mm; Length: 1800 mm
Pset_PlateCommon - LoadBearing: yes; Reference: 1117
BaseQuantities - Width: 89.8 mm; NetArea: 0.338398 m2; GrossArea: 0.16164 m2; CrossSectionArea: 0.000016 m2; NetVolume: 0.00064656 m3; GrossVolume: 0.00072 m3
Name | Bottom elevation | Top elevation
2 x BLACHA | +10.068 | +10.072
BLACHA | +1.428 | +1.432
BLACHA | +5.617 | +5.621
BLACHA | +14.257 | +14.261

# IfcPlate: BL5*2 (9)
In: Undefined
Description: BL5*2; Material: STEEL/S355JR
Tekla Common - Phase: 11; Class: 99
Tekla Quantity - Weight: 0 kg; Volume: 0 m3; Gross footprint area: 0 m2; Area per tons: 0 m2; Net surface area: 0 m2; Height: 2 mm; Width: 5 mm; Length: 16 mm
Pset_PlateCommon - LoadBearing: no; Reference: p0(?)
BaseQuantities - Width: 2 mm; NetArea: 0.000244 m2; GrossArea: 0.000032 m2; CrossSectionArea: 0.000025 m2; NetVolume: 1.6e-07 m3; GrossVolume: 1.6e-07 m3
Name | Bottom elevation | Top elevation
3 x BLACHA | +1.227 | +1.243
2 x BLACHA | +1.246 | +1.262
2 x BLACHA | +0.123 | +0.138
2 x BLACHA | +1.236 | +1.252

# IfcPlate: BL5*3, BLACHA
In: Undefined
Description: BL5*3; Material: STEEL/S355JR
Tekla Common - Bottom elevation: +1.477; Top elevation: +1.491; Phase: 11; Class: 99
Tekla Quantity - Weight: 0 kg; Volume: 0 m3; Gross footprint area: 0 m2; Area per tons: 0 m2; Net surface area: 0 m2; Height: 3 mm; Width: 5 mm; Length: 16 mm
Pset_PlateCommon - LoadBearing: no; Reference: 1157
BaseQuantities - Width: 3 mm; NetArea: 0.000286 m2; GrossArea: 0.000048 m2; CrossSectionArea: 0.000025 m2; NetVolume: 2.4e-07 m3; GrossVolume: 2.4e-07 m3

# IfcPlate: BL6*40 (4)
In: Undefined
Description: BL6*40; Material: STEEL/S355JR
Tekla Common - Phase: 2; Class: 99
Tekla Quantity - Weight: 0.4 kg; Volume: 0 m3; Gross footprint area: 0 m2; Area per tons: 50.3 m2; Net surface area: 0 m2; Height: 40 mm; Width: 6 mm; Length: 162 mm
Pset_PlateCommon - LoadBearing: no; Reference: 1060
BaseQuantities - Width: 40 mm; NetArea: 0.0148286 m2; GrossArea: 0.00648 m2; CrossSectionArea: 0.000036 m2; NetVolume: 0.00003753 m3; GrossVolume: 0.00003753 m3
Name | Bottom elevation | Top elevation
2 x BLACHA | +19.962 | +20.002
2 x BLACHA | +20.007 | +20.047

# IfcPlate: BL6*50, BLACHA
In: Undefined
Description: BL6*50; Material: STEEL/S355JR
Tekla Common - Bottom elevation: +20.007; Top elevation: +20.057; Phase: 5; Class: 99
Tekla Quantity - Weight: 0.2 kg; Volume: 0 m3; Gross footprint area: 0 m2; Area per tons: 50.1 m2; Net surface area: 0 m2; Height: 50 mm; Width: 6 mm; Length: 96 mm
Pset_PlateCommon - LoadBearing: no; Reference: 1160(?)
BaseQuantities - Width: 50 mm; NetArea: 0.0107966 m2; GrossArea: 0.0048 m2; CrossSectionArea: 0.000036 m2; NetVolume: 0.00002745 m3; GrossVolume: 0.00002745 m3

# IfcPlate: BL6*84 (2)
In: Undefined
Description: BL6*84; Material: STEEL/S355JR
Tekla Common - Bottom elevation: +20.001; Top elevation: +20.007; Phase: 3; Class: 99
Tekla Quantity - Weight: 0.7 kg; Volume: 0 m3; Gross footprint area: 0 m2; Area per tons: 48.7 m2; Net surface area: 0 m2; Height: 83.8 mm; Width: 6 mm; Length: 284.9 mm
Pset_PlateCommon - LoadBearing: no; Reference: 1058
BaseQuantities - Width: 83.79 mm; NetArea: 0.0303713 m2; GrossArea: 0.0238684 m2; CrossSectionArea: 0.000036 m2; NetVolume: 0.0000795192 m3; GrossVolume: 0.0000795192 m3

# IfcPlate: BL6*96, BLACHA
In: Undefined
Description: BL6*96; Material: STEEL/S355JR
Tekla Common - Bottom elevation: +19.862; Top elevation: +20.002; Phase: 5; Class: 99
Tekla Quantity - Weight: 0.7 kg; Volume: 0 m3; Gross footprint area: 0 m2; Area per tons: 46.8 m2; Net surface area: 0 m2; Height: 96 mm; Width: 6 mm; Length: 140 mm
Pset_PlateCommon - LoadBearing: no; Reference: 1161(?)
BaseQuantities - Width: 96 mm; NetArea: 0.0271457 m2; GrossArea: 0.01344 m2; CrossSectionArea: 0.000036 m2; NetVolume: 0.00007389 m3; GrossVolume: 0.00007389 m3

# IfcPlate: BL8*100 (62)
In: Undefined
Description: BL8*100; Material: STEEL/S355JR
Tekla Quantity - Volume: 0 m3; Gross footprint area: 0 m2; Net surface area: 0 m2; Height: 100 mm; Width: 8 mm
BaseQuantities - Width: 100 mm; CrossSectionArea: 0.000064 m2
Name | Bottom elevation | Top elevation | Phase | Class | Weight (kg) | Area per tons (m2) | Length (mm) | LoadBearing | Reference | NetArea (m2) | GrossArea (m2) | NetVolume (m3) = GrossVolume (m3)
2 x BLACHA | +0.013 | +0.153 | 12 | 1 | 0.9 | 36.1 | 140 | yes | 1137(?) | 0.0315463 | 0.014 | 0.0001112
2 x BLACHA | +14.482 | +14.490 | 12 | 99 | 0.7 | 36.9 | 100 | no | 1063 | 0.0232 | 0.01 | 0.00008
2 x BLACHA | +17.046 | +17.054 | 12 | 99 | 0.7 | 36.9 | 100 | no | 1063 | 0.0232 | 0.01 | 0.00008
8 x BLACHA | +20.104 | +20.204 | 7 | 99 | 0.7 | 36.9 | 100 | no | 1063 | 0.0232 | 0.01 | 0.00008
2 x BLACHA | +17.144 | +17.244 | 13 | 99 | 0.7 | 36.9 | 100 | no | 1063 | 0.0232 | 0.01 | 0.00008
BLACHA | +14.714 | +14.814 | 13 | 99 | 0.7 | 36.9 | 100 | no | 1063 | 0.0232 | 0.01 | 0.00008
BLACHA | +16.014 | +16.114 | 13 | 99 | 0.7 | 36.9 | 100 | no | 1063 | 0.0232 | 0.01 | 0.00008
2 x BLACHA | +17.144 | +17.244 | 12 | 99 | 0.7 | 36.9 | 100 | no | 1063 | 0.0232 | 0.01 | 0.00008
2 x BLACHA | +14.292 | +14.392 | 12 | 99 | 0.7 | 36.9 | 100 | no | 1063 | 0.0232 | 0.01 | 0.00008
16 x BLACHA | +20.104 | +20.204 | 12 | 99 | 0.7 | 36.9 | 100 | no | 1063 | 0.0232 | 0.01 | 0.00008
BLACHA | +0.090 | +0.098 | 7 | 99 | 0.7 | 36.9 | 100 | no | 1063(?) | 0.0232 | 0.01 | 0.00008
BLACHA | +1.196 | +1.204 | 7 | 99 | 0.7 | 36.9 | 100 | no | 1063 | 0.0232 | 0.01 | 0.00008
BLACHA | +1.504 | +1.512 | 7 | 99 | 0.7 | 36.9 | 100 | no | 1063 | 0.0232 | 0.01 | 0.00008
BLACHA | +5.516 | +5.524 | 7 | 99 | 0.7 | 36.9 | 100 | no | 1063 | 0.0232 | 0.01 | 0.00008
BLACHA | +5.824 | +5.832 | 7 | 99 | 0.7 | 36.9 | 100 | no | 1063 | 0.0232 | 0.01 | 0.00008
BLACHA | +9.836 | +9.844 | 7 | 99 | 0.7 | 36.9 | 100 | no | 1063 | 0.0232 | 0.01 | 0.00008
BLACHA | +10.144 | +10.152 | 7 | 99 | 0.7 | 36.9 | 100 | no | 1063 | 0.0232 | 0.01 | 0.00008
BLACHA | +14.156 | +14.164 | 7 | 99 | 0.7 | 36.9 | 100 | no | 1063 | 0.0232 | 0.01 | 0.00008
BLACHA | +14.464 | +14.472 | 7 | 99 | 0.7 | 36.9 | 100 | no | 1063 | 0.0232 | 0.01 | 0.00008
BLACHA | +18.476 | +18.484 | 7 | 99 | 0.7 | 36.9 | 100 | no | 1063 | 0.0232 | 0.01 | 0.00008
BLACHA | +18.784 | +18.792 | 7 | 99 | 0.7 | 36.9 | 100 | no | 1063 | 0.0232 | 0.01 | 0.00008
BLACHA | +19.836 | +19.844 | 7 | 99 | 0.7 | 36.9 | 100 | no | 1063 | 0.0232 | 0.01 | 0.00008
BLACHA | +19.856 | +19.864 | 7 | 99 | 0.7 | 36.9 | 100 | no | 1063 | 0.0232 | 0.01 | 0.00008
BLACHA | +18.804 | +18.812 | 7 | 99 | 0.7 | 36.9 | 100 | no | 1063 | 0.0232 | 0.01 | 0.00008
BLACHA | +18.496 | +18.504 | 7 | 99 | 0.7 | 36.9 | 100 | no | 1063 | 0.0232 | 0.01 | 0.00008
BLACHA | +0.109 | +0.117 | 7 | 99 | 0.7 | 36.9 | 100 | no | 1063(?) | 0.0232 | 0.01 | 0.00008
BLACHA | +1.216 | +1.224 | 7 | 99 | 0.7 | 36.9 | 100 | no | 1063(?) | 0.0232 | 0.01 | 0.00008
BLACHA | +1.524 | +1.532 | 7 | 99 | 0.7 | 36.9 | 100 | no | 1063 | 0.0232 | 0.01 | 0.00008
BLACHA | +5.536 | +5.544 | 7 | 99 | 0.7 | 36.9 | 100 | no | 1063 | 0.0232 | 0.01 | 0.00008
BLACHA | +5.844 | +5.852 | 7 | 99 | 0.7 | 36.9 | 100 | no | 1063 | 0.0232 | 0.01 | 0.00008
BLACHA | +9.856 | +9.864 | 7 | 99 | 0.7 | 36.9 | 100 | no | 1063 | 0.0232 | 0.01 | 0.00008
BLACHA | +10.164 | +10.172 | 7 | 99 | 0.7 | 36.9 | 100 | no | 1063 | 0.0232 | 0.01 | 0.00008
BLACHA | +14.176 | +14.184 | 7 | 99 | 0.7 | 36.9 | 100 | no | 1063 | 0.0232 | 0.01 | 0.00008
BLACHA | +14.484 | +14.492 | 7 | 99 | 0.7 | 36.9 | 100 | no | 1063 | 0.0232 | 0.01 | 0.00008

# IfcPlate: BL8*104 (7)
In: Undefined
Description: BL8*104; Material: STEEL/S355JR
Pset_PlateCommon - LoadBearing: no
Tekla Common - Class: 99
Tekla Quantity - Volume: 0 m3; Gross footprint area: 0 m2; Area per tons: 36.4 m2; Net surface area: 0 m2; Height: 104 mm; Width: 8 mm; Length: 120 mm
BaseQuantities - Width: 104 mm; NetArea: 0.028544 m2; GrossArea: 0.01248 m2; CrossSectionArea: 0.000064 m2; NetVolume: 0.00009984 m3; GrossVolume: 0.00009984 m3
Name | Reference | Bottom elevation | Top elevation | Phase | Weight (kg)
2 x BLACHA | 0(?) | -0.064 | -0.056 | 12 | 0.9
2 x BLACHA | 1126(?) | -0.064 | -0.056 | 12 | 0.7
3 x BLACHA | 1126 | +20.064 | +20.072 | 5 | 0.7

# IfcPlate: BL8*120 (6)
In: Undefined
Description: BL8*120; Material: STEEL/S355JR
Tekla Common - Class: 99
Tekla Quantity - Volume: 0 m3; Gross footprint area: 0 m2; Net surface area: 0 m2; Height: 120 mm; Width: 8 mm
Pset_PlateCommon - LoadBearing: no
BaseQuantities - Width: 120 mm; CrossSectionArea: 0.000064 m2
Name | Bottom elevation | Top elevation | Phase | Weight (kg) | Area per tons (m2) | Length (mm) | Reference | NetArea (m2) | GrossArea (m2) | NetVolume (m3) = GrossVolume (m3)
4 x BLACHA | +20.050 | +20.058 | 2 | 1.2 | 35.4 | 175 | 1128 | 0.04672 | 0.021 | 0.000168
BLACHA | +18.513 | +18.521 | 12 | 0.9 | 36.1 | 120 | 1114 | 0.03264 | 0.0144 | 0.0001152
BLACHA | +14.448 | +14.456 | 12 | 0.9 | 36.1 | 120 | 1114 | 0.03264 | 0.0144 | 0.0001152

# IfcPlate: BL8*128 (10)
In: Undefined
Description: BL8*128; Material: STEEL/S355JR
Tekla Common - Phase: 3; Class: 99
Tekla Quantity - Weight: 2 kg; Volume: 0 m3; Gross footprint area: 0 m2; Area per tons: 36 m2; Net surface area: 0.1 m2; Height: 127.9 mm; Width: 8 mm; Length: 438.9 mm
Pset_PlateCommon - LoadBearing: no; Reference: 1025
BaseQuantities - Width: 127.888 mm; NetArea: 0.0683689 m2; GrossArea: 0.0561252 m2; CrossSectionArea: 0.000064 m2; NetVolume: 0.000241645 m3; GrossVolume: 0.000241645 m3
Name | Bottom elevation | Top elevation
2 x BLACHA | +5.680 | +5.688
2 x BLACHA | +10.000 | +10.008
2 x BLACHA | +14.320 | +14.328
2 x BLACHA | +18.640 | +18.648
2 x BLACHA | +1.360 | +1.368

# IfcPlate: BL8*130 (36)
In: Undefined
Description: BL8*130; Material: STEEL/S355JR
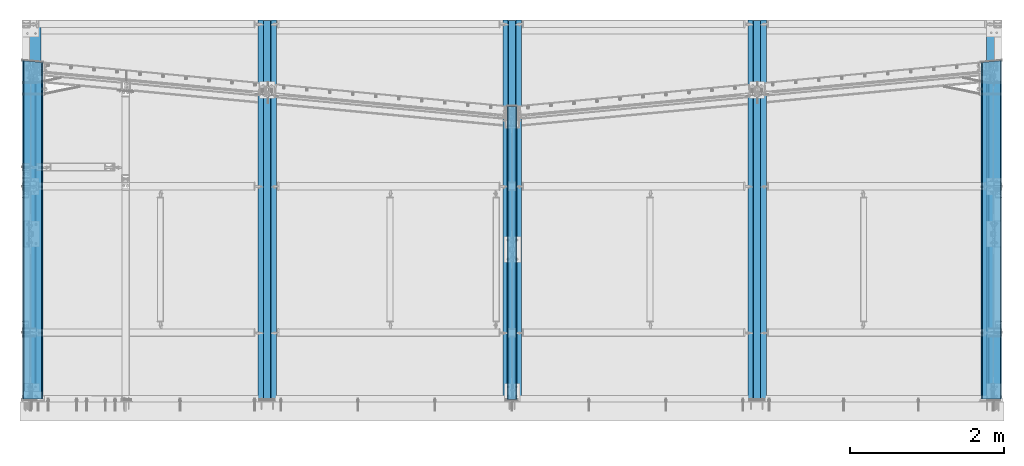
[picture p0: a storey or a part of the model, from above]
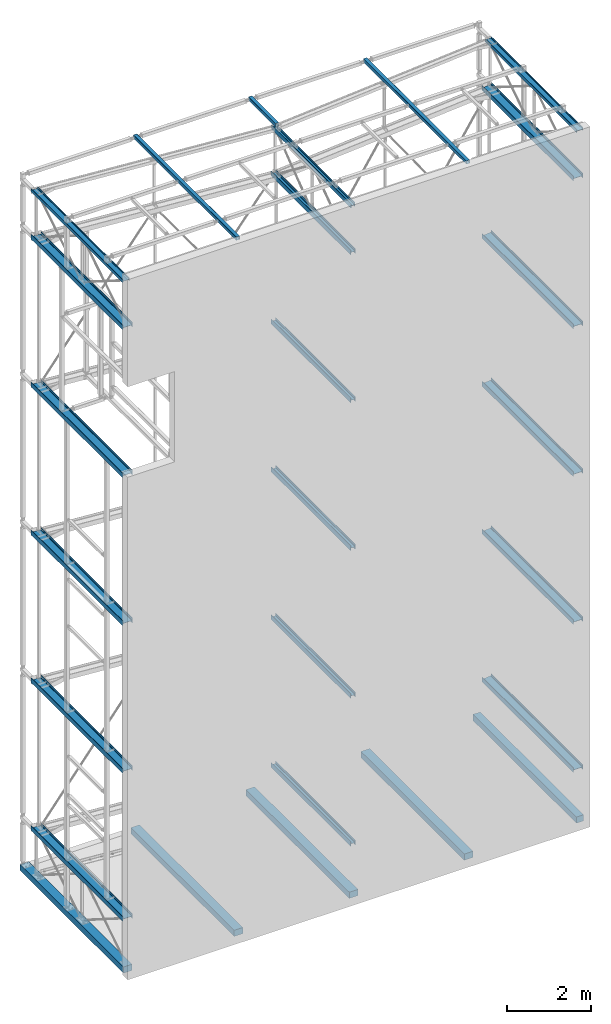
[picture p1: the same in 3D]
Properties of the parts of a building model (IFC2X3), part 3 of 3

# IfcPlate: BL8*130 (36)
Tekla Common - Phase: 12; Class: 1
Tekla Quantity - Volume: 0 m3; Gross footprint area: 0 m2; Net surface area: 0 m2; Height: 130 mm; Width: 8 mm
Pset_PlateCommon - LoadBearing: yes
BaseQuantities - Width: 130 mm; CrossSectionArea: 0.000064 m2
Name | Bottom elevation | Top elevation | Weight (kg) | Area per tons (m2) | Length (mm) | Reference | NetArea (m2) | GrossArea (m2) | NetVolume (m3) = GrossVolume (m3)
2 x BLACHA | +19.859 | +19.999 | 0.9 | 36 | 140 | 1137 | 0.0358046 | 0.0182 | 0.0001266
2 x BLACHA | +18.657 | +18.812 | 1.1 | 35.8 | 155 | 1072 | 0.0399446 | 0.02015 | 0.0001422
2 x BLACHA | +1.197 | +1.352 | 1.1 | 35.8 | 155 | 1072(?) | 0.0399446 | 0.02015 | 0.0001422
BLACHA | +18.477 | +18.632 | 1.1 | 35.8 | 155 | 1072 | 0.0399446 | 0.02015 | 0.0001422
BLACHA | +14.342 | +14.492 | 1.1 | 35.8 | 150 | 1069 | 0.0385646 | 0.0195 | 0.000137
2 x BLACHA | +1.377 | +1.532 | 1.1 | 35.8 | 155 | 1077 | 0.0399446 | 0.02015 | 0.0001422
2 x BLACHA | +5.697 | +5.852 | 1.1 | 35.8 | 155 | 1077 | 0.0399446 | 0.02015 | 0.0001422
2 x BLACHA | +10.017 | +10.172 | 1.1 | 35.8 | 155 | 1077 | 0.0399446 | 0.02015 | 0.0001422
2 x BLACHA | +14.337 | +14.492 | 1.1 | 35.8 | 155 | 1077 | 0.0399446 | 0.02015 | 0.0001422
2 x BLACHA | +14.157 | +14.312 | 1.1 | 35.8 | 155 | 1072 | 0.0399446 | 0.02015 | 0.0001422
2 x BLACHA | +9.837 | +9.992 | 1.1 | 35.8 | 155 | 1072 | 0.0399446 | 0.02015 | 0.0001422
2 x BLACHA | +5.517 | +5.672 | 1.1 | 35.8 | 155 | 1072 | 0.0399446 | 0.02015 | 0.0001422
BLACHA | +18.477 | +18.627 | 1.1 | 35.8 | 150 | 1078 | 0.0385646 | 0.0195 | 0.000137
BLACHA | +18.477 | +18.627 | 1.1 | 35.8 | 150 | 1076 | 0.0385646 | 0.0195 | 0.000137
2 x BLACHA | +14.157 | +14.307 | 1.1 | 35.8 | 150 | 1076 | 0.0385646 | 0.0195 | 0.000137
2 x BLACHA | +9.837 | +9.987 | 1.1 | 35.8 | 150 | 1076 | 0.0385646 | 0.0195 | 0.000137
2 x BLACHA | +5.517 | +5.667 | 1.1 | 35.8 | 150 | 1076 | 0.0385646 | 0.0195 | 0.000137
2 x BLACHA | +10.022 | +10.172 | 1.1 | 35.8 | 150 | 1069 | 0.0385646 | 0.0195 | 0.000137
2 x BLACHA | +5.702 | +5.852 | 1.1 | 35.8 | 150 | 1069 | 0.0385646 | 0.0195 | 0.000137
2 x BLACHA | +1.382 | +1.532 | 1.1 | 35.8 | 150 | 1069 | 0.0385646 | 0.0195 | 0.000137

# IfcPlate: BL8*43 (2)
In: Undefined
Description: BL8*43; Material: STEEL/S355JR
Tekla Common - Bottom elevation: +19.959; Top elevation: +20.002; Phase: 2; Class: 99
Tekla Quantity - Weight: 0.4 kg; Volume: 0 m3; Gross footprint area: 0 m2; Area per tons: 39.3 m2; Net surface area: 0 m2; Height: 42.8 mm; Width: 8 mm; Length: 162 mm
Pset_PlateCommon - LoadBearing: no; Reference: 1134
BaseQuantities - Width: 42.85 mm; NetArea: 0.0168673 m2; GrossArea: 0.0069417 m2; CrossSectionArea: 0.000064 m2; NetVolume: 0.0000547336 m3; GrossVolume: 0.0000547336 m3

# IfcPlate: BL8*58 (2)
In: Undefined
Description: BL8*58; Material: STEEL/S355JR
Tekla Common - Bottom elevation: +0.000; Top elevation: +0.058; Phase: 12; Class: 99
Tekla Quantity - Weight: 0.4 kg; Volume: 0 m3; Gross footprint area: 0 m2; Area per tons: 38.8 m2; Net surface area: 0 m2; Height: 57.8 mm; Width: 8 mm; Length: 100 mm
Pset_PlateCommon - LoadBearing: no; Reference: L0(?)
BaseQuantities - Width: 57.85 mm; NetArea: 0.0140956 m2; GrossArea: 0.005785 m2; CrossSectionArea: 0.000064 m2; NetVolume: 0.00004628 m3; GrossVolume: 0.00004628 m3

# IfcPlate: BL8*60 (50)
In: Undefined
Description: BL8*60; Material: STEEL/S355JR
Tekla Common - Class: 99
Tekla Quantity - Volume: 0 m3; Gross footprint area: 0 m2; Net surface area: 0 m2; Height: 60 mm; Width: 8 mm
Pset_PlateCommon - LoadBearing: no
BaseQuantities - Width: 60 mm; CrossSectionArea: 0.000064 m2
Name | Bottom elevation | Top elevation | Phase | Weight (kg) | Area per tons (m2) | Length (mm) | Reference | NetArea (m2) | GrossArea (m2) | NetVolume (m3) = GrossVolume (m3)
4 x BLACHA | +18.648 | +18.708 | 2 | 0.9 | 37.1 | 247.6 | 1027 | 0.034043 | 0.014856 | 0.000117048
4 x BLACHA | +18.581 | +18.641 | 2 | 0.9 | 37.1 | 247.6 | 1027 | 0.034043 | 0.014856 | 0.000117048
4 x BLACHA | +14.328 | +14.388 | 2 | 0.9 | 37.1 | 247.6 | 1027 | 0.034043 | 0.014856 | 0.000117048
4 x BLACHA | +14.261 | +14.321 | 2 | 0.9 | 37.1 | 247.6 | 1027 | 0.034043 | 0.014856 | 0.000117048
4 x BLACHA | +10.008 | +10.068 | 2 | 0.9 | 37.1 | 247.6 | 1027 | 0.034043 | 0.014856 | 0.000117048
4 x BLACHA | +9.941 | +10.001 | 2 | 0.9 | 37.1 | 247.6 | 1027 | 0.034043 | 0.014856 | 0.000117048
4 x BLACHA | +5.688 | +5.748 | 2 | 0.9 | 37.1 | 247.6 | 1027 | 0.034043 | 0.014856 | 0.000117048
4 x BLACHA | +5.621 | +5.681 | 2 | 0.9 | 37.1 | 247.6 | 1027 | 0.034043 | 0.014856 | 0.000117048
2 x BLACHA | +1.368 | +1.428 | 2 | 0.9 | 37.1 | 247.6 | 1027(?) | 0.034043 | 0.014856 | 0.000117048
2 x BLACHA | +1.301 | +1.361 | 2 | 0.9 | 37.1 | 247.6 | 1027(?) | 0.034043 | 0.014856 | 0.000117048
2 x BLACHA | +1.301 | +1.361 | 2 | 0.9 | 37.1 | 247.6 | 1027 | 0.034043 | 0.014856 | 0.000117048
2 x BLACHA | +1.368 | +1.428 | 2 | 0.9 | 37.1 | 247.6 | 1027 | 0.034043 | 0.014856 | 0.000117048
BLACHA | +18.582 | +18.642 | 5 | 0.4 | 38.2 | 114 | 1042(?) | 0.0158734 | 0.00684 | 0.00005292
BLACHA | +18.647 | +18.707 | 5 | 0.4 | 38.2 | 114 | 1042(?) | 0.0158734 | 0.00684 | 0.00005292
BLACHA | +14.262 | +14.322 | 5 | 0.4 | 38.2 | 114 | 1042(?) | 0.0158734 | 0.00684 | 0.00005292
BLACHA | +14.327 | +14.387 | 5 | 0.4 | 38.2 | 114 | 1042(?) | 0.0158734 | 0.00684 | 0.00005292
BLACHA | +5.622 | +5.682 | 5 | 0.4 | 38.2 | 114 | 1042(?) | 0.0158734 | 0.00684 | 0.00005292
BLACHA | +5.687 | +5.747 | 5 | 0.4 | 38.2 | 114 | 1042(?) | 0.0158734 | 0.00684 | 0.00005292
BLACHA | +1.302 | +1.362 | 5 | 0.4 | 38.2 | 114 | 1042(?) | 0.0158734 | 0.00684 | 0.00005292
BLACHA | +1.367 | +1.427 | 5 | 0.4 | 38.2 | 114 | 1042(?) | 0.0158734 | 0.00684 | 0.00005292
BLACHA | +9.942 | +10.002 | 5 | 0.4 | 38.2 | 114 | 1042(?) | 0.0158734 | 0.00684 | 0.00005292
BLACHA | +10.007 | +10.067 | 5 | 0.4 | 38.2 | 114 | 1042(?) | 0.0158734 | 0.00684 | 0.00005292

# IfcPlate: BL8*64 (34)
In: Undefined
Description: BL8*64; Material: STEEL/S355JR
Tekla Common - Phase: 2; Class: 99
Tekla Quantity - Weight: 0.9 kg; Volume: 0 m3; Gross footprint area: 0 m2; Area per tons: 36.9 m2; Net surface area: 0 m2; Height: 64.2 mm; Width: 8 mm; Length: 247.6 mm
Pset_PlateCommon - LoadBearing: no
BaseQuantities - Width: 64.2 mm; NetArea: 0.0361901 m2; GrossArea: 0.0158959 m2; CrossSectionArea: 0.000064 m2; NetVolume: 0.000125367 m3; GrossVolume: 0.000125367 m3
Name | Bottom elevation | Top elevation | Reference
2 x BLACHA | +18.648 | +18.712 | 1071
BLACHA | +1.297 | +1.361 | 1071(?)
BLACHA | +14.328 | +14.392 | 1070
BLACHA | +18.577 | +18.641 | 1071
BLACHA | +18.577 | +18.641 | 1075
BLACHA | +18.577 | +18.641 | 1074
2 x BLACHA | +14.257 | +14.321 | 1074
2 x BLACHA | +14.328 | +14.392 | 1073
2 x BLACHA | +9.937 | +10.001 | 1074
2 x BLACHA | +10.008 | +10.072 | 1073
2 x BLACHA | +1.368 | +1.432 | 1073
BLACHA | +1.297 | +1.361 | 1071
2 x BLACHA | +5.617 | +5.681 | 1074
2 x BLACHA | +5.688 | +5.752 | 1073
2 x BLACHA | +14.257 | +14.321 | 1071
2 x BLACHA | +9.937 | +10.001 | 1071
2 x BLACHA | +10.008 | +10.072 | 1070
2 x BLACHA | +1.368 | +1.432 | 1070(?)
2 x BLACHA | +5.617 | +5.681 | 1071
2 x BLACHA | +5.688 | +5.752 | 1070

# IfcPlate: BL8*80 (92)
In: Undefined
Description: BL8*80; Material: STEEL/S355JR
Pset_PlateCommon - LoadBearing: no
Tekla Common - Class: 99
Tekla Quantity - Weight: 0.4 kg; Volume: 0 m3; Gross footprint area: 0 m2; Area per tons: 38.2 m2; Net surface area: 0 m2; Height: 80 mm; Width: 8 mm; Length: 80 mm
BaseQuantities - Width: 80 mm; NetArea: 0.01536 m2; GrossArea: 0.0064 m2; CrossSectionArea: 0.000064 m2; NetVolume: 0.0000512 m3; GrossVolume: 0.0000512 m3
Name | Reference | Bottom elevation | Top elevation | Phase
BLACHA | 0(?) | +1.233 | +1.241 | 12
2 x BLACHA | 1079(?) | +0.110 | +0.118 | 8
BLACHA | 1079 | +19.864 | +19.872 | 8
10 x BLACHA | 1079 | +20.124 | +20.204 | 13
BLACHA | 1079 | +18.504 | +18.512 | 8
BLACHA | 1079 | +14.457 | +14.465 | 8
BLACHA | 1079 | +5.544 | +5.552 | 8
BLACHA | 1079 | +1.497 | +1.505 | 8
2 x BLACHA | 1079 | +14.498 | +14.506 | 8
2 x BLACHA | 1079 | +18.463 | +18.471 | 8
2 x BLACHA | 1079 | +1.538 | +1.546 | 8
2 x BLACHA | 1079 | +5.503 | +5.511 | 8
BLACHA | 1079(?) | +0.130 | +0.138 | 8
BLACHA | 1079(?) | +0.100 | +0.108 | 12
BLACHA | 1079(?) | +0.100 | +0.108 | 8
2 x BLACHA | 1079 | +19.894 | +19.902 | 8
4 x BLACHA | 1079 | +18.768 | +18.776 | 8
BLACHA | 1079 | +19.873 | +19.881 | 8
BLACHA | 1079 | +19.893 | +19.901 | 8
2 x BLACHA | 1079(?) | +1.233 | +1.241 | 8
2 x BLACHA | 1079 | +4.459 | +4.539 | 13
2 x BLACHA | 1079 | +3.319 | +3.399 | 13
2 x BLACHA | 1079 | +3.039 | +3.119 | 13
2 x BLACHA | 1079 | +1.659 | +1.739 | 13
2 x BLACHA | 1079 | +9.630 | +9.710 | 13
2 x BLACHA | 1079 | +8.250 | +8.330 | 13
4 x BLACHA | 1079 | +11.372 | +11.452 | 13
2 x BLACHA | 1079 | +7.114 | +7.194 | 13
2 x BLACHA | 1079 | +8.494 | +8.574 | 13
2 x BLACHA | 1079 | +15.754 | +15.834 | 13
2 x BLACHA | 1079 | +17.134 | +17.214 | 13
2 x BLACHA | 1079 | +2.732 | +2.812 | 13
2 x BLACHA | 1079 | +4.237 | +4.317 | 13
2 x BLACHA | 1079 | +12.877 | +12.957 | 13
BLACHA | 1079 | +18.777 | +18.785 | 8
BLACHA | 1079 | +1.224 | +1.232 | 8
BLACHA | 1079 | +5.817 | +5.825 | 8
BLACHA | 1079 | +14.184 | +14.192 | 8
BLACHA | 1079 | +10.137 | +10.145 | 8
4 x BLACHA | 1079 | +5.808 | +5.816 | 8
4 x BLACHA | 1079 | +9.873 | +9.881 | 8
4 x BLACHA | 1079 | +10.128 | +10.136 | 8
4 x BLACHA | 1079 | +14.193 | +14.201 | 8
BLACHA | 1079 | +9.864 | +9.872 | 8
BLACHA | 1079 | +1.233 | +1.241 | 8

# IfcSlab: 250*12780, PŁYTA
In: Undefined
Description: 250*12780; PredefinedType: FLOOR; Material: CONCRETE/C25/30
Tekla Common - Bottom elevation: -0.226; Top elevation: +20.234; Phase: 1; Class: 1
Tekla Quantity - Weight: 154841 kg; Volume: 64.5 m3; Gross footprint area: 258.1 m2; Area per tons: 3.4 m2; Net surface area: 533.4 m2; Height: 12780 mm; Width: 250 mm; Length: 20460 mm
Pset_SlabCommon - LoadBearing: no; Reference: P1
BaseQuantities - Width: 250 mm; NetVolume: 64.517 m3; NetArea: 258.068 m2; NetWeight: 154841 kg
